VERSION 5.8 ;
BUSBITCHARS "[]" ;
DIVIDERCHAR "/" ;
UNITS
    DATABASE MICRONS 1000 ;
END UNITS

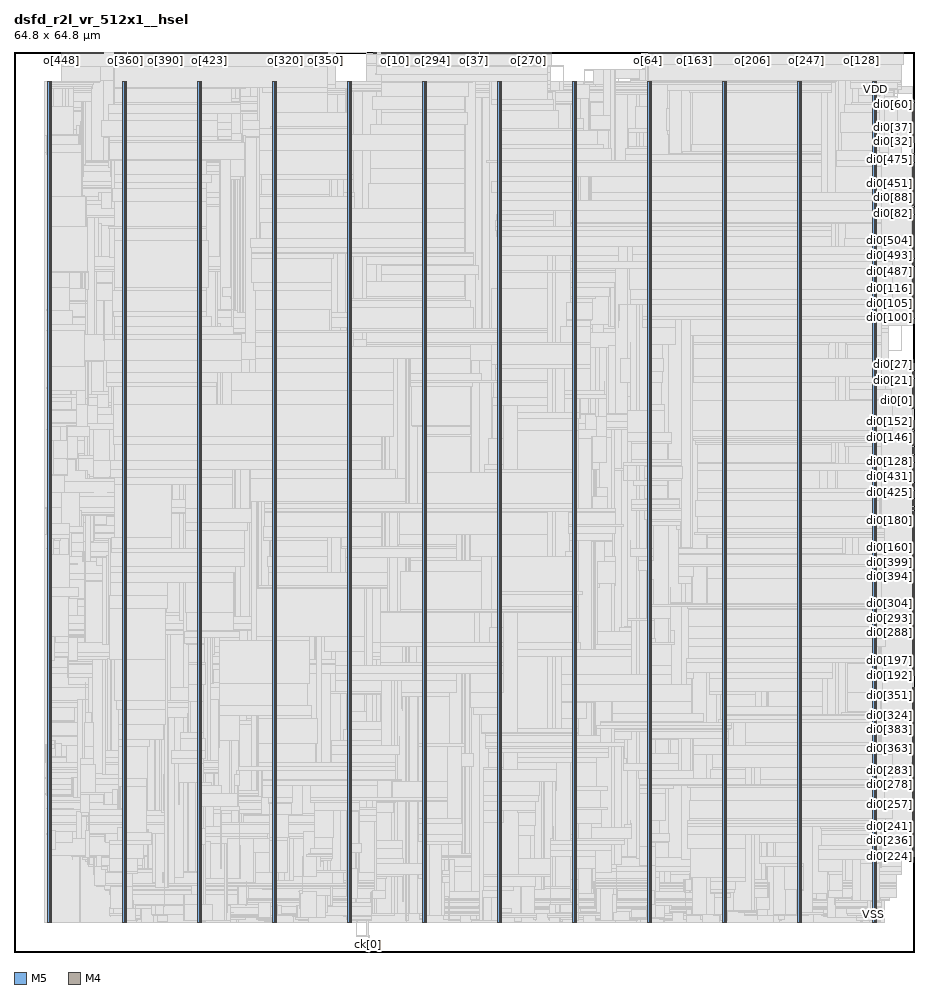
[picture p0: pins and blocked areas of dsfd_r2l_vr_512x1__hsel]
MACRO dsfd_r2l_vr_512x1__hsel
  FOREIGN dsfd_r2l_vr_512x1__hsel 0 0 ;
  CLASS BLOCK ;
  SIZE 64.8 BY 64.8 ;
  PIN ck[0]
    DIRECTION INPUT ;
    USE SIGNAL ;
    PORT
      LAYER M5 ;
        RECT  25.488 0 25.512 0.084 ;
    END
  END ck[0]
  PIN di0[0]
    DIRECTION INPUT ;
    USE SIGNAL ;
    PORT
      LAYER M4 ;
        RECT  64.716 39.12 64.8 39.144 ;
    END
  END di0[0]
  PIN di0[100]
    DIRECTION INPUT ;
    USE SIGNAL ;
    PORT
      LAYER M4 ;
        RECT  64.716 45.648 64.8 45.672 ;
    END
  END di0[100]
  PIN di0[101]
    DIRECTION INPUT ;
    USE SIGNAL ;
    PORT
      LAYER M4 ;
        RECT  64.716 45.744 64.8 45.768 ;
    END
  END di0[101]
  PIN di0[102]
    DIRECTION INPUT ;
    USE SIGNAL ;
    PORT
      LAYER M4 ;
        RECT  64.716 45.84 64.8 45.864 ;
    END
  END di0[102]
  PIN di0[103]
    DIRECTION INPUT ;
    USE SIGNAL ;
    PORT
      LAYER M4 ;
        RECT  64.716 45.936 64.8 45.96 ;
    END
  END di0[103]
  PIN di0[104]
    DIRECTION INPUT ;
    USE SIGNAL ;
    PORT
      LAYER M4 ;
        RECT  64.716 46.032 64.8 46.056 ;
    END
  END di0[104]
  PIN di0[105]
    DIRECTION INPUT ;
    USE SIGNAL ;
    PORT
      LAYER M4 ;
        RECT  64.716 46.128 64.8 46.152 ;
    END
  END di0[105]
  PIN di0[106]
    DIRECTION INPUT ;
    USE SIGNAL ;
    PORT
      LAYER M4 ;
        RECT  64.716 46.224 64.8 46.248 ;
    END
  END di0[106]
  PIN di0[107]
    DIRECTION INPUT ;
    USE SIGNAL ;
    PORT
      LAYER M4 ;
        RECT  64.716 46.32 64.8 46.344 ;
    END
  END di0[107]
  PIN di0[108]
    DIRECTION INPUT ;
    USE SIGNAL ;
    PORT
      LAYER M4 ;
        RECT  64.716 46.416 64.8 46.44 ;
    END
  END di0[108]
  PIN di0[109]
    DIRECTION INPUT ;
    USE SIGNAL ;
    PORT
      LAYER M4 ;
        RECT  64.716 46.512 64.8 46.536 ;
    END
  END di0[109]
  PIN di0[10]
    DIRECTION INPUT ;
    USE SIGNAL ;
    PORT
      LAYER M4 ;
        RECT  64.716 40.08 64.8 40.104 ;
    END
  END di0[10]
  PIN di0[110]
    DIRECTION INPUT ;
    USE SIGNAL ;
    PORT
      LAYER M4 ;
        RECT  64.716 46.608 64.8 46.632 ;
    END
  END di0[110]
  PIN di0[111]
    DIRECTION INPUT ;
    USE SIGNAL ;
    PORT
      LAYER M4 ;
        RECT  64.716 46.704 64.8 46.728 ;
    END
  END di0[111]
  PIN di0[112]
    DIRECTION INPUT ;
    USE SIGNAL ;
    PORT
      LAYER M4 ;
        RECT  64.716 46.8 64.8 46.824 ;
    END
  END di0[112]
  PIN di0[113]
    DIRECTION INPUT ;
    USE SIGNAL ;
    PORT
      LAYER M4 ;
        RECT  64.716 46.896 64.8 46.92 ;
    END
  END di0[113]
  PIN di0[114]
    DIRECTION INPUT ;
    USE SIGNAL ;
    PORT
      LAYER M4 ;
        RECT  64.716 46.992 64.8 47.016 ;
    END
  END di0[114]
  PIN di0[115]
    DIRECTION INPUT ;
    USE SIGNAL ;
    PORT
      LAYER M4 ;
        RECT  64.716 47.088 64.8 47.112 ;
    END
  END di0[115]
  PIN di0[116]
    DIRECTION INPUT ;
    USE SIGNAL ;
    PORT
      LAYER M4 ;
        RECT  64.716 47.184 64.8 47.208 ;
    END
  END di0[116]
  PIN di0[117]
    DIRECTION INPUT ;
    USE SIGNAL ;
    PORT
      LAYER M4 ;
        RECT  64.716 47.28 64.8 47.304 ;
    END
  END di0[117]
  PIN di0[118]
    DIRECTION INPUT ;
    USE SIGNAL ;
    PORT
      LAYER M4 ;
        RECT  64.716 47.376 64.8 47.4 ;
    END
  END di0[118]
  PIN di0[119]
    DIRECTION INPUT ;
    USE SIGNAL ;
    PORT
      LAYER M4 ;
        RECT  64.716 47.472 64.8 47.496 ;
    END
  END di0[119]
  PIN di0[11]
    DIRECTION INPUT ;
    USE SIGNAL ;
    PORT
      LAYER M4 ;
        RECT  64.716 40.176 64.8 40.2 ;
    END
  END di0[11]
  PIN di0[120]
    DIRECTION INPUT ;
    USE SIGNAL ;
    PORT
      LAYER M4 ;
        RECT  64.716 47.568 64.8 47.592 ;
    END
  END di0[120]
  PIN di0[121]
    DIRECTION INPUT ;
    USE SIGNAL ;
    PORT
      LAYER M4 ;
        RECT  64.716 47.664 64.8 47.688 ;
    END
  END di0[121]
  PIN di0[122]
    DIRECTION INPUT ;
    USE SIGNAL ;
    PORT
      LAYER M4 ;
        RECT  64.716 47.76 64.8 47.784 ;
    END
  END di0[122]
  PIN di0[123]
    DIRECTION INPUT ;
    USE SIGNAL ;
    PORT
      LAYER M4 ;
        RECT  64.716 47.856 64.8 47.88 ;
    END
  END di0[123]
  PIN di0[124]
    DIRECTION INPUT ;
    USE SIGNAL ;
    PORT
      LAYER M4 ;
        RECT  64.716 47.952 64.8 47.976 ;
    END
  END di0[124]
  PIN di0[125]
    DIRECTION INPUT ;
    USE SIGNAL ;
    PORT
      LAYER M4 ;
        RECT  64.716 48.048 64.8 48.072 ;
    END
  END di0[125]
  PIN di0[126]
    DIRECTION INPUT ;
    USE SIGNAL ;
    PORT
      LAYER M4 ;
        RECT  64.716 48.144 64.8 48.168 ;
    END
  END di0[126]
  PIN di0[127]
    DIRECTION INPUT ;
    USE SIGNAL ;
    PORT
      LAYER M4 ;
        RECT  64.716 48.24 64.8 48.264 ;
    END
  END di0[127]
  PIN di0[128]
    DIRECTION INPUT ;
    USE SIGNAL ;
    PORT
      LAYER M4 ;
        RECT  64.716 35.28 64.8 35.304 ;
    END
  END di0[128]
  PIN di0[129]
    DIRECTION INPUT ;
    USE SIGNAL ;
    PORT
      LAYER M4 ;
        RECT  64.716 35.376 64.8 35.4 ;
    END
  END di0[129]
  PIN di0[12]
    DIRECTION INPUT ;
    USE SIGNAL ;
    PORT
      LAYER M4 ;
        RECT  64.716 40.272 64.8 40.296 ;
    END
  END di0[12]
  PIN di0[130]
    DIRECTION INPUT ;
    USE SIGNAL ;
    PORT
      LAYER M4 ;
        RECT  64.716 35.472 64.8 35.496 ;
    END
  END di0[130]
  PIN di0[131]
    DIRECTION INPUT ;
    USE SIGNAL ;
    PORT
      LAYER M4 ;
        RECT  64.716 35.568 64.8 35.592 ;
    END
  END di0[131]
  PIN di0[132]
    DIRECTION INPUT ;
    USE SIGNAL ;
    PORT
      LAYER M4 ;
        RECT  64.716 35.664 64.8 35.688 ;
    END
  END di0[132]
  PIN di0[133]
    DIRECTION INPUT ;
    USE SIGNAL ;
    PORT
      LAYER M4 ;
        RECT  64.716 35.76 64.8 35.784 ;
    END
  END di0[133]
  PIN di0[134]
    DIRECTION INPUT ;
    USE SIGNAL ;
    PORT
      LAYER M4 ;
        RECT  64.716 35.856 64.8 35.88 ;
    END
  END di0[134]
  PIN di0[135]
    DIRECTION INPUT ;
    USE SIGNAL ;
    PORT
      LAYER M4 ;
        RECT  64.716 35.952 64.8 35.976 ;
    END
  END di0[135]
  PIN di0[136]
    DIRECTION INPUT ;
    USE SIGNAL ;
    PORT
      LAYER M4 ;
        RECT  64.716 36.048 64.8 36.072 ;
    END
  END di0[136]
  PIN di0[137]
    DIRECTION INPUT ;
    USE SIGNAL ;
    PORT
      LAYER M4 ;
        RECT  64.716 36.144 64.8 36.168 ;
    END
  END di0[137]
  PIN di0[138]
    DIRECTION INPUT ;
    USE SIGNAL ;
    PORT
      LAYER M4 ;
        RECT  64.716 36.24 64.8 36.264 ;
    END
  END di0[138]
  PIN di0[139]
    DIRECTION INPUT ;
    USE SIGNAL ;
    PORT
      LAYER M4 ;
        RECT  64.716 36.336 64.8 36.36 ;
    END
  END di0[139]
  PIN di0[13]
    DIRECTION INPUT ;
    USE SIGNAL ;
    PORT
      LAYER M4 ;
        RECT  64.716 40.368 64.8 40.392 ;
    END
  END di0[13]
  PIN di0[140]
    DIRECTION INPUT ;
    USE SIGNAL ;
    PORT
      LAYER M4 ;
        RECT  64.716 36.432 64.8 36.456 ;
    END
  END di0[140]
  PIN di0[141]
    DIRECTION INPUT ;
    USE SIGNAL ;
    PORT
      LAYER M4 ;
        RECT  64.716 36.528 64.8 36.552 ;
    END
  END di0[141]
  PIN di0[142]
    DIRECTION INPUT ;
    USE SIGNAL ;
    PORT
      LAYER M4 ;
        RECT  64.716 36.624 64.8 36.648 ;
    END
  END di0[142]
  PIN di0[143]
    DIRECTION INPUT ;
    USE SIGNAL ;
    PORT
      LAYER M4 ;
        RECT  64.716 36.72 64.8 36.744 ;
    END
  END di0[143]
  PIN di0[144]
    DIRECTION INPUT ;
    USE SIGNAL ;
    PORT
      LAYER M4 ;
        RECT  64.716 36.816 64.8 36.84 ;
    END
  END di0[144]
  PIN di0[145]
    DIRECTION INPUT ;
    USE SIGNAL ;
    PORT
      LAYER M4 ;
        RECT  64.716 36.912 64.8 36.936 ;
    END
  END di0[145]
  PIN di0[146]
    DIRECTION INPUT ;
    USE SIGNAL ;
    PORT
      LAYER M4 ;
        RECT  64.716 37.008 64.8 37.032 ;
    END
  END di0[146]
  PIN di0[147]
    DIRECTION INPUT ;
    USE SIGNAL ;
    PORT
      LAYER M4 ;
        RECT  64.716 37.104 64.8 37.128 ;
    END
  END di0[147]
  PIN di0[148]
    DIRECTION INPUT ;
    USE SIGNAL ;
    PORT
      LAYER M4 ;
        RECT  64.716 37.2 64.8 37.224 ;
    END
  END di0[148]
  PIN di0[149]
    DIRECTION INPUT ;
    USE SIGNAL ;
    PORT
      LAYER M4 ;
        RECT  64.716 37.296 64.8 37.32 ;
    END
  END di0[149]
  PIN di0[14]
    DIRECTION INPUT ;
    USE SIGNAL ;
    PORT
      LAYER M4 ;
        RECT  64.716 40.464 64.8 40.488 ;
    END
  END di0[14]
  PIN di0[150]
    DIRECTION INPUT ;
    USE SIGNAL ;
    PORT
      LAYER M4 ;
        RECT  64.716 37.392 64.8 37.416 ;
    END
  END di0[150]
  PIN di0[151]
    DIRECTION INPUT ;
    USE SIGNAL ;
    PORT
      LAYER M4 ;
        RECT  64.716 37.488 64.8 37.512 ;
    END
  END di0[151]
  PIN di0[152]
    DIRECTION INPUT ;
    USE SIGNAL ;
    PORT
      LAYER M4 ;
        RECT  64.716 37.584 64.8 37.608 ;
    END
  END di0[152]
  PIN di0[153]
    DIRECTION INPUT ;
    USE SIGNAL ;
    PORT
      LAYER M4 ;
        RECT  64.716 37.68 64.8 37.704 ;
    END
  END di0[153]
  PIN di0[154]
    DIRECTION INPUT ;
    USE SIGNAL ;
    PORT
      LAYER M4 ;
        RECT  64.716 37.776 64.8 37.8 ;
    END
  END di0[154]
  PIN di0[155]
    DIRECTION INPUT ;
    USE SIGNAL ;
    PORT
      LAYER M4 ;
        RECT  64.716 37.872 64.8 37.896 ;
    END
  END di0[155]
  PIN di0[156]
    DIRECTION INPUT ;
    USE SIGNAL ;
    PORT
      LAYER M4 ;
        RECT  64.716 37.968 64.8 37.992 ;
    END
  END di0[156]
  PIN di0[157]
    DIRECTION INPUT ;
    USE SIGNAL ;
    PORT
      LAYER M4 ;
        RECT  64.716 38.064 64.8 38.088 ;
    END
  END di0[157]
  PIN di0[158]
    DIRECTION INPUT ;
    USE SIGNAL ;
    PORT
      LAYER M4 ;
        RECT  64.716 38.16 64.8 38.184 ;
    END
  END di0[158]
  PIN di0[159]
    DIRECTION INPUT ;
    USE SIGNAL ;
    PORT
      LAYER M4 ;
        RECT  64.716 38.256 64.8 38.28 ;
    END
  END di0[159]
  PIN di0[15]
    DIRECTION INPUT ;
    USE SIGNAL ;
    PORT
      LAYER M4 ;
        RECT  64.716 40.56 64.8 40.584 ;
    END
  END di0[15]
  PIN di0[160]
    DIRECTION INPUT ;
    USE SIGNAL ;
    PORT
      LAYER M4 ;
        RECT  64.716 29.136 64.8 29.16 ;
    END
  END di0[160]
  PIN di0[161]
    DIRECTION INPUT ;
    USE SIGNAL ;
    PORT
      LAYER M4 ;
        RECT  64.716 29.232 64.8 29.256 ;
    END
  END di0[161]
  PIN di0[162]
    DIRECTION INPUT ;
    USE SIGNAL ;
    PORT
      LAYER M4 ;
        RECT  64.716 29.328 64.8 29.352 ;
    END
  END di0[162]
  PIN di0[163]
    DIRECTION INPUT ;
    USE SIGNAL ;
    PORT
      LAYER M4 ;
        RECT  64.716 29.424 64.8 29.448 ;
    END
  END di0[163]
  PIN di0[164]
    DIRECTION INPUT ;
    USE SIGNAL ;
    PORT
      LAYER M4 ;
        RECT  64.716 29.52 64.8 29.544 ;
    END
  END di0[164]
  PIN di0[165]
    DIRECTION INPUT ;
    USE SIGNAL ;
    PORT
      LAYER M4 ;
        RECT  64.716 29.616 64.8 29.64 ;
    END
  END di0[165]
  PIN di0[166]
    DIRECTION INPUT ;
    USE SIGNAL ;
    PORT
      LAYER M4 ;
        RECT  64.716 29.712 64.8 29.736 ;
    END
  END di0[166]
  PIN di0[167]
    DIRECTION INPUT ;
    USE SIGNAL ;
    PORT
      LAYER M4 ;
        RECT  64.716 29.808 64.8 29.832 ;
    END
  END di0[167]
  PIN di0[168]
    DIRECTION INPUT ;
    USE SIGNAL ;
    PORT
      LAYER M4 ;
        RECT  64.716 29.904 64.8 29.928 ;
    END
  END di0[168]
  PIN di0[169]
    DIRECTION INPUT ;
    USE SIGNAL ;
    PORT
      LAYER M4 ;
        RECT  64.716 30 64.8 30.024 ;
    END
  END di0[169]
  PIN di0[16]
    DIRECTION INPUT ;
    USE SIGNAL ;
    PORT
      LAYER M4 ;
        RECT  64.716 40.656 64.8 40.68 ;
    END
  END di0[16]
  PIN di0[170]
    DIRECTION INPUT ;
    USE SIGNAL ;
    PORT
      LAYER M4 ;
        RECT  64.716 30.096 64.8 30.12 ;
    END
  END di0[170]
  PIN di0[171]
    DIRECTION INPUT ;
    USE SIGNAL ;
    PORT
      LAYER M4 ;
        RECT  64.716 30.192 64.8 30.216 ;
    END
  END di0[171]
  PIN di0[172]
    DIRECTION INPUT ;
    USE SIGNAL ;
    PORT
      LAYER M4 ;
        RECT  64.716 30.288 64.8 30.312 ;
    END
  END di0[172]
  PIN di0[173]
    DIRECTION INPUT ;
    USE SIGNAL ;
    PORT
      LAYER M4 ;
        RECT  64.716 30.384 64.8 30.408 ;
    END
  END di0[173]
  PIN di0[174]
    DIRECTION INPUT ;
    USE SIGNAL ;
    PORT
      LAYER M4 ;
        RECT  64.716 30.48 64.8 30.504 ;
    END
  END di0[174]
  PIN di0[175]
    DIRECTION INPUT ;
    USE SIGNAL ;
    PORT
      LAYER M4 ;
        RECT  64.716 30.576 64.8 30.6 ;
    END
  END di0[175]
  PIN di0[176]
    DIRECTION INPUT ;
    USE SIGNAL ;
    PORT
      LAYER M4 ;
        RECT  64.716 30.672 64.8 30.696 ;
    END
  END di0[176]
  PIN di0[177]
    DIRECTION INPUT ;
    USE SIGNAL ;
    PORT
      LAYER M4 ;
        RECT  64.716 30.768 64.8 30.792 ;
    END
  END di0[177]
  PIN di0[178]
    DIRECTION INPUT ;
    USE SIGNAL ;
    PORT
      LAYER M4 ;
        RECT  64.716 30.864 64.8 30.888 ;
    END
  END di0[178]
  PIN di0[179]
    DIRECTION INPUT ;
    USE SIGNAL ;
    PORT
      LAYER M4 ;
        RECT  64.716 30.96 64.8 30.984 ;
    END
  END di0[179]
  PIN di0[17]
    DIRECTION INPUT ;
    USE SIGNAL ;
    PORT
      LAYER M4 ;
        RECT  64.716 40.752 64.8 40.776 ;
    END
  END di0[17]
  PIN di0[180]
    DIRECTION INPUT ;
    USE SIGNAL ;
    PORT
      LAYER M4 ;
        RECT  64.716 31.056 64.8 31.08 ;
    END
  END di0[180]
  PIN di0[181]
    DIRECTION INPUT ;
    USE SIGNAL ;
    PORT
      LAYER M4 ;
        RECT  64.716 31.152 64.8 31.176 ;
    END
  END di0[181]
  PIN di0[182]
    DIRECTION INPUT ;
    USE SIGNAL ;
    PORT
      LAYER M4 ;
        RECT  64.716 31.248 64.8 31.272 ;
    END
  END di0[182]
  PIN di0[183]
    DIRECTION INPUT ;
    USE SIGNAL ;
    PORT
      LAYER M4 ;
        RECT  64.716 31.344 64.8 31.368 ;
    END
  END di0[183]
  PIN di0[184]
    DIRECTION INPUT ;
    USE SIGNAL ;
    PORT
      LAYER M4 ;
        RECT  64.716 31.44 64.8 31.464 ;
    END
  END di0[184]
  PIN di0[185]
    DIRECTION INPUT ;
    USE SIGNAL ;
    PORT
      LAYER M4 ;
        RECT  64.716 31.536 64.8 31.56 ;
    END
  END di0[185]
  PIN di0[186]
    DIRECTION INPUT ;
    USE SIGNAL ;
    PORT
      LAYER M4 ;
        RECT  64.716 31.632 64.8 31.656 ;
    END
  END di0[186]
  PIN di0[187]
    DIRECTION INPUT ;
    USE SIGNAL ;
    PORT
      LAYER M4 ;
        RECT  64.716 31.728 64.8 31.752 ;
    END
  END di0[187]
  PIN di0[188]
    DIRECTION INPUT ;
    USE SIGNAL ;
    PORT
      LAYER M4 ;
        RECT  64.716 31.824 64.8 31.848 ;
    END
  END di0[188]
  PIN di0[189]
    DIRECTION INPUT ;
    USE SIGNAL ;
    PORT
      LAYER M4 ;
        RECT  64.716 31.92 64.8 31.944 ;
    END
  END di0[189]
  PIN di0[18]
    DIRECTION INPUT ;
    USE SIGNAL ;
    PORT
      LAYER M4 ;
        RECT  64.716 40.848 64.8 40.872 ;
    END
  END di0[18]
  PIN di0[190]
    DIRECTION INPUT ;
    USE SIGNAL ;
    PORT
      LAYER M4 ;
        RECT  64.716 32.016 64.8 32.04 ;
    END
  END di0[190]
  PIN di0[191]
    DIRECTION INPUT ;
    USE SIGNAL ;
    PORT
      LAYER M4 ;
        RECT  64.716 32.112 64.8 32.136 ;
    END
  END di0[191]
  PIN di0[192]
    DIRECTION INPUT ;
    USE SIGNAL ;
    PORT
      LAYER M4 ;
        RECT  64.716 19.92 64.8 19.944 ;
    END
  END di0[192]
  PIN di0[193]
    DIRECTION INPUT ;
    USE SIGNAL ;
    PORT
      LAYER M4 ;
        RECT  64.716 20.016 64.8 20.04 ;
    END
  END di0[193]
  PIN di0[194]
    DIRECTION INPUT ;
    USE SIGNAL ;
    PORT
      LAYER M4 ;
        RECT  64.716 20.112 64.8 20.136 ;
    END
  END di0[194]
  PIN di0[195]
    DIRECTION INPUT ;
    USE SIGNAL ;
    PORT
      LAYER M4 ;
        RECT  64.716 20.208 64.8 20.232 ;
    END
  END di0[195]
  PIN di0[196]
    DIRECTION INPUT ;
    USE SIGNAL ;
    PORT
      LAYER M4 ;
        RECT  64.716 20.304 64.8 20.328 ;
    END
  END di0[196]
  PIN di0[197]
    DIRECTION INPUT ;
    USE SIGNAL ;
    PORT
      LAYER M4 ;
        RECT  64.716 20.4 64.8 20.424 ;
    END
  END di0[197]
  PIN di0[198]
    DIRECTION INPUT ;
    USE SIGNAL ;
    PORT
      LAYER M4 ;
        RECT  64.716 20.496 64.8 20.52 ;
    END
  END di0[198]
  PIN di0[199]
    DIRECTION INPUT ;
    USE SIGNAL ;
    PORT
      LAYER M4 ;
        RECT  64.716 20.592 64.8 20.616 ;
    END
  END di0[199]
  PIN di0[19]
    DIRECTION INPUT ;
    USE SIGNAL ;
    PORT
      LAYER M4 ;
        RECT  64.716 40.944 64.8 40.968 ;
    END
  END di0[19]
  PIN di0[1]
    DIRECTION INPUT ;
    USE SIGNAL ;
    PORT
      LAYER M4 ;
        RECT  64.716 39.216 64.8 39.24 ;
    END
  END di0[1]
  PIN di0[200]
    DIRECTION INPUT ;
    USE SIGNAL ;
    PORT
      LAYER M4 ;
        RECT  64.716 20.688 64.8 20.712 ;
    END
  END di0[200]
  PIN di0[201]
    DIRECTION INPUT ;
    USE SIGNAL ;
    PORT
      LAYER M4 ;
        RECT  64.716 20.784 64.8 20.808 ;
    END
  END di0[201]
  PIN di0[202]
    DIRECTION INPUT ;
    USE SIGNAL ;
    PORT
      LAYER M4 ;
        RECT  64.716 20.88 64.8 20.904 ;
    END
  END di0[202]
  PIN di0[203]
    DIRECTION INPUT ;
    USE SIGNAL ;
    PORT
      LAYER M4 ;
        RECT  64.716 20.976 64.8 21 ;
    END
  END di0[203]
  PIN di0[204]
    DIRECTION INPUT ;
    USE SIGNAL ;
    PORT
      LAYER M4 ;
        RECT  64.716 21.072 64.8 21.096 ;
    END
  END di0[204]
  PIN di0[205]
    DIRECTION INPUT ;
    USE SIGNAL ;
    PORT
      LAYER M4 ;
        RECT  64.716 21.168 64.8 21.192 ;
    END
  END di0[205]
  PIN di0[206]
    DIRECTION INPUT ;
    USE SIGNAL ;
    PORT
      LAYER M4 ;
        RECT  64.716 21.264 64.8 21.288 ;
    END
  END di0[206]
  PIN di0[207]
    DIRECTION INPUT ;
    USE SIGNAL ;
    PORT
      LAYER M4 ;
        RECT  64.716 21.36 64.8 21.384 ;
    END
  END di0[207]
  PIN di0[208]
    DIRECTION INPUT ;
    USE SIGNAL ;
    PORT
      LAYER M4 ;
        RECT  64.716 21.456 64.8 21.48 ;
    END
  END di0[208]
  PIN di0[209]
    DIRECTION INPUT ;
    USE SIGNAL ;
    PORT
      LAYER M4 ;
        RECT  64.716 21.552 64.8 21.576 ;
    END
  END di0[209]
  PIN di0[20]
    DIRECTION INPUT ;
    USE SIGNAL ;
    PORT
      LAYER M4 ;
        RECT  64.716 41.04 64.8 41.064 ;
    END
  END di0[20]
  PIN di0[210]
    DIRECTION INPUT ;
    USE SIGNAL ;
    PORT
      LAYER M4 ;
        RECT  64.716 21.648 64.8 21.672 ;
    END
  END di0[210]
  PIN di0[211]
    DIRECTION INPUT ;
    USE SIGNAL ;
    PORT
      LAYER M4 ;
        RECT  64.716 21.744 64.8 21.768 ;
    END
  END di0[211]
  PIN di0[212]
    DIRECTION INPUT ;
    USE SIGNAL ;
    PORT
      LAYER M4 ;
        RECT  64.716 21.84 64.8 21.864 ;
    END
  END di0[212]
  PIN di0[213]
    DIRECTION INPUT ;
    USE SIGNAL ;
    PORT
      LAYER M4 ;
        RECT  64.716 21.936 64.8 21.96 ;
    END
  END di0[213]
  PIN di0[214]
    DIRECTION INPUT ;
    USE SIGNAL ;
    PORT
      LAYER M4 ;
        RECT  64.716 22.032 64.8 22.056 ;
    END
  END di0[214]
  PIN di0[215]
    DIRECTION INPUT ;
    USE SIGNAL ;
    PORT
      LAYER M4 ;
        RECT  64.716 22.128 64.8 22.152 ;
    END
  END di0[215]
  PIN di0[216]
    DIRECTION INPUT ;
    USE SIGNAL ;
    PORT
      LAYER M4 ;
        RECT  64.716 22.224 64.8 22.248 ;
    END
  END di0[216]
  PIN di0[217]
    DIRECTION INPUT ;
    USE SIGNAL ;
    PORT
      LAYER M4 ;
        RECT  64.716 22.32 64.8 22.344 ;
    END
  END di0[217]
  PIN di0[218]
    DIRECTION INPUT ;
    USE SIGNAL ;
    PORT
      LAYER M4 ;
        RECT  64.716 22.416 64.8 22.44 ;
    END
  END di0[218]
  PIN di0[219]
    DIRECTION INPUT ;
    USE SIGNAL ;
    PORT
      LAYER M4 ;
        RECT  64.716 22.512 64.8 22.536 ;
    END
  END di0[219]
  PIN di0[21]
    DIRECTION INPUT ;
    USE SIGNAL ;
    PORT
      LAYER M4 ;
        RECT  64.716 41.136 64.8 41.16 ;
    END
  END di0[21]
  PIN di0[220]
    DIRECTION INPUT ;
    USE SIGNAL ;
    PORT
      LAYER M4 ;
        RECT  64.716 22.608 64.8 22.632 ;
    END
  END di0[220]
  PIN di0[221]
    DIRECTION INPUT ;
    USE SIGNAL ;
    PORT
      LAYER M4 ;
        RECT  64.716 22.704 64.8 22.728 ;
    END
  END di0[221]
  PIN di0[222]
    DIRECTION INPUT ;
    USE SIGNAL ;
    PORT
      LAYER M4 ;
        RECT  64.716 22.8 64.8 22.824 ;
    END
  END di0[222]
  PIN di0[223]
    DIRECTION INPUT ;
    USE SIGNAL ;
    PORT
      LAYER M4 ;
        RECT  64.716 22.896 64.8 22.92 ;
    END
  END di0[223]
  PIN di0[224]
    DIRECTION INPUT ;
    USE SIGNAL ;
    PORT
      LAYER M4 ;
        RECT  64.716 6.864 64.8 6.888 ;
    END
  END di0[224]
  PIN di0[225]
    DIRECTION INPUT ;
    USE SIGNAL ;
    PORT
      LAYER M4 ;
        RECT  64.716 6.96 64.8 6.984 ;
    END
  END di0[225]
  PIN di0[226]
    DIRECTION INPUT ;
    USE SIGNAL ;
    PORT
      LAYER M4 ;
        RECT  64.716 7.056 64.8 7.08 ;
    END
  END di0[226]
  PIN di0[227]
    DIRECTION INPUT ;
    USE SIGNAL ;
    PORT
      LAYER M4 ;
        RECT  64.716 7.152 64.8 7.176 ;
    END
  END di0[227]
  PIN di0[228]
    DIRECTION INPUT ;
    USE SIGNAL ;
    PORT
      LAYER M4 ;
        RECT  64.716 7.248 64.8 7.272 ;
    END
  END di0[228]
  PIN di0[229]
    DIRECTION INPUT ;
    USE SIGNAL ;
    PORT
      LAYER M4 ;
        RECT  64.716 7.344 64.8 7.368 ;
    END
  END di0[229]
  PIN di0[22]
    DIRECTION INPUT ;
    USE SIGNAL ;
    PORT
      LAYER M4 ;
        RECT  64.716 41.232 64.8 41.256 ;
    END
  END di0[22]
  PIN di0[230]
    DIRECTION INPUT ;
    USE SIGNAL ;
    PORT
      LAYER M4 ;
        RECT  64.716 7.44 64.8 7.464 ;
    END
  END di0[230]
  PIN di0[231]
    DIRECTION INPUT ;
    USE SIGNAL ;
    PORT
      LAYER M4 ;
        RECT  64.716 7.536 64.8 7.56 ;
    END
  END di0[231]
  PIN di0[232]
    DIRECTION INPUT ;
    USE SIGNAL ;
    PORT
      LAYER M4 ;
        RECT  64.716 7.632 64.8 7.656 ;
    END
  END di0[232]
  PIN di0[233]
    DIRECTION INPUT ;
    USE SIGNAL ;
    PORT
      LAYER M4 ;
        RECT  64.716 7.728 64.8 7.752 ;
    END
  END di0[233]
  PIN di0[234]
    DIRECTION INPUT ;
    USE SIGNAL ;
    PORT
      LAYER M4 ;
        RECT  64.716 7.824 64.8 7.848 ;
    END
  END di0[234]
  PIN di0[235]
    DIRECTION INPUT ;
    USE SIGNAL ;
    PORT
      LAYER M4 ;
        RECT  64.716 7.92 64.8 7.944 ;
    END
  END di0[235]
  PIN di0[236]
    DIRECTION INPUT ;
    USE SIGNAL ;
    PORT
      LAYER M4 ;
        RECT  64.716 8.016 64.8 8.04 ;
    END
  END di0[236]
  PIN di0[237]
    DIRECTION INPUT ;
    USE SIGNAL ;
    PORT
      LAYER M4 ;
        RECT  64.716 8.112 64.8 8.136 ;
    END
  END di0[237]
  PIN di0[238]
    DIRECTION INPUT ;
    USE SIGNAL ;
    PORT
      LAYER M4 ;
        RECT  64.716 8.208 64.8 8.232 ;
    END
  END di0[238]
  PIN di0[239]
    DIRECTION INPUT ;
    USE SIGNAL ;
    PORT
      LAYER M4 ;
        RECT  64.716 8.304 64.8 8.328 ;
    END
  END di0[239]
  PIN di0[23]
    DIRECTION INPUT ;
    USE SIGNAL ;
    PORT
      LAYER M4 ;
        RECT  64.716 41.328 64.8 41.352 ;
    END
  END di0[23]
  PIN di0[240]
    DIRECTION INPUT ;
    USE SIGNAL ;
    PORT
      LAYER M4 ;
        RECT  64.716 8.4 64.8 8.424 ;
    END
  END di0[240]
  PIN di0[241]
    DIRECTION INPUT ;
    USE SIGNAL ;
    PORT
      LAYER M4 ;
        RECT  64.716 8.496 64.8 8.52 ;
    END
  END di0[241]
  PIN di0[242]
    DIRECTION INPUT ;
    USE SIGNAL ;
    PORT
      LAYER M4 ;
        RECT  64.716 8.592 64.8 8.616 ;
    END
  END di0[242]
  PIN di0[243]
    DIRECTION INPUT ;
    USE SIGNAL ;
    PORT
      LAYER M4 ;
        RECT  64.716 8.688 64.8 8.712 ;
    END
  END di0[243]
  PIN di0[244]
    DIRECTION INPUT ;
    USE SIGNAL ;
    PORT
      LAYER M4 ;
        RECT  64.716 8.784 64.8 8.808 ;
    END
  END di0[244]
  PIN di0[245]
    DIRECTION INPUT ;
    USE SIGNAL ;
    PORT
      LAYER M4 ;
        RECT  64.716 8.88 64.8 8.904 ;
    END
  END di0[245]
  PIN di0[246]
    DIRECTION INPUT ;
    USE SIGNAL ;
    PORT
      LAYER M4 ;
        RECT  64.716 8.976 64.8 9 ;
    END
  END di0[246]
  PIN di0[247]
    DIRECTION INPUT ;
    USE SIGNAL ;
    PORT
      LAYER M4 ;
        RECT  64.716 9.072 64.8 9.096 ;
    END
  END di0[247]
  PIN di0[248]
    DIRECTION INPUT ;
    USE SIGNAL ;
    PORT
      LAYER M4 ;
        RECT  64.716 9.168 64.8 9.192 ;
    END
  END di0[248]
  PIN di0[249]
    DIRECTION INPUT ;
    USE SIGNAL ;
    PORT
      LAYER M4 ;
        RECT  64.716 9.264 64.8 9.288 ;
    END
  END di0[249]
  PIN di0[24]
    DIRECTION INPUT ;
    USE SIGNAL ;
    PORT
      LAYER M4 ;
        RECT  64.716 41.424 64.8 41.448 ;
    END
  END di0[24]
  PIN di0[250]
    DIRECTION INPUT ;
    USE SIGNAL ;
    PORT
      LAYER M4 ;
        RECT  64.716 9.36 64.8 9.384 ;
    END
  END di0[250]
  PIN di0[251]
    DIRECTION INPUT ;
    USE SIGNAL ;
    PORT
      LAYER M4 ;
        RECT  64.716 9.456 64.8 9.48 ;
    END
  END di0[251]
  PIN di0[252]
    DIRECTION INPUT ;
    USE SIGNAL ;
    PORT
      LAYER M4 ;
        RECT  64.716 9.552 64.8 9.576 ;
    END
  END di0[252]
  PIN di0[253]
    DIRECTION INPUT ;
    USE SIGNAL ;
    PORT
      LAYER M4 ;
        RECT  64.716 9.648 64.8 9.672 ;
    END
  END di0[253]
  PIN di0[254]
    DIRECTION INPUT ;
    USE SIGNAL ;
    PORT
      LAYER M4 ;
        RECT  64.716 9.744 64.8 9.768 ;
    END
  END di0[254]
  PIN di0[255]
    DIRECTION INPUT ;
    USE SIGNAL ;
    PORT
      LAYER M4 ;
        RECT  64.716 9.84 64.8 9.864 ;
    END
  END di0[255]
  PIN di0[256]
    DIRECTION INPUT ;
    USE SIGNAL ;
    PORT
      LAYER M4 ;
        RECT  64.716 9.936 64.8 9.96 ;
    END
  END di0[256]
  PIN di0[257]
    DIRECTION INPUT ;
    USE SIGNAL ;
    PORT
      LAYER M4 ;
        RECT  64.716 10.032 64.8 10.056 ;
    END
  END di0[257]
  PIN di0[258]
    DIRECTION INPUT ;
    USE SIGNAL ;
    PORT
      LAYER M4 ;
        RECT  64.716 10.128 64.8 10.152 ;
    END
  END di0[258]
  PIN di0[259]
    DIRECTION INPUT ;
    USE SIGNAL ;
    PORT
      LAYER M4 ;
        RECT  64.716 10.224 64.8 10.248 ;
    END
  END di0[259]
  PIN di0[25]
    DIRECTION INPUT ;
    USE SIGNAL ;
    PORT
      LAYER M4 ;
        RECT  64.716 41.52 64.8 41.544 ;
    END
  END di0[25]
  PIN di0[260]
    DIRECTION INPUT ;
    USE SIGNAL ;
    PORT
      LAYER M4 ;
        RECT  64.716 10.32 64.8 10.344 ;
    END
  END di0[260]
  PIN di0[261]
    DIRECTION INPUT ;
    USE SIGNAL ;
    PORT
      LAYER M4 ;
        RECT  64.716 10.416 64.8 10.44 ;
    END
  END di0[261]
  PIN di0[262]
    DIRECTION INPUT ;
    USE SIGNAL ;
    PORT
      LAYER M4 ;
        RECT  64.716 10.512 64.8 10.536 ;
    END
  END di0[262]
  PIN di0[263]
    DIRECTION INPUT ;
    USE SIGNAL ;
    PORT
      LAYER M4 ;
        RECT  64.716 10.608 64.8 10.632 ;
    END
  END di0[263]
  PIN di0[264]
    DIRECTION INPUT ;
    USE SIGNAL ;
    PORT
      LAYER M4 ;
        RECT  64.716 10.704 64.8 10.728 ;
    END
  END di0[264]
  PIN di0[265]
    DIRECTION INPUT ;
    USE SIGNAL ;
    PORT
      LAYER M4 ;
        RECT  64.716 10.8 64.8 10.824 ;
    END
  END di0[265]
  PIN di0[266]
    DIRECTION INPUT ;
    USE SIGNAL ;
    PORT
      LAYER M4 ;
        RECT  64.716 10.896 64.8 10.92 ;
    END
  END di0[266]
  PIN di0[267]
    DIRECTION INPUT ;
    USE SIGNAL ;
    PORT
      LAYER M4 ;
        RECT  64.716 10.992 64.8 11.016 ;
    END
  END di0[267]
  PIN di0[268]
    DIRECTION INPUT ;
    USE SIGNAL ;
    PORT
      LAYER M4 ;
        RECT  64.716 11.088 64.8 11.112 ;
    END
  END di0[268]
  PIN di0[269]
    DIRECTION INPUT ;
    USE SIGNAL ;
    PORT
      LAYER M4 ;
        RECT  64.716 11.184 64.8 11.208 ;
    END
  END di0[269]
  PIN di0[26]
    DIRECTION INPUT ;
    USE SIGNAL ;
    PORT
      LAYER M4 ;
        RECT  64.716 41.616 64.8 41.64 ;
    END
  END di0[26]
  PIN di0[270]
    DIRECTION INPUT ;
    USE SIGNAL ;
    PORT
      LAYER M4 ;
        RECT  64.716 11.28 64.8 11.304 ;
    END
  END di0[270]
  PIN di0[271]
    DIRECTION INPUT ;
    USE SIGNAL ;
    PORT
      LAYER M4 ;
        RECT  64.716 11.376 64.8 11.4 ;
    END
  END di0[271]
  PIN di0[272]
    DIRECTION INPUT ;
    USE SIGNAL ;
    PORT
      LAYER M4 ;
        RECT  64.716 11.472 64.8 11.496 ;
    END
  END di0[272]
  PIN di0[273]
    DIRECTION INPUT ;
    USE SIGNAL ;
    PORT
      LAYER M4 ;
        RECT  64.716 11.568 64.8 11.592 ;
    END
  END di0[273]
  PIN di0[274]
    DIRECTION INPUT ;
    USE SIGNAL ;
    PORT
      LAYER M4 ;
        RECT  64.716 11.664 64.8 11.688 ;
    END
  END di0[274]
  PIN di0[275]
    DIRECTION INPUT ;
    USE SIGNAL ;
    PORT
      LAYER M4 ;
        RECT  64.716 11.76 64.8 11.784 ;
    END
  END di0[275]
  PIN di0[276]
    DIRECTION INPUT ;
    USE SIGNAL ;
    PORT
      LAYER M4 ;
        RECT  64.716 11.856 64.8 11.88 ;
    END
  END di0[276]
  PIN di0[277]
    DIRECTION INPUT ;
    USE SIGNAL ;
    PORT
      LAYER M4 ;
        RECT  64.716 11.952 64.8 11.976 ;
    END
  END di0[277]
  PIN di0[278]
    DIRECTION INPUT ;
    USE SIGNAL ;
    PORT
      LAYER M4 ;
        RECT  64.716 12.048 64.8 12.072 ;
    END
  END di0[278]
  PIN di0[279]
    DIRECTION INPUT ;
    USE SIGNAL ;
    PORT
      LAYER M4 ;
        RECT  64.716 12.144 64.8 12.168 ;
    END
  END di0[279]
  PIN di0[27]
    DIRECTION INPUT ;
    USE SIGNAL ;
    PORT
      LAYER M4 ;
        RECT  64.716 41.712 64.8 41.736 ;
    END
  END di0[27]
  PIN di0[280]
    DIRECTION INPUT ;
    USE SIGNAL ;
    PORT
      LAYER M4 ;
        RECT  64.716 12.24 64.8 12.264 ;
    END
  END di0[280]
  PIN di0[281]
    DIRECTION INPUT ;
    USE SIGNAL ;
    PORT
      LAYER M4 ;
        RECT  64.716 12.336 64.8 12.36 ;
    END
  END di0[281]
  PIN di0[282]
    DIRECTION INPUT ;
    USE SIGNAL ;
    PORT
      LAYER M4 ;
        RECT  64.716 12.432 64.8 12.456 ;
    END
  END di0[282]
  PIN di0[283]
    DIRECTION INPUT ;
    USE SIGNAL ;
    PORT
      LAYER M4 ;
        RECT  64.716 12.528 64.8 12.552 ;
    END
  END di0[283]
  PIN di0[284]
    DIRECTION INPUT ;
    USE SIGNAL ;
    PORT
      LAYER M4 ;
        RECT  64.716 12.624 64.8 12.648 ;
    END
  END di0[284]
  PIN di0[285]
    DIRECTION INPUT ;
    USE SIGNAL ;
    PORT
      LAYER M4 ;
        RECT  64.716 12.72 64.8 12.744 ;
    END
  END di0[285]
  PIN di0[286]
    DIRECTION INPUT ;
    USE SIGNAL ;
    PORT
      LAYER M4 ;
        RECT  64.716 12.816 64.8 12.84 ;
    END
  END di0[286]
  PIN di0[287]
    DIRECTION INPUT ;
    USE SIGNAL ;
    PORT
      LAYER M4 ;
        RECT  64.716 12.912 64.8 12.936 ;
    END
  END di0[287]
  PIN di0[288]
    DIRECTION INPUT ;
    USE SIGNAL ;
    PORT
      LAYER M4 ;
        RECT  64.716 22.992 64.8 23.016 ;
    END
  END di0[288]
  PIN di0[289]
    DIRECTION INPUT ;
    USE SIGNAL ;
    PORT
      LAYER M4 ;
        RECT  64.716 23.088 64.8 23.112 ;
    END
  END di0[289]
  PIN di0[28]
    DIRECTION INPUT ;
    USE SIGNAL ;
    PORT
      LAYER M4 ;
        RECT  64.716 41.808 64.8 41.832 ;
    END
  END di0[28]
  PIN di0[290]
    DIRECTION INPUT ;
    USE SIGNAL ;
    PORT
      LAYER M4 ;
        RECT  64.716 23.184 64.8 23.208 ;
    END
  END di0[290]
  PIN di0[291]
    DIRECTION INPUT ;
    USE SIGNAL ;
    PORT
      LAYER M4 ;
        RECT  64.716 23.28 64.8 23.304 ;
    END
  END di0[291]
  PIN di0[292]
    DIRECTION INPUT ;
    USE SIGNAL ;
    PORT
      LAYER M4 ;
        RECT  64.716 23.376 64.8 23.4 ;
    END
  END di0[292]
  PIN di0[293]
    DIRECTION INPUT ;
    USE SIGNAL ;
    PORT
      LAYER M4 ;
        RECT  64.716 23.472 64.8 23.496 ;
    END
  END di0[293]
  PIN di0[294]
    DIRECTION INPUT ;
    USE SIGNAL ;
    PORT
      LAYER M4 ;
        RECT  64.716 23.568 64.8 23.592 ;
    END
  END di0[294]
  PIN di0[295]
    DIRECTION INPUT ;
    USE SIGNAL ;
    PORT
      LAYER M4 ;
        RECT  64.716 23.664 64.8 23.688 ;
    END
  END di0[295]
  PIN di0[296]
    DIRECTION INPUT ;
    USE SIGNAL ;
    PORT
      LAYER M4 ;
        RECT  64.716 23.76 64.8 23.784 ;
    END
  END di0[296]
  PIN di0[297]
    DIRECTION INPUT ;
    USE SIGNAL ;
    PORT
      LAYER M4 ;
        RECT  64.716 23.856 64.8 23.88 ;
    END
  END di0[297]
  PIN di0[298]
    DIRECTION INPUT ;
    USE SIGNAL ;
    PORT
      LAYER M4 ;
        RECT  64.716 23.952 64.8 23.976 ;
    END
  END di0[298]
  PIN di0[299]
    DIRECTION INPUT ;
    USE SIGNAL ;
    PORT
      LAYER M4 ;
        RECT  64.716 24.048 64.8 24.072 ;
    END
  END di0[299]
  PIN di0[29]
    DIRECTION INPUT ;
    USE SIGNAL ;
    PORT
      LAYER M4 ;
        RECT  64.716 41.904 64.8 41.928 ;
    END
  END di0[29]
  PIN di0[2]
    DIRECTION INPUT ;
    USE SIGNAL ;
    PORT
      LAYER M4 ;
        RECT  64.716 39.312 64.8 39.336 ;
    END
  END di0[2]
  PIN di0[300]
    DIRECTION INPUT ;
    USE SIGNAL ;
    PORT
      LAYER M4 ;
        RECT  64.716 24.144 64.8 24.168 ;
    END
  END di0[300]
  PIN di0[301]
    DIRECTION INPUT ;
    USE SIGNAL ;
    PORT
      LAYER M4 ;
        RECT  64.716 24.24 64.8 24.264 ;
    END
  END di0[301]
  PIN di0[302]
    DIRECTION INPUT ;
    USE SIGNAL ;
    PORT
      LAYER M4 ;
        RECT  64.716 24.336 64.8 24.36 ;
    END
  END di0[302]
  PIN di0[303]
    DIRECTION INPUT ;
    USE SIGNAL ;
    PORT
      LAYER M4 ;
        RECT  64.716 24.432 64.8 24.456 ;
    END
  END di0[303]
  PIN di0[304]
    DIRECTION INPUT ;
    USE SIGNAL ;
    PORT
      LAYER M4 ;
        RECT  64.716 24.528 64.8 24.552 ;
    END
  END di0[304]
  PIN di0[305]
    DIRECTION INPUT ;
    USE SIGNAL ;
    PORT
      LAYER M4 ;
        RECT  64.716 24.624 64.8 24.648 ;
    END
  END di0[305]
  PIN di0[306]
    DIRECTION INPUT ;
    USE SIGNAL ;
    PORT
      LAYER M4 ;
        RECT  64.716 24.72 64.8 24.744 ;
    END
  END di0[306]
  PIN di0[307]
    DIRECTION INPUT ;
    USE SIGNAL ;
    PORT
      LAYER M4 ;
        RECT  64.716 24.816 64.8 24.84 ;
    END
  END di0[307]
  PIN di0[308]
    DIRECTION INPUT ;
    USE SIGNAL ;
    PORT
      LAYER M4 ;
        RECT  64.716 24.912 64.8 24.936 ;
    END
  END di0[308]
  PIN di0[309]
    DIRECTION INPUT ;
    USE SIGNAL ;
    PORT
      LAYER M4 ;
        RECT  64.716 25.008 64.8 25.032 ;
    END
  END di0[309]
  PIN di0[30]
    DIRECTION INPUT ;
    USE SIGNAL ;
    PORT
      LAYER M4 ;
        RECT  64.716 42 64.8 42.024 ;
    END
  END di0[30]
  PIN di0[310]
    DIRECTION INPUT ;
    USE SIGNAL ;
    PORT
      LAYER M4 ;
        RECT  64.716 25.104 64.8 25.128 ;
    END
  END di0[310]
  PIN di0[311]
    DIRECTION INPUT ;
    USE SIGNAL ;
    PORT
      LAYER M4 ;
        RECT  64.716 25.2 64.8 25.224 ;
    END
  END di0[311]
  PIN di0[312]
    DIRECTION INPUT ;
    USE SIGNAL ;
    PORT
      LAYER M4 ;
        RECT  64.716 25.296 64.8 25.32 ;
    END
  END di0[312]
  PIN di0[313]
    DIRECTION INPUT ;
    USE SIGNAL ;
    PORT
      LAYER M4 ;
        RECT  64.716 25.392 64.8 25.416 ;
    END
  END di0[313]
  PIN di0[314]
    DIRECTION INPUT ;
    USE SIGNAL ;
    PORT
      LAYER M4 ;
        RECT  64.716 25.488 64.8 25.512 ;
    END
  END di0[314]
  PIN di0[315]
    DIRECTION INPUT ;
    USE SIGNAL ;
    PORT
      LAYER M4 ;
        RECT  64.716 25.584 64.8 25.608 ;
    END
  END di0[315]
  PIN di0[316]
    DIRECTION INPUT ;
    USE SIGNAL ;
    PORT
      LAYER M4 ;
        RECT  64.716 25.68 64.8 25.704 ;
    END
  END di0[316]
  PIN di0[317]
    DIRECTION INPUT ;
    USE SIGNAL ;
    PORT
      LAYER M4 ;
        RECT  64.716 25.776 64.8 25.8 ;
    END
  END di0[317]
  PIN di0[318]
    DIRECTION INPUT ;
    USE SIGNAL ;
    PORT
      LAYER M4 ;
        RECT  64.716 25.872 64.8 25.896 ;
    END
  END di0[318]
  PIN di0[319]
    DIRECTION INPUT ;
    USE SIGNAL ;
    PORT
      LAYER M4 ;
        RECT  64.716 25.968 64.8 25.992 ;
    END
  END di0[319]
  PIN di0[31]
    DIRECTION INPUT ;
    USE SIGNAL ;
    PORT
      LAYER M4 ;
        RECT  64.716 42.096 64.8 42.12 ;
    END
  END di0[31]
  PIN di0[320]
    DIRECTION INPUT ;
    USE SIGNAL ;
    PORT
      LAYER M4 ;
        RECT  64.716 16.08 64.8 16.104 ;
    END
  END di0[320]
  PIN di0[321]
    DIRECTION INPUT ;
    USE SIGNAL ;
    PORT
      LAYER M4 ;
        RECT  64.716 16.176 64.8 16.2 ;
    END
  END di0[321]
  PIN di0[322]
    DIRECTION INPUT ;
    USE SIGNAL ;
    PORT
      LAYER M4 ;
        RECT  64.716 16.272 64.8 16.296 ;
    END
  END di0[322]
  PIN di0[323]
    DIRECTION INPUT ;
    USE SIGNAL ;
    PORT
      LAYER M4 ;
        RECT  64.716 16.368 64.8 16.392 ;
    END
  END di0[323]
  PIN di0[324]
    DIRECTION INPUT ;
    USE SIGNAL ;
    PORT
      LAYER M4 ;
        RECT  64.716 16.464 64.8 16.488 ;
    END
  END di0[324]
  PIN di0[325]
    DIRECTION INPUT ;
    USE SIGNAL ;
    PORT
      LAYER M4 ;
        RECT  64.716 16.56 64.8 16.584 ;
    END
  END di0[325]
  PIN di0[326]
    DIRECTION INPUT ;
    USE SIGNAL ;
    PORT
      LAYER M4 ;
        RECT  64.716 16.656 64.8 16.68 ;
    END
  END di0[326]
  PIN di0[327]
    DIRECTION INPUT ;
    USE SIGNAL ;
    PORT
      LAYER M4 ;
        RECT  64.716 16.752 64.8 16.776 ;
    END
  END di0[327]
  PIN di0[328]
    DIRECTION INPUT ;
    USE SIGNAL ;
    PORT
      LAYER M4 ;
        RECT  64.716 16.848 64.8 16.872 ;
    END
  END di0[328]
  PIN di0[329]
    DIRECTION INPUT ;
    USE SIGNAL ;
    PORT
      LAYER M4 ;
        RECT  64.716 16.944 64.8 16.968 ;
    END
  END di0[329]
  PIN di0[32]
    DIRECTION INPUT ;
    USE SIGNAL ;
    PORT
      LAYER M4 ;
        RECT  64.716 58.32 64.8 58.344 ;
    END
  END di0[32]
  PIN di0[330]
    DIRECTION INPUT ;
    USE SIGNAL ;
    PORT
      LAYER M4 ;
        RECT  64.716 17.04 64.8 17.064 ;
    END
  END di0[330]
  PIN di0[331]
    DIRECTION INPUT ;
    USE SIGNAL ;
    PORT
      LAYER M4 ;
        RECT  64.716 17.136 64.8 17.16 ;
    END
  END di0[331]
  PIN di0[332]
    DIRECTION INPUT ;
    USE SIGNAL ;
    PORT
      LAYER M4 ;
        RECT  64.716 17.232 64.8 17.256 ;
    END
  END di0[332]
  PIN di0[333]
    DIRECTION INPUT ;
    USE SIGNAL ;
    PORT
      LAYER M4 ;
        RECT  64.716 17.328 64.8 17.352 ;
    END
  END di0[333]
  PIN di0[334]
    DIRECTION INPUT ;
    USE SIGNAL ;
    PORT
      LAYER M4 ;
        RECT  64.716 17.424 64.8 17.448 ;
    END
  END di0[334]
  PIN di0[335]
    DIRECTION INPUT ;
    USE SIGNAL ;
    PORT
      LAYER M4 ;
        RECT  64.716 17.52 64.8 17.544 ;
    END
  END di0[335]
  PIN di0[336]
    DIRECTION INPUT ;
    USE SIGNAL ;
    PORT
      LAYER M4 ;
        RECT  64.716 17.616 64.8 17.64 ;
    END
  END di0[336]
  PIN di0[337]
    DIRECTION INPUT ;
    USE SIGNAL ;
    PORT
      LAYER M4 ;
        RECT  64.716 17.712 64.8 17.736 ;
    END
  END di0[337]
  PIN di0[338]
    DIRECTION INPUT ;
    USE SIGNAL ;
    PORT
      LAYER M4 ;
        RECT  64.716 17.808 64.8 17.832 ;
    END
  END di0[338]
  PIN di0[339]
    DIRECTION INPUT ;
    USE SIGNAL ;
    PORT
      LAYER M4 ;
        RECT  64.716 17.904 64.8 17.928 ;
    END
  END di0[339]
  PIN di0[33]
    DIRECTION INPUT ;
    USE SIGNAL ;
    PORT
      LAYER M4 ;
        RECT  64.716 58.416 64.8 58.44 ;
    END
  END di0[33]
  PIN di0[340]
    DIRECTION INPUT ;
    USE SIGNAL ;
    PORT
      LAYER M4 ;
        RECT  64.716 18 64.8 18.024 ;
    END
  END di0[340]
  PIN di0[341]
    DIRECTION INPUT ;
    USE SIGNAL ;
    PORT
      LAYER M4 ;
        RECT  64.716 18.096 64.8 18.12 ;
    END
  END di0[341]
  PIN di0[342]
    DIRECTION INPUT ;
    USE SIGNAL ;
    PORT
      LAYER M4 ;
        RECT  64.716 18.192 64.8 18.216 ;
    END
  END di0[342]
  PIN di0[343]
    DIRECTION INPUT ;
    USE SIGNAL ;
    PORT
      LAYER M4 ;
        RECT  64.716 18.288 64.8 18.312 ;
    END
  END di0[343]
  PIN di0[344]
    DIRECTION INPUT ;
    USE SIGNAL ;
    PORT
      LAYER M4 ;
        RECT  64.716 18.384 64.8 18.408 ;
    END
  END di0[344]
  PIN di0[345]
    DIRECTION INPUT ;
    USE SIGNAL ;
    PORT
      LAYER M4 ;
        RECT  64.716 18.48 64.8 18.504 ;
    END
  END di0[345]
  PIN di0[346]
    DIRECTION INPUT ;
    USE SIGNAL ;
    PORT
      LAYER M4 ;
        RECT  64.716 18.576 64.8 18.6 ;
    END
  END di0[346]
  PIN di0[347]
    DIRECTION INPUT ;
    USE SIGNAL ;
    PORT
      LAYER M4 ;
        RECT  64.716 18.672 64.8 18.696 ;
    END
  END di0[347]
  PIN di0[348]
    DIRECTION INPUT ;
    USE SIGNAL ;
    PORT
      LAYER M4 ;
        RECT  64.716 18.768 64.8 18.792 ;
    END
  END di0[348]
  PIN di0[349]
    DIRECTION INPUT ;
    USE SIGNAL ;
    PORT
      LAYER M4 ;
        RECT  64.716 18.864 64.8 18.888 ;
    END
  END di0[349]
  PIN di0[34]
    DIRECTION INPUT ;
    USE SIGNAL ;
    PORT
      LAYER M4 ;
        RECT  64.716 58.512 64.8 58.536 ;
    END
  END di0[34]
  PIN di0[350]
    DIRECTION INPUT ;
    USE SIGNAL ;
    PORT
      LAYER M4 ;
        RECT  64.716 18.96 64.8 18.984 ;
    END
  END di0[350]
  PIN di0[351]
    DIRECTION INPUT ;
    USE SIGNAL ;
    PORT
      LAYER M4 ;
        RECT  64.716 19.056 64.8 19.08 ;
    END
  END di0[351]
  PIN di0[352]
    DIRECTION INPUT ;
    USE SIGNAL ;
    PORT
      LAYER M4 ;
        RECT  64.716 13.008 64.8 13.032 ;
    END
  END di0[352]
  PIN di0[353]
    DIRECTION INPUT ;
    USE SIGNAL ;
    PORT
      LAYER M4 ;
        RECT  64.716 13.104 64.8 13.128 ;
    END
  END di0[353]
  PIN di0[354]
    DIRECTION INPUT ;
    USE SIGNAL ;
    PORT
      LAYER M4 ;
        RECT  64.716 13.2 64.8 13.224 ;
    END
  END di0[354]
  PIN di0[355]
    DIRECTION INPUT ;
    USE SIGNAL ;
    PORT
      LAYER M4 ;
        RECT  64.716 13.296 64.8 13.32 ;
    END
  END di0[355]
  PIN di0[356]
    DIRECTION INPUT ;
    USE SIGNAL ;
    PORT
      LAYER M4 ;
        RECT  64.716 13.392 64.8 13.416 ;
    END
  END di0[356]
  PIN di0[357]
    DIRECTION INPUT ;
    USE SIGNAL ;
    PORT
      LAYER M4 ;
        RECT  64.716 13.488 64.8 13.512 ;
    END
  END di0[357]
  PIN di0[358]
    DIRECTION INPUT ;
    USE SIGNAL ;
    PORT
      LAYER M4 ;
        RECT  64.716 13.584 64.8 13.608 ;
    END
  END di0[358]
  PIN di0[359]
    DIRECTION INPUT ;
    USE SIGNAL ;
    PORT
      LAYER M4 ;
        RECT  64.716 13.68 64.8 13.704 ;
    END
  END di0[359]
  PIN di0[35]
    DIRECTION INPUT ;
    USE SIGNAL ;
    PORT
      LAYER M4 ;
        RECT  64.716 58.608 64.8 58.632 ;
    END
  END di0[35]
  PIN di0[360]
    DIRECTION INPUT ;
    USE SIGNAL ;
    PORT
      LAYER M4 ;
        RECT  64.716 13.776 64.8 13.8 ;
    END
  END di0[360]
  PIN di0[361]
    DIRECTION INPUT ;
    USE SIGNAL ;
    PORT
      LAYER M4 ;
        RECT  64.716 13.872 64.8 13.896 ;
    END
  END di0[361]
  PIN di0[362]
    DIRECTION INPUT ;
    USE SIGNAL ;
    PORT
      LAYER M4 ;
        RECT  64.716 13.968 64.8 13.992 ;
    END
  END di0[362]
  PIN di0[363]
    DIRECTION INPUT ;
    USE SIGNAL ;
    PORT
      LAYER M4 ;
        RECT  64.716 14.064 64.8 14.088 ;
    END
  END di0[363]
  PIN di0[364]
    DIRECTION INPUT ;
    USE SIGNAL ;
    PORT
      LAYER M4 ;
        RECT  64.716 14.16 64.8 14.184 ;
    END
  END di0[364]
  PIN di0[365]
    DIRECTION INPUT ;
    USE SIGNAL ;
    PORT
      LAYER M4 ;
        RECT  64.716 14.256 64.8 14.28 ;
    END
  END di0[365]
  PIN di0[366]
    DIRECTION INPUT ;
    USE SIGNAL ;
    PORT
      LAYER M4 ;
        RECT  64.716 14.352 64.8 14.376 ;
    END
  END di0[366]
  PIN di0[367]
    DIRECTION INPUT ;
    USE SIGNAL ;
    PORT
      LAYER M4 ;
        RECT  64.716 14.448 64.8 14.472 ;
    END
  END di0[367]
  PIN di0[368]
    DIRECTION INPUT ;
    USE SIGNAL ;
    PORT
      LAYER M4 ;
        RECT  64.716 14.544 64.8 14.568 ;
    END
  END di0[368]
  PIN di0[369]
    DIRECTION INPUT ;
    USE SIGNAL ;
    PORT
      LAYER M4 ;
        RECT  64.716 14.64 64.8 14.664 ;
    END
  END di0[369]
  PIN di0[36]
    DIRECTION INPUT ;
    USE SIGNAL ;
    PORT
      LAYER M4 ;
        RECT  64.716 58.704 64.8 58.728 ;
    END
  END di0[36]
  PIN di0[370]
    DIRECTION INPUT ;
    USE SIGNAL ;
    PORT
      LAYER M4 ;
        RECT  64.716 14.736 64.8 14.76 ;
    END
  END di0[370]
  PIN di0[371]
    DIRECTION INPUT ;
    USE SIGNAL ;
    PORT
      LAYER M4 ;
        RECT  64.716 14.832 64.8 14.856 ;
    END
  END di0[371]
  PIN di0[372]
    DIRECTION INPUT ;
    USE SIGNAL ;
    PORT
      LAYER M4 ;
        RECT  64.716 14.928 64.8 14.952 ;
    END
  END di0[372]
  PIN di0[373]
    DIRECTION INPUT ;
    USE SIGNAL ;
    PORT
      LAYER M4 ;
        RECT  64.716 15.024 64.8 15.048 ;
    END
  END di0[373]
  PIN di0[374]
    DIRECTION INPUT ;
    USE SIGNAL ;
    PORT
      LAYER M4 ;
        RECT  64.716 15.12 64.8 15.144 ;
    END
  END di0[374]
  PIN di0[375]
    DIRECTION INPUT ;
    USE SIGNAL ;
    PORT
      LAYER M4 ;
        RECT  64.716 15.216 64.8 15.24 ;
    END
  END di0[375]
  PIN di0[376]
    DIRECTION INPUT ;
    USE SIGNAL ;
    PORT
      LAYER M4 ;
        RECT  64.716 15.312 64.8 15.336 ;
    END
  END di0[376]
  PIN di0[377]
    DIRECTION INPUT ;
    USE SIGNAL ;
    PORT
      LAYER M4 ;
        RECT  64.716 15.408 64.8 15.432 ;
    END
  END di0[377]
  PIN di0[378]
    DIRECTION INPUT ;
    USE SIGNAL ;
    PORT
      LAYER M4 ;
        RECT  64.716 15.504 64.8 15.528 ;
    END
  END di0[378]
  PIN di0[379]
    DIRECTION INPUT ;
    USE SIGNAL ;
    PORT
      LAYER M4 ;
        RECT  64.716 15.6 64.8 15.624 ;
    END
  END di0[379]
  PIN di0[37]
    DIRECTION INPUT ;
    USE SIGNAL ;
    PORT
      LAYER M4 ;
        RECT  64.716 58.8 64.8 58.824 ;
    END
  END di0[37]
  PIN di0[380]
    DIRECTION INPUT ;
    USE SIGNAL ;
    PORT
      LAYER M4 ;
        RECT  64.716 15.696 64.8 15.72 ;
    END
  END di0[380]
  PIN di0[381]
    DIRECTION INPUT ;
    USE SIGNAL ;
    PORT
      LAYER M4 ;
        RECT  64.716 15.792 64.8 15.816 ;
    END
  END di0[381]
  PIN di0[382]
    DIRECTION INPUT ;
    USE SIGNAL ;
    PORT
      LAYER M4 ;
        RECT  64.716 15.888 64.8 15.912 ;
    END
  END di0[382]
  PIN di0[383]
    DIRECTION INPUT ;
    USE SIGNAL ;
    PORT
      LAYER M4 ;
        RECT  64.716 15.984 64.8 16.008 ;
    END
  END di0[383]
  PIN di0[384]
    DIRECTION INPUT ;
    USE SIGNAL ;
    PORT
      LAYER M4 ;
        RECT  64.716 26.064 64.8 26.088 ;
    END
  END di0[384]
  PIN di0[385]
    DIRECTION INPUT ;
    USE SIGNAL ;
    PORT
      LAYER M4 ;
        RECT  64.716 26.16 64.8 26.184 ;
    END
  END di0[385]
  PIN di0[386]
    DIRECTION INPUT ;
    USE SIGNAL ;
    PORT
      LAYER M4 ;
        RECT  64.716 26.256 64.8 26.28 ;
    END
  END di0[386]
  PIN di0[387]
    DIRECTION INPUT ;
    USE SIGNAL ;
    PORT
      LAYER M4 ;
        RECT  64.716 26.352 64.8 26.376 ;
    END
  END di0[387]
  PIN di0[388]
    DIRECTION INPUT ;
    USE SIGNAL ;
    PORT
      LAYER M4 ;
        RECT  64.716 26.448 64.8 26.472 ;
    END
  END di0[388]
  PIN di0[389]
    DIRECTION INPUT ;
    USE SIGNAL ;
    PORT
      LAYER M4 ;
        RECT  64.716 26.544 64.8 26.568 ;
    END
  END di0[389]
  PIN di0[38]
    DIRECTION INPUT ;
    USE SIGNAL ;
    PORT
      LAYER M4 ;
        RECT  64.716 58.896 64.8 58.92 ;
    END
  END di0[38]
  PIN di0[390]
    DIRECTION INPUT ;
    USE SIGNAL ;
    PORT
      LAYER M4 ;
        RECT  64.716 26.64 64.8 26.664 ;
    END
  END di0[390]
  PIN di0[391]
    DIRECTION INPUT ;
    USE SIGNAL ;
    PORT
      LAYER M4 ;
        RECT  64.716 26.736 64.8 26.76 ;
    END
  END di0[391]
  PIN di0[392]
    DIRECTION INPUT ;
    USE SIGNAL ;
    PORT
      LAYER M4 ;
        RECT  64.716 26.832 64.8 26.856 ;
    END
  END di0[392]
  PIN di0[393]
    DIRECTION INPUT ;
    USE SIGNAL ;
    PORT
      LAYER M4 ;
        RECT  64.716 26.928 64.8 26.952 ;
    END
  END di0[393]
  PIN di0[394]
    DIRECTION INPUT ;
    USE SIGNAL ;
    PORT
      LAYER M4 ;
        RECT  64.716 27.024 64.8 27.048 ;
    END
  END di0[394]
  PIN di0[395]
    DIRECTION INPUT ;
    USE SIGNAL ;
    PORT
      LAYER M4 ;
        RECT  64.716 27.12 64.8 27.144 ;
    END
  END di0[395]
  PIN di0[396]
    DIRECTION INPUT ;
    USE SIGNAL ;
    PORT
      LAYER M4 ;
        RECT  64.716 27.216 64.8 27.24 ;
    END
  END di0[396]
  PIN di0[397]
    DIRECTION INPUT ;
    USE SIGNAL ;
    PORT
      LAYER M4 ;
        RECT  64.716 27.312 64.8 27.336 ;
    END
  END di0[397]
  PIN di0[398]
    DIRECTION INPUT ;
    USE SIGNAL ;
    PORT
      LAYER M4 ;
        RECT  64.716 27.408 64.8 27.432 ;
    END
  END di0[398]
  PIN di0[399]
    DIRECTION INPUT ;
    USE SIGNAL ;
    PORT
      LAYER M4 ;
        RECT  64.716 27.504 64.8 27.528 ;
    END
  END di0[399]
  PIN di0[39]
    DIRECTION INPUT ;
    USE SIGNAL ;
    PORT
      LAYER M4 ;
        RECT  64.716 58.992 64.8 59.016 ;
    END
  END di0[39]
  PIN di0[3]
    DIRECTION INPUT ;
    USE SIGNAL ;
    PORT
      LAYER M4 ;
        RECT  64.716 39.408 64.8 39.432 ;
    END
  END di0[3]
  PIN di0[400]
    DIRECTION INPUT ;
    USE SIGNAL ;
    PORT
      LAYER M4 ;
        RECT  64.716 27.6 64.8 27.624 ;
    END
  END di0[400]
  PIN di0[401]
    DIRECTION INPUT ;
    USE SIGNAL ;
    PORT
      LAYER M4 ;
        RECT  64.716 27.696 64.8 27.72 ;
    END
  END di0[401]
  PIN di0[402]
    DIRECTION INPUT ;
    USE SIGNAL ;
    PORT
      LAYER M4 ;
        RECT  64.716 27.792 64.8 27.816 ;
    END
  END di0[402]
  PIN di0[403]
    DIRECTION INPUT ;
    USE SIGNAL ;
    PORT
      LAYER M4 ;
        RECT  64.716 27.888 64.8 27.912 ;
    END
  END di0[403]
  PIN di0[404]
    DIRECTION INPUT ;
    USE SIGNAL ;
    PORT
      LAYER M4 ;
        RECT  64.716 27.984 64.8 28.008 ;
    END
  END di0[404]
  PIN di0[405]
    DIRECTION INPUT ;
    USE SIGNAL ;
    PORT
      LAYER M4 ;
        RECT  64.716 28.08 64.8 28.104 ;
    END
  END di0[405]
  PIN di0[406]
    DIRECTION INPUT ;
    USE SIGNAL ;
    PORT
      LAYER M4 ;
        RECT  64.716 28.176 64.8 28.2 ;
    END
  END di0[406]
  PIN di0[407]
    DIRECTION INPUT ;
    USE SIGNAL ;
    PORT
      LAYER M4 ;
        RECT  64.716 28.272 64.8 28.296 ;
    END
  END di0[407]
  PIN di0[408]
    DIRECTION INPUT ;
    USE SIGNAL ;
    PORT
      LAYER M4 ;
        RECT  64.716 28.368 64.8 28.392 ;
    END
  END di0[408]
  PIN di0[409]
    DIRECTION INPUT ;
    USE SIGNAL ;
    PORT
      LAYER M4 ;
        RECT  64.716 28.464 64.8 28.488 ;
    END
  END di0[409]
  PIN di0[40]
    DIRECTION INPUT ;
    USE SIGNAL ;
    PORT
      LAYER M4 ;
        RECT  64.716 59.088 64.8 59.112 ;
    END
  END di0[40]
  PIN di0[410]
    DIRECTION INPUT ;
    USE SIGNAL ;
    PORT
      LAYER M4 ;
        RECT  64.716 28.56 64.8 28.584 ;
    END
  END di0[410]
  PIN di0[411]
    DIRECTION INPUT ;
    USE SIGNAL ;
    PORT
      LAYER M4 ;
        RECT  64.716 28.656 64.8 28.68 ;
    END
  END di0[411]
  PIN di0[412]
    DIRECTION INPUT ;
    USE SIGNAL ;
    PORT
      LAYER M4 ;
        RECT  64.716 28.752 64.8 28.776 ;
    END
  END di0[412]
  PIN di0[413]
    DIRECTION INPUT ;
    USE SIGNAL ;
    PORT
      LAYER M4 ;
        RECT  64.716 28.848 64.8 28.872 ;
    END
  END di0[413]
  PIN di0[414]
    DIRECTION INPUT ;
    USE SIGNAL ;
    PORT
      LAYER M4 ;
        RECT  64.716 28.944 64.8 28.968 ;
    END
  END di0[414]
  PIN di0[415]
    DIRECTION INPUT ;
    USE SIGNAL ;
    PORT
      LAYER M4 ;
        RECT  64.716 29.04 64.8 29.064 ;
    END
  END di0[415]
  PIN di0[416]
    DIRECTION INPUT ;
    USE SIGNAL ;
    PORT
      LAYER M4 ;
        RECT  64.716 32.208 64.8 32.232 ;
    END
  END di0[416]
  PIN di0[417]
    DIRECTION INPUT ;
    USE SIGNAL ;
    PORT
      LAYER M4 ;
        RECT  64.716 32.304 64.8 32.328 ;
    END
  END di0[417]
  PIN di0[418]
    DIRECTION INPUT ;
    USE SIGNAL ;
    PORT
      LAYER M4 ;
        RECT  64.716 32.4 64.8 32.424 ;
    END
  END di0[418]
  PIN di0[419]
    DIRECTION INPUT ;
    USE SIGNAL ;
    PORT
      LAYER M4 ;
        RECT  64.716 32.496 64.8 32.52 ;
    END
  END di0[419]
  PIN di0[41]
    DIRECTION INPUT ;
    USE SIGNAL ;
    PORT
      LAYER M4 ;
        RECT  64.716 59.184 64.8 59.208 ;
    END
  END di0[41]
  PIN di0[420]
    DIRECTION INPUT ;
    USE SIGNAL ;
    PORT
      LAYER M4 ;
        RECT  64.716 32.592 64.8 32.616 ;
    END
  END di0[420]
  PIN di0[421]
    DIRECTION INPUT ;
    USE SIGNAL ;
    PORT
      LAYER M4 ;
        RECT  64.716 32.688 64.8 32.712 ;
    END
  END di0[421]
  PIN di0[422]
    DIRECTION INPUT ;
    USE SIGNAL ;
    PORT
      LAYER M4 ;
        RECT  64.716 32.784 64.8 32.808 ;
    END
  END di0[422]
  PIN di0[423]
    DIRECTION INPUT ;
    USE SIGNAL ;
    PORT
      LAYER M4 ;
        RECT  64.716 32.88 64.8 32.904 ;
    END
  END di0[423]
  PIN di0[424]
    DIRECTION INPUT ;
    USE SIGNAL ;
    PORT
      LAYER M4 ;
        RECT  64.716 32.976 64.8 33 ;
    END
  END di0[424]
  PIN di0[425]
    DIRECTION INPUT ;
    USE SIGNAL ;
    PORT
      LAYER M4 ;
        RECT  64.716 33.072 64.8 33.096 ;
    END
  END di0[425]
  PIN di0[426]
    DIRECTION INPUT ;
    USE SIGNAL ;
    PORT
      LAYER M4 ;
        RECT  64.716 33.168 64.8 33.192 ;
    END
  END di0[426]
  PIN di0[427]
    DIRECTION INPUT ;
    USE SIGNAL ;
    PORT
      LAYER M4 ;
        RECT  64.716 33.264 64.8 33.288 ;
    END
  END di0[427]
  PIN di0[428]
    DIRECTION INPUT ;
    USE SIGNAL ;
    PORT
      LAYER M4 ;
        RECT  64.716 33.36 64.8 33.384 ;
    END
  END di0[428]
  PIN di0[429]
    DIRECTION INPUT ;
    USE SIGNAL ;
    PORT
      LAYER M4 ;
        RECT  64.716 33.456 64.8 33.48 ;
    END
  END di0[429]
  PIN di0[42]
    DIRECTION INPUT ;
    USE SIGNAL ;
    PORT
      LAYER M4 ;
        RECT  64.716 59.28 64.8 59.304 ;
    END
  END di0[42]
  PIN di0[430]
    DIRECTION INPUT ;
    USE SIGNAL ;
    PORT
      LAYER M4 ;
        RECT  64.716 33.552 64.8 33.576 ;
    END
  END di0[430]
  PIN di0[431]
    DIRECTION INPUT ;
    USE SIGNAL ;
    PORT
      LAYER M4 ;
        RECT  64.716 33.648 64.8 33.672 ;
    END
  END di0[431]
  PIN di0[432]
    DIRECTION INPUT ;
    USE SIGNAL ;
    PORT
      LAYER M4 ;
        RECT  64.716 33.744 64.8 33.768 ;
    END
  END di0[432]
  PIN di0[433]
    DIRECTION INPUT ;
    USE SIGNAL ;
    PORT
      LAYER M4 ;
        RECT  64.716 33.84 64.8 33.864 ;
    END
  END di0[433]
  PIN di0[434]
    DIRECTION INPUT ;
    USE SIGNAL ;
    PORT
      LAYER M4 ;
        RECT  64.716 33.936 64.8 33.96 ;
    END
  END di0[434]
  PIN di0[435]
    DIRECTION INPUT ;
    USE SIGNAL ;
    PORT
      LAYER M4 ;
        RECT  64.716 34.032 64.8 34.056 ;
    END
  END di0[435]
  PIN di0[436]
    DIRECTION INPUT ;
    USE SIGNAL ;
    PORT
      LAYER M4 ;
        RECT  64.716 34.128 64.8 34.152 ;
    END
  END di0[436]
  PIN di0[437]
    DIRECTION INPUT ;
    USE SIGNAL ;
    PORT
      LAYER M4 ;
        RECT  64.716 34.224 64.8 34.248 ;
    END
  END di0[437]
  PIN di0[438]
    DIRECTION INPUT ;
    USE SIGNAL ;
    PORT
      LAYER M4 ;
        RECT  64.716 34.32 64.8 34.344 ;
    END
  END di0[438]
  PIN di0[439]
    DIRECTION INPUT ;
    USE SIGNAL ;
    PORT
      LAYER M4 ;
        RECT  64.716 34.416 64.8 34.44 ;
    END
  END di0[439]
  PIN di0[43]
    DIRECTION INPUT ;
    USE SIGNAL ;
    PORT
      LAYER M4 ;
        RECT  64.716 59.376 64.8 59.4 ;
    END
  END di0[43]
  PIN di0[440]
    DIRECTION INPUT ;
    USE SIGNAL ;
    PORT
      LAYER M4 ;
        RECT  64.716 34.512 64.8 34.536 ;
    END
  END di0[440]
  PIN di0[441]
    DIRECTION INPUT ;
    USE SIGNAL ;
    PORT
      LAYER M4 ;
        RECT  64.716 34.608 64.8 34.632 ;
    END
  END di0[441]
  PIN di0[442]
    DIRECTION INPUT ;
    USE SIGNAL ;
    PORT
      LAYER M4 ;
        RECT  64.716 34.704 64.8 34.728 ;
    END
  END di0[442]
  PIN di0[443]
    DIRECTION INPUT ;
    USE SIGNAL ;
    PORT
      LAYER M4 ;
        RECT  64.716 34.8 64.8 34.824 ;
    END
  END di0[443]
  PIN di0[444]
    DIRECTION INPUT ;
    USE SIGNAL ;
    PORT
      LAYER M4 ;
        RECT  64.716 34.896 64.8 34.92 ;
    END
  END di0[444]
  PIN di0[445]
    DIRECTION INPUT ;
    USE SIGNAL ;
    PORT
      LAYER M4 ;
        RECT  64.716 34.992 64.8 35.016 ;
    END
  END di0[445]
  PIN di0[446]
    DIRECTION INPUT ;
    USE SIGNAL ;
    PORT
      LAYER M4 ;
        RECT  64.716 35.088 64.8 35.112 ;
    END
  END di0[446]
  PIN di0[447]
    DIRECTION INPUT ;
    USE SIGNAL ;
    PORT
      LAYER M4 ;
        RECT  64.716 35.184 64.8 35.208 ;
    END
  END di0[447]
  PIN di0[448]
    DIRECTION INPUT ;
    USE SIGNAL ;
    PORT
      LAYER M4 ;
        RECT  64.716 54.48 64.8 54.504 ;
    END
  END di0[448]
  PIN di0[449]
    DIRECTION INPUT ;
    USE SIGNAL ;
    PORT
      LAYER M4 ;
        RECT  64.716 54.576 64.8 54.6 ;
    END
  END di0[449]
  PIN di0[44]
    DIRECTION INPUT ;
    USE SIGNAL ;
    PORT
      LAYER M4 ;
        RECT  64.716 59.472 64.8 59.496 ;
    END
  END di0[44]
  PIN di0[450]
    DIRECTION INPUT ;
    USE SIGNAL ;
    PORT
      LAYER M4 ;
        RECT  64.716 54.672 64.8 54.696 ;
    END
  END di0[450]
  PIN di0[451]
    DIRECTION INPUT ;
    USE SIGNAL ;
    PORT
      LAYER M4 ;
        RECT  64.716 54.768 64.8 54.792 ;
    END
  END di0[451]
  PIN di0[452]
    DIRECTION INPUT ;
    USE SIGNAL ;
    PORT
      LAYER M4 ;
        RECT  64.716 54.864 64.8 54.888 ;
    END
  END di0[452]
  PIN di0[453]
    DIRECTION INPUT ;
    USE SIGNAL ;
    PORT
      LAYER M4 ;
        RECT  64.716 54.96 64.8 54.984 ;
    END
  END di0[453]
  PIN di0[454]
    DIRECTION INPUT ;
    USE SIGNAL ;
    PORT
      LAYER M4 ;
        RECT  64.716 55.056 64.8 55.08 ;
    END
  END di0[454]
  PIN di0[455]
    DIRECTION INPUT ;
    USE SIGNAL ;
    PORT
      LAYER M4 ;
        RECT  64.716 55.152 64.8 55.176 ;
    END
  END di0[455]
  PIN di0[456]
    DIRECTION INPUT ;
    USE SIGNAL ;
    PORT
      LAYER M4 ;
        RECT  64.716 55.248 64.8 55.272 ;
    END
  END di0[456]
  PIN di0[457]
    DIRECTION INPUT ;
    USE SIGNAL ;
    PORT
      LAYER M4 ;
        RECT  64.716 55.344 64.8 55.368 ;
    END
  END di0[457]
  PIN di0[458]
    DIRECTION INPUT ;
    USE SIGNAL ;
    PORT
      LAYER M4 ;
        RECT  64.716 55.44 64.8 55.464 ;
    END
  END di0[458]
  PIN di0[459]
    DIRECTION INPUT ;
    USE SIGNAL ;
    PORT
      LAYER M4 ;
        RECT  64.716 55.536 64.8 55.56 ;
    END
  END di0[459]
  PIN di0[45]
    DIRECTION INPUT ;
    USE SIGNAL ;
    PORT
      LAYER M4 ;
        RECT  64.716 59.568 64.8 59.592 ;
    END
  END di0[45]
  PIN di0[460]
    DIRECTION INPUT ;
    USE SIGNAL ;
    PORT
      LAYER M4 ;
        RECT  64.716 55.632 64.8 55.656 ;
    END
  END di0[460]
  PIN di0[461]
    DIRECTION INPUT ;
    USE SIGNAL ;
    PORT
      LAYER M4 ;
        RECT  64.716 55.728 64.8 55.752 ;
    END
  END di0[461]
  PIN di0[462]
    DIRECTION INPUT ;
    USE SIGNAL ;
    PORT
      LAYER M4 ;
        RECT  64.716 55.824 64.8 55.848 ;
    END
  END di0[462]
  PIN di0[463]
    DIRECTION INPUT ;
    USE SIGNAL ;
    PORT
      LAYER M4 ;
        RECT  64.716 55.92 64.8 55.944 ;
    END
  END di0[463]
  PIN di0[464]
    DIRECTION INPUT ;
    USE SIGNAL ;
    PORT
      LAYER M4 ;
        RECT  64.716 56.016 64.8 56.04 ;
    END
  END di0[464]
  PIN di0[465]
    DIRECTION INPUT ;
    USE SIGNAL ;
    PORT
      LAYER M4 ;
        RECT  64.716 56.112 64.8 56.136 ;
    END
  END di0[465]
  PIN di0[466]
    DIRECTION INPUT ;
    USE SIGNAL ;
    PORT
      LAYER M4 ;
        RECT  64.716 56.208 64.8 56.232 ;
    END
  END di0[466]
  PIN di0[467]
    DIRECTION INPUT ;
    USE SIGNAL ;
    PORT
      LAYER M4 ;
        RECT  64.716 56.304 64.8 56.328 ;
    END
  END di0[467]
  PIN di0[468]
    DIRECTION INPUT ;
    USE SIGNAL ;
    PORT
      LAYER M4 ;
        RECT  64.716 56.4 64.8 56.424 ;
    END
  END di0[468]
  PIN di0[469]
    DIRECTION INPUT ;
    USE SIGNAL ;
    PORT
      LAYER M4 ;
        RECT  64.716 56.496 64.8 56.52 ;
    END
  END di0[469]
  PIN di0[46]
    DIRECTION INPUT ;
    USE SIGNAL ;
    PORT
      LAYER M4 ;
        RECT  64.716 59.664 64.8 59.688 ;
    END
  END di0[46]
  PIN di0[470]
    DIRECTION INPUT ;
    USE SIGNAL ;
    PORT
      LAYER M4 ;
        RECT  64.716 56.592 64.8 56.616 ;
    END
  END di0[470]
  PIN di0[471]
    DIRECTION INPUT ;
    USE SIGNAL ;
    PORT
      LAYER M4 ;
        RECT  64.716 56.688 64.8 56.712 ;
    END
  END di0[471]
  PIN di0[472]
    DIRECTION INPUT ;
    USE SIGNAL ;
    PORT
      LAYER M4 ;
        RECT  64.716 56.784 64.8 56.808 ;
    END
  END di0[472]
  PIN di0[473]
    DIRECTION INPUT ;
    USE SIGNAL ;
    PORT
      LAYER M4 ;
        RECT  64.716 56.88 64.8 56.904 ;
    END
  END di0[473]
  PIN di0[474]
    DIRECTION INPUT ;
    USE SIGNAL ;
    PORT
      LAYER M4 ;
        RECT  64.716 56.976 64.8 57 ;
    END
  END di0[474]
  PIN di0[475]
    DIRECTION INPUT ;
    USE SIGNAL ;
    PORT
      LAYER M4 ;
        RECT  64.716 57.072 64.8 57.096 ;
    END
  END di0[475]
  PIN di0[476]
    DIRECTION INPUT ;
    USE SIGNAL ;
    PORT
      LAYER M4 ;
        RECT  64.716 57.168 64.8 57.192 ;
    END
  END di0[476]
  PIN di0[477]
    DIRECTION INPUT ;
    USE SIGNAL ;
    PORT
      LAYER M4 ;
        RECT  64.716 57.264 64.8 57.288 ;
    END
  END di0[477]
  PIN di0[478]
    DIRECTION INPUT ;
    USE SIGNAL ;
    PORT
      LAYER M4 ;
        RECT  64.716 57.36 64.8 57.384 ;
    END
  END di0[478]
  PIN di0[479]
    DIRECTION INPUT ;
    USE SIGNAL ;
    PORT
      LAYER M4 ;
        RECT  64.716 57.456 64.8 57.48 ;
    END
  END di0[479]
  PIN di0[47]
    DIRECTION INPUT ;
    USE SIGNAL ;
    PORT
      LAYER M4 ;
        RECT  64.716 59.76 64.8 59.784 ;
    END
  END di0[47]
  PIN di0[480]
    DIRECTION INPUT ;
    USE SIGNAL ;
    PORT
      LAYER M4 ;
        RECT  64.716 48.336 64.8 48.36 ;
    END
  END di0[480]
  PIN di0[481]
    DIRECTION INPUT ;
    USE SIGNAL ;
    PORT
      LAYER M4 ;
        RECT  64.716 48.432 64.8 48.456 ;
    END
  END di0[481]
  PIN di0[482]
    DIRECTION INPUT ;
    USE SIGNAL ;
    PORT
      LAYER M4 ;
        RECT  64.716 48.528 64.8 48.552 ;
    END
  END di0[482]
  PIN di0[483]
    DIRECTION INPUT ;
    USE SIGNAL ;
    PORT
      LAYER M4 ;
        RECT  64.716 48.624 64.8 48.648 ;
    END
  END di0[483]
  PIN di0[484]
    DIRECTION INPUT ;
    USE SIGNAL ;
    PORT
      LAYER M4 ;
        RECT  64.716 48.72 64.8 48.744 ;
    END
  END di0[484]
  PIN di0[485]
    DIRECTION INPUT ;
    USE SIGNAL ;
    PORT
      LAYER M4 ;
        RECT  64.716 48.816 64.8 48.84 ;
    END
  END di0[485]
  PIN di0[486]
    DIRECTION INPUT ;
    USE SIGNAL ;
    PORT
      LAYER M4 ;
        RECT  64.716 48.912 64.8 48.936 ;
    END
  END di0[486]
  PIN di0[487]
    DIRECTION INPUT ;
    USE SIGNAL ;
    PORT
      LAYER M4 ;
        RECT  64.716 49.008 64.8 49.032 ;
    END
  END di0[487]
  PIN di0[488]
    DIRECTION INPUT ;
    USE SIGNAL ;
    PORT
      LAYER M4 ;
        RECT  64.716 49.104 64.8 49.128 ;
    END
  END di0[488]
  PIN di0[489]
    DIRECTION INPUT ;
    USE SIGNAL ;
    PORT
      LAYER M4 ;
        RECT  64.716 49.2 64.8 49.224 ;
    END
  END di0[489]
  PIN di0[48]
    DIRECTION INPUT ;
    USE SIGNAL ;
    PORT
      LAYER M4 ;
        RECT  64.716 59.856 64.8 59.88 ;
    END
  END di0[48]
  PIN di0[490]
    DIRECTION INPUT ;
    USE SIGNAL ;
    PORT
      LAYER M4 ;
        RECT  64.716 49.296 64.8 49.32 ;
    END
  END di0[490]
  PIN di0[491]
    DIRECTION INPUT ;
    USE SIGNAL ;
    PORT
      LAYER M4 ;
        RECT  64.716 49.392 64.8 49.416 ;
    END
  END di0[491]
  PIN di0[492]
    DIRECTION INPUT ;
    USE SIGNAL ;
    PORT
      LAYER M4 ;
        RECT  64.716 49.488 64.8 49.512 ;
    END
  END di0[492]
  PIN di0[493]
    DIRECTION INPUT ;
    USE SIGNAL ;
    PORT
      LAYER M4 ;
        RECT  64.716 49.584 64.8 49.608 ;
    END
  END di0[493]
  PIN di0[494]
    DIRECTION INPUT ;
    USE SIGNAL ;
    PORT
      LAYER M4 ;
        RECT  64.716 49.68 64.8 49.704 ;
    END
  END di0[494]
  PIN di0[495]
    DIRECTION INPUT ;
    USE SIGNAL ;
    PORT
      LAYER M4 ;
        RECT  64.716 49.776 64.8 49.8 ;
    END
  END di0[495]
  PIN di0[496]
    DIRECTION INPUT ;
    USE SIGNAL ;
    PORT
      LAYER M4 ;
        RECT  64.716 49.872 64.8 49.896 ;
    END
  END di0[496]
  PIN di0[497]
    DIRECTION INPUT ;
    USE SIGNAL ;
    PORT
      LAYER M4 ;
        RECT  64.716 49.968 64.8 49.992 ;
    END
  END di0[497]
  PIN di0[498]
    DIRECTION INPUT ;
    USE SIGNAL ;
    PORT
      LAYER M4 ;
        RECT  64.716 50.064 64.8 50.088 ;
    END
  END di0[498]
  PIN di0[499]
    DIRECTION INPUT ;
    USE SIGNAL ;
    PORT
      LAYER M4 ;
        RECT  64.716 50.16 64.8 50.184 ;
    END
  END di0[499]
  PIN di0[49]
    DIRECTION INPUT ;
    USE SIGNAL ;
    PORT
      LAYER M4 ;
        RECT  64.716 59.952 64.8 59.976 ;
    END
  END di0[49]
  PIN di0[4]
    DIRECTION INPUT ;
    USE SIGNAL ;
    PORT
      LAYER M4 ;
        RECT  64.716 39.504 64.8 39.528 ;
    END
  END di0[4]
  PIN di0[500]
    DIRECTION INPUT ;
    USE SIGNAL ;
    PORT
      LAYER M4 ;
        RECT  64.716 50.256 64.8 50.28 ;
    END
  END di0[500]
  PIN di0[501]
    DIRECTION INPUT ;
    USE SIGNAL ;
    PORT
      LAYER M4 ;
        RECT  64.716 50.352 64.8 50.376 ;
    END
  END di0[501]
  PIN di0[502]
    DIRECTION INPUT ;
    USE SIGNAL ;
    PORT
      LAYER M4 ;
        RECT  64.716 50.448 64.8 50.472 ;
    END
  END di0[502]
  PIN di0[503]
    DIRECTION INPUT ;
    USE SIGNAL ;
    PORT
      LAYER M4 ;
        RECT  64.716 50.544 64.8 50.568 ;
    END
  END di0[503]
  PIN di0[504]
    DIRECTION INPUT ;
    USE SIGNAL ;
    PORT
      LAYER M4 ;
        RECT  64.716 50.64 64.8 50.664 ;
    END
  END di0[504]
  PIN di0[505]
    DIRECTION INPUT ;
    USE SIGNAL ;
    PORT
      LAYER M4 ;
        RECT  64.716 50.736 64.8 50.76 ;
    END
  END di0[505]
  PIN di0[506]
    DIRECTION INPUT ;
    USE SIGNAL ;
    PORT
      LAYER M4 ;
        RECT  64.716 50.832 64.8 50.856 ;
    END
  END di0[506]
  PIN di0[507]
    DIRECTION INPUT ;
    USE SIGNAL ;
    PORT
      LAYER M4 ;
        RECT  64.716 50.928 64.8 50.952 ;
    END
  END di0[507]
  PIN di0[508]
    DIRECTION INPUT ;
    USE SIGNAL ;
    PORT
      LAYER M4 ;
        RECT  64.716 51.024 64.8 51.048 ;
    END
  END di0[508]
  PIN di0[509]
    DIRECTION INPUT ;
    USE SIGNAL ;
    PORT
      LAYER M4 ;
        RECT  64.716 51.12 64.8 51.144 ;
    END
  END di0[509]
  PIN di0[50]
    DIRECTION INPUT ;
    USE SIGNAL ;
    PORT
      LAYER M4 ;
        RECT  64.716 60.048 64.8 60.072 ;
    END
  END di0[50]
  PIN di0[510]
    DIRECTION INPUT ;
    USE SIGNAL ;
    PORT
      LAYER M4 ;
        RECT  64.716 51.216 64.8 51.24 ;
    END
  END di0[510]
  PIN di0[511]
    DIRECTION INPUT ;
    USE SIGNAL ;
    PORT
      LAYER M4 ;
        RECT  64.716 51.312 64.8 51.336 ;
    END
  END di0[511]
  PIN di0[512]
    DIRECTION INPUT ;
    USE SIGNAL ;
    PORT
      LAYER M4 ;
        RECT  64.716 42.192 64.8 42.216 ;
    END
  END di0[512]
  PIN di0[513]
    DIRECTION INPUT ;
    USE SIGNAL ;
    PORT
      LAYER M4 ;
        RECT  64.716 42.288 64.8 42.312 ;
    END
  END di0[513]
  PIN di0[51]
    DIRECTION INPUT ;
    USE SIGNAL ;
    PORT
      LAYER M4 ;
        RECT  64.716 60.144 64.8 60.168 ;
    END
  END di0[51]
  PIN di0[52]
    DIRECTION INPUT ;
    USE SIGNAL ;
    PORT
      LAYER M4 ;
        RECT  64.716 60.24 64.8 60.264 ;
    END
  END di0[52]
  PIN di0[53]
    DIRECTION INPUT ;
    USE SIGNAL ;
    PORT
      LAYER M4 ;
        RECT  64.716 60.336 64.8 60.36 ;
    END
  END di0[53]
  PIN di0[54]
    DIRECTION INPUT ;
    USE SIGNAL ;
    PORT
      LAYER M4 ;
        RECT  64.716 60.432 64.8 60.456 ;
    END
  END di0[54]
  PIN di0[55]
    DIRECTION INPUT ;
    USE SIGNAL ;
    PORT
      LAYER M4 ;
        RECT  64.716 60.528 64.8 60.552 ;
    END
  END di0[55]
  PIN di0[56]
    DIRECTION INPUT ;
    USE SIGNAL ;
    PORT
      LAYER M4 ;
        RECT  64.716 60.624 64.8 60.648 ;
    END
  END di0[56]
  PIN di0[57]
    DIRECTION INPUT ;
    USE SIGNAL ;
    PORT
      LAYER M4 ;
        RECT  64.716 60.72 64.8 60.744 ;
    END
  END di0[57]
  PIN di0[58]
    DIRECTION INPUT ;
    USE SIGNAL ;
    PORT
      LAYER M4 ;
        RECT  64.716 60.816 64.8 60.84 ;
    END
  END di0[58]
  PIN di0[59]
    DIRECTION INPUT ;
    USE SIGNAL ;
    PORT
      LAYER M4 ;
        RECT  64.716 60.912 64.8 60.936 ;
    END
  END di0[59]
  PIN di0[5]
    DIRECTION INPUT ;
    USE SIGNAL ;
    PORT
      LAYER M4 ;
        RECT  64.716 39.6 64.8 39.624 ;
    END
  END di0[5]
  PIN di0[60]
    DIRECTION INPUT ;
    USE SIGNAL ;
    PORT
      LAYER M4 ;
        RECT  64.716 61.008 64.8 61.032 ;
    END
  END di0[60]
  PIN di0[61]
    DIRECTION INPUT ;
    USE SIGNAL ;
    PORT
      LAYER M4 ;
        RECT  64.716 61.104 64.8 61.128 ;
    END
  END di0[61]
  PIN di0[62]
    DIRECTION INPUT ;
    USE SIGNAL ;
    PORT
      LAYER M4 ;
        RECT  64.716 61.2 64.8 61.224 ;
    END
  END di0[62]
  PIN di0[63]
    DIRECTION INPUT ;
    USE SIGNAL ;
    PORT
      LAYER M4 ;
        RECT  64.716 61.296 64.8 61.32 ;
    END
  END di0[63]
  PIN di0[64]
    DIRECTION INPUT ;
    USE SIGNAL ;
    PORT
      LAYER M4 ;
        RECT  64.716 51.408 64.8 51.432 ;
    END
  END di0[64]
  PIN di0[65]
    DIRECTION INPUT ;
    USE SIGNAL ;
    PORT
      LAYER M4 ;
        RECT  64.716 51.504 64.8 51.528 ;
    END
  END di0[65]
  PIN di0[66]
    DIRECTION INPUT ;
    USE SIGNAL ;
    PORT
      LAYER M4 ;
        RECT  64.716 51.6 64.8 51.624 ;
    END
  END di0[66]
  PIN di0[67]
    DIRECTION INPUT ;
    USE SIGNAL ;
    PORT
      LAYER M4 ;
        RECT  64.716 51.696 64.8 51.72 ;
    END
  END di0[67]
  PIN di0[68]
    DIRECTION INPUT ;
    USE SIGNAL ;
    PORT
      LAYER M4 ;
        RECT  64.716 51.792 64.8 51.816 ;
    END
  END di0[68]
  PIN di0[69]
    DIRECTION INPUT ;
    USE SIGNAL ;
    PORT
      LAYER M4 ;
        RECT  64.716 51.888 64.8 51.912 ;
    END
  END di0[69]
  PIN di0[6]
    DIRECTION INPUT ;
    USE SIGNAL ;
    PORT
      LAYER M4 ;
        RECT  64.716 39.696 64.8 39.72 ;
    END
  END di0[6]
  PIN di0[70]
    DIRECTION INPUT ;
    USE SIGNAL ;
    PORT
      LAYER M4 ;
        RECT  64.716 51.984 64.8 52.008 ;
    END
  END di0[70]
  PIN di0[71]
    DIRECTION INPUT ;
    USE SIGNAL ;
    PORT
      LAYER M4 ;
        RECT  64.716 52.08 64.8 52.104 ;
    END
  END di0[71]
  PIN di0[72]
    DIRECTION INPUT ;
    USE SIGNAL ;
    PORT
      LAYER M4 ;
        RECT  64.716 52.176 64.8 52.2 ;
    END
  END di0[72]
  PIN di0[73]
    DIRECTION INPUT ;
    USE SIGNAL ;
    PORT
      LAYER M4 ;
        RECT  64.716 52.272 64.8 52.296 ;
    END
  END di0[73]
  PIN di0[74]
    DIRECTION INPUT ;
    USE SIGNAL ;
    PORT
      LAYER M4 ;
        RECT  64.716 52.368 64.8 52.392 ;
    END
  END di0[74]
  PIN di0[75]
    DIRECTION INPUT ;
    USE SIGNAL ;
    PORT
      LAYER M4 ;
        RECT  64.716 52.464 64.8 52.488 ;
    END
  END di0[75]
  PIN di0[76]
    DIRECTION INPUT ;
    USE SIGNAL ;
    PORT
      LAYER M4 ;
        RECT  64.716 52.56 64.8 52.584 ;
    END
  END di0[76]
  PIN di0[77]
    DIRECTION INPUT ;
    USE SIGNAL ;
    PORT
      LAYER M4 ;
        RECT  64.716 52.656 64.8 52.68 ;
    END
  END di0[77]
  PIN di0[78]
    DIRECTION INPUT ;
    USE SIGNAL ;
    PORT
      LAYER M4 ;
        RECT  64.716 52.752 64.8 52.776 ;
    END
  END di0[78]
  PIN di0[79]
    DIRECTION INPUT ;
    USE SIGNAL ;
    PORT
      LAYER M4 ;
        RECT  64.716 52.848 64.8 52.872 ;
    END
  END di0[79]
  PIN di0[7]
    DIRECTION INPUT ;
    USE SIGNAL ;
    PORT
      LAYER M4 ;
        RECT  64.716 39.792 64.8 39.816 ;
    END
  END di0[7]
  PIN di0[80]
    DIRECTION INPUT ;
    USE SIGNAL ;
    PORT
      LAYER M4 ;
        RECT  64.716 52.944 64.8 52.968 ;
    END
  END di0[80]
  PIN di0[81]
    DIRECTION INPUT ;
    USE SIGNAL ;
    PORT
      LAYER M4 ;
        RECT  64.716 53.04 64.8 53.064 ;
    END
  END di0[81]
  PIN di0[82]
    DIRECTION INPUT ;
    USE SIGNAL ;
    PORT
      LAYER M4 ;
        RECT  64.716 53.136 64.8 53.16 ;
    END
  END di0[82]
  PIN di0[83]
    DIRECTION INPUT ;
    USE SIGNAL ;
    PORT
      LAYER M4 ;
        RECT  64.716 53.232 64.8 53.256 ;
    END
  END di0[83]
  PIN di0[84]
    DIRECTION INPUT ;
    USE SIGNAL ;
    PORT
      LAYER M4 ;
        RECT  64.716 53.328 64.8 53.352 ;
    END
  END di0[84]
  PIN di0[85]
    DIRECTION INPUT ;
    USE SIGNAL ;
    PORT
      LAYER M4 ;
        RECT  64.716 53.424 64.8 53.448 ;
    END
  END di0[85]
  PIN di0[86]
    DIRECTION INPUT ;
    USE SIGNAL ;
    PORT
      LAYER M4 ;
        RECT  64.716 53.52 64.8 53.544 ;
    END
  END di0[86]
  PIN di0[87]
    DIRECTION INPUT ;
    USE SIGNAL ;
    PORT
      LAYER M4 ;
        RECT  64.716 53.616 64.8 53.64 ;
    END
  END di0[87]
  PIN di0[88]
    DIRECTION INPUT ;
    USE SIGNAL ;
    PORT
      LAYER M4 ;
        RECT  64.716 53.712 64.8 53.736 ;
    END
  END di0[88]
  PIN di0[89]
    DIRECTION INPUT ;
    USE SIGNAL ;
    PORT
      LAYER M4 ;
        RECT  64.716 53.808 64.8 53.832 ;
    END
  END di0[89]
  PIN di0[8]
    DIRECTION INPUT ;
    USE SIGNAL ;
    PORT
      LAYER M4 ;
        RECT  64.716 39.888 64.8 39.912 ;
    END
  END di0[8]
  PIN di0[90]
    DIRECTION INPUT ;
    USE SIGNAL ;
    PORT
      LAYER M4 ;
        RECT  64.716 53.904 64.8 53.928 ;
    END
  END di0[90]
  PIN di0[91]
    DIRECTION INPUT ;
    USE SIGNAL ;
    PORT
      LAYER M4 ;
        RECT  64.716 54 64.8 54.024 ;
    END
  END di0[91]
  PIN di0[92]
    DIRECTION INPUT ;
    USE SIGNAL ;
    PORT
      LAYER M4 ;
        RECT  64.716 54.096 64.8 54.12 ;
    END
  END di0[92]
  PIN di0[93]
    DIRECTION INPUT ;
    USE SIGNAL ;
    PORT
      LAYER M4 ;
        RECT  64.716 54.192 64.8 54.216 ;
    END
  END di0[93]
  PIN di0[94]
    DIRECTION INPUT ;
    USE SIGNAL ;
    PORT
      LAYER M4 ;
        RECT  64.716 54.288 64.8 54.312 ;
    END
  END di0[94]
  PIN di0[95]
    DIRECTION INPUT ;
    USE SIGNAL ;
    PORT
      LAYER M4 ;
        RECT  64.716 54.384 64.8 54.408 ;
    END
  END di0[95]
  PIN di0[96]
    DIRECTION INPUT ;
    USE SIGNAL ;
    PORT
      LAYER M4 ;
        RECT  64.716 45.264 64.8 45.288 ;
    END
  END di0[96]
  PIN di0[97]
    DIRECTION INPUT ;
    USE SIGNAL ;
    PORT
      LAYER M4 ;
        RECT  64.716 45.36 64.8 45.384 ;
    END
  END di0[97]
  PIN di0[98]
    DIRECTION INPUT ;
    USE SIGNAL ;
    PORT
      LAYER M4 ;
        RECT  64.716 45.456 64.8 45.48 ;
    END
  END di0[98]
  PIN di0[99]
    DIRECTION INPUT ;
    USE SIGNAL ;
    PORT
      LAYER M4 ;
        RECT  64.716 45.552 64.8 45.576 ;
    END
  END di0[99]
  PIN di0[9]
    DIRECTION INPUT ;
    USE SIGNAL ;
    PORT
      LAYER M4 ;
        RECT  64.716 39.984 64.8 40.008 ;
    END
  END di0[9]
  PIN fi0[0]
    DIRECTION INPUT ;
    USE SIGNAL ;
    PORT
      LAYER M4 ;
        RECT  64.716 42.384 64.8 42.408 ;
    END
  END fi0[0]
  PIN o[0]
    DIRECTION OUTPUT ;
    USE SIGNAL ;
    PORT
      LAYER M5 ;
        RECT  26.448 64.716 26.472 64.8 ;
    END
  END o[0]
  PIN o[100]
    DIRECTION OUTPUT ;
    USE SIGNAL ;
    PORT
      LAYER M5 ;
        RECT  58.32 64.716 58.344 64.8 ;
    END
  END o[100]
  PIN o[101]
    DIRECTION OUTPUT ;
    USE SIGNAL ;
    PORT
      LAYER M5 ;
        RECT  58.416 64.716 58.44 64.8 ;
    END
  END o[101]
  PIN o[102]
    DIRECTION OUTPUT ;
    USE SIGNAL ;
    PORT
      LAYER M5 ;
        RECT  58.512 64.716 58.536 64.8 ;
    END
  END o[102]
  PIN o[103]
    DIRECTION OUTPUT ;
    USE SIGNAL ;
    PORT
      LAYER M5 ;
        RECT  58.608 64.716 58.632 64.8 ;
    END
  END o[103]
  PIN o[104]
    DIRECTION OUTPUT ;
    USE SIGNAL ;
    PORT
      LAYER M5 ;
        RECT  58.704 64.716 58.728 64.8 ;
    END
  END o[104]
  PIN o[105]
    DIRECTION OUTPUT ;
    USE SIGNAL ;
    PORT
      LAYER M5 ;
        RECT  58.8 64.716 58.824 64.8 ;
    END
  END o[105]
  PIN o[106]
    DIRECTION OUTPUT ;
    USE SIGNAL ;
    PORT
      LAYER M5 ;
        RECT  58.896 64.716 58.92 64.8 ;
    END
  END o[106]
  PIN o[107]
    DIRECTION OUTPUT ;
    USE SIGNAL ;
    PORT
      LAYER M5 ;
        RECT  58.992 64.716 59.016 64.8 ;
    END
  END o[107]
  PIN o[108]
    DIRECTION OUTPUT ;
    USE SIGNAL ;
    PORT
      LAYER M5 ;
        RECT  59.088 64.716 59.112 64.8 ;
    END
  END o[108]
  PIN o[109]
    DIRECTION OUTPUT ;
    USE SIGNAL ;
    PORT
      LAYER M5 ;
        RECT  59.184 64.716 59.208 64.8 ;
    END
  END o[109]
  PIN o[10]
    DIRECTION OUTPUT ;
    USE SIGNAL ;
    PORT
      LAYER M5 ;
        RECT  27.408 64.716 27.432 64.8 ;
    END
  END o[10]
  PIN o[110]
    DIRECTION OUTPUT ;
    USE SIGNAL ;
    PORT
      LAYER M5 ;
        RECT  59.28 64.716 59.304 64.8 ;
    END
  END o[110]
  PIN o[111]
    DIRECTION OUTPUT ;
    USE SIGNAL ;
    PORT
      LAYER M5 ;
        RECT  59.376 64.716 59.4 64.8 ;
    END
  END o[111]
  PIN o[112]
    DIRECTION OUTPUT ;
    USE SIGNAL ;
    PORT
      LAYER M5 ;
        RECT  59.472 64.716 59.496 64.8 ;
    END
  END o[112]
  PIN o[113]
    DIRECTION OUTPUT ;
    USE SIGNAL ;
    PORT
      LAYER M5 ;
        RECT  59.568 64.716 59.592 64.8 ;
    END
  END o[113]
  PIN o[114]
    DIRECTION OUTPUT ;
    USE SIGNAL ;
    PORT
      LAYER M5 ;
        RECT  59.664 64.716 59.688 64.8 ;
    END
  END o[114]
  PIN o[115]
    DIRECTION OUTPUT ;
    USE SIGNAL ;
    PORT
      LAYER M5 ;
        RECT  59.76 64.716 59.784 64.8 ;
    END
  END o[115]
  PIN o[116]
    DIRECTION OUTPUT ;
    USE SIGNAL ;
    PORT
      LAYER M5 ;
        RECT  59.856 64.716 59.88 64.8 ;
    END
  END o[116]
  PIN o[117]
    DIRECTION OUTPUT ;
    USE SIGNAL ;
    PORT
      LAYER M5 ;
        RECT  59.952 64.716 59.976 64.8 ;
    END
  END o[117]
  PIN o[118]
    DIRECTION OUTPUT ;
    USE SIGNAL ;
    PORT
      LAYER M5 ;
        RECT  60.048 64.716 60.072 64.8 ;
    END
  END o[118]
  PIN o[119]
    DIRECTION OUTPUT ;
    USE SIGNAL ;
    PORT
      LAYER M5 ;
        RECT  60.144 64.716 60.168 64.8 ;
    END
  END o[119]
  PIN o[11]
    DIRECTION OUTPUT ;
    USE SIGNAL ;
    PORT
      LAYER M5 ;
        RECT  27.504 64.716 27.528 64.8 ;
    END
  END o[11]
  PIN o[120]
    DIRECTION OUTPUT ;
    USE SIGNAL ;
    PORT
      LAYER M5 ;
        RECT  60.24 64.716 60.264 64.8 ;
    END
  END o[120]
  PIN o[121]
    DIRECTION OUTPUT ;
    USE SIGNAL ;
    PORT
      LAYER M5 ;
        RECT  60.336 64.716 60.36 64.8 ;
    END
  END o[121]
  PIN o[122]
    DIRECTION OUTPUT ;
    USE SIGNAL ;
    PORT
      LAYER M5 ;
        RECT  60.432 64.716 60.456 64.8 ;
    END
  END o[122]
  PIN o[123]
    DIRECTION OUTPUT ;
    USE SIGNAL ;
    PORT
      LAYER M5 ;
        RECT  60.528 64.716 60.552 64.8 ;
    END
  END o[123]
  PIN o[124]
    DIRECTION OUTPUT ;
    USE SIGNAL ;
    PORT
      LAYER M5 ;
        RECT  60.624 64.716 60.648 64.8 ;
    END
  END o[124]
  PIN o[125]
    DIRECTION OUTPUT ;
    USE SIGNAL ;
    PORT
      LAYER M5 ;
        RECT  60.72 64.716 60.744 64.8 ;
    END
  END o[125]
  PIN o[126]
    DIRECTION OUTPUT ;
    USE SIGNAL ;
    PORT
      LAYER M5 ;
        RECT  60.816 64.716 60.84 64.8 ;
    END
  END o[126]
  PIN o[127]
    DIRECTION OUTPUT ;
    USE SIGNAL ;
    PORT
      LAYER M5 ;
        RECT  60.912 64.716 60.936 64.8 ;
    END
  END o[127]
  PIN o[128]
    DIRECTION OUTPUT ;
    USE SIGNAL ;
    PORT
      LAYER M5 ;
        RECT  61.008 64.716 61.032 64.8 ;
    END
  END o[128]
  PIN o[129]
    DIRECTION OUTPUT ;
    USE SIGNAL ;
    PORT
      LAYER M5 ;
        RECT  61.104 64.716 61.128 64.8 ;
    END
  END o[129]
  PIN o[12]
    DIRECTION OUTPUT ;
    USE SIGNAL ;
    PORT
      LAYER M5 ;
        RECT  27.6 64.716 27.624 64.8 ;
    END
  END o[12]
  PIN o[130]
    DIRECTION OUTPUT ;
    USE SIGNAL ;
    PORT
      LAYER M5 ;
        RECT  61.2 64.716 61.224 64.8 ;
    END
  END o[130]
  PIN o[131]
    DIRECTION OUTPUT ;
    USE SIGNAL ;
    PORT
      LAYER M5 ;
        RECT  61.296 64.716 61.32 64.8 ;
    END
  END o[131]
  PIN o[132]
    DIRECTION OUTPUT ;
    USE SIGNAL ;
    PORT
      LAYER M5 ;
        RECT  61.392 64.716 61.416 64.8 ;
    END
  END o[132]
  PIN o[133]
    DIRECTION OUTPUT ;
    USE SIGNAL ;
    PORT
      LAYER M5 ;
        RECT  61.488 64.716 61.512 64.8 ;
    END
  END o[133]
  PIN o[134]
    DIRECTION OUTPUT ;
    USE SIGNAL ;
    PORT
      LAYER M5 ;
        RECT  61.584 64.716 61.608 64.8 ;
    END
  END o[134]
  PIN o[135]
    DIRECTION OUTPUT ;
    USE SIGNAL ;
    PORT
      LAYER M5 ;
        RECT  61.68 64.716 61.704 64.8 ;
    END
  END o[135]
  PIN o[136]
    DIRECTION OUTPUT ;
    USE SIGNAL ;
    PORT
      LAYER M5 ;
        RECT  61.776 64.716 61.8 64.8 ;
    END
  END o[136]
  PIN o[137]
    DIRECTION OUTPUT ;
    USE SIGNAL ;
    PORT
      LAYER M5 ;
        RECT  61.872 64.716 61.896 64.8 ;
    END
  END o[137]
  PIN o[138]
    DIRECTION OUTPUT ;
    USE SIGNAL ;
    PORT
      LAYER M5 ;
        RECT  61.968 64.716 61.992 64.8 ;
    END
  END o[138]
  PIN o[139]
    DIRECTION OUTPUT ;
    USE SIGNAL ;
    PORT
      LAYER M5 ;
        RECT  62.064 64.716 62.088 64.8 ;
    END
  END o[139]
  PIN o[13]
    DIRECTION OUTPUT ;
    USE SIGNAL ;
    PORT
      LAYER M5 ;
        RECT  27.696 64.716 27.72 64.8 ;
    END
  END o[13]
  PIN o[140]
    DIRECTION OUTPUT ;
    USE SIGNAL ;
    PORT
      LAYER M5 ;
        RECT  62.16 64.716 62.184 64.8 ;
    END
  END o[140]
  PIN o[141]
    DIRECTION OUTPUT ;
    USE SIGNAL ;
    PORT
      LAYER M5 ;
        RECT  62.256 64.716 62.28 64.8 ;
    END
  END o[141]
  PIN o[142]
    DIRECTION OUTPUT ;
    USE SIGNAL ;
    PORT
      LAYER M5 ;
        RECT  62.352 64.716 62.376 64.8 ;
    END
  END o[142]
  PIN o[143]
    DIRECTION OUTPUT ;
    USE SIGNAL ;
    PORT
      LAYER M5 ;
        RECT  62.448 64.716 62.472 64.8 ;
    END
  END o[143]
  PIN o[144]
    DIRECTION OUTPUT ;
    USE SIGNAL ;
    PORT
      LAYER M5 ;
        RECT  62.544 64.716 62.568 64.8 ;
    END
  END o[144]
  PIN o[145]
    DIRECTION OUTPUT ;
    USE SIGNAL ;
    PORT
      LAYER M5 ;
        RECT  62.64 64.716 62.664 64.8 ;
    END
  END o[145]
  PIN o[146]
    DIRECTION OUTPUT ;
    USE SIGNAL ;
    PORT
      LAYER M5 ;
        RECT  62.736 64.716 62.76 64.8 ;
    END
  END o[146]
  PIN o[147]
    DIRECTION OUTPUT ;
    USE SIGNAL ;
    PORT
      LAYER M5 ;
        RECT  62.832 64.716 62.856 64.8 ;
    END
  END o[147]
  PIN o[148]
    DIRECTION OUTPUT ;
    USE SIGNAL ;
    PORT
      LAYER M5 ;
        RECT  62.928 64.716 62.952 64.8 ;
    END
  END o[148]
  PIN o[149]
    DIRECTION OUTPUT ;
    USE SIGNAL ;
    PORT
      LAYER M5 ;
        RECT  63.024 64.716 63.048 64.8 ;
    END
  END o[149]
  PIN o[14]
    DIRECTION OUTPUT ;
    USE SIGNAL ;
    PORT
      LAYER M5 ;
        RECT  27.792 64.716 27.816 64.8 ;
    END
  END o[14]
  PIN o[150]
    DIRECTION OUTPUT ;
    USE SIGNAL ;
    PORT
      LAYER M5 ;
        RECT  63.12 64.716 63.144 64.8 ;
    END
  END o[150]
  PIN o[151]
    DIRECTION OUTPUT ;
    USE SIGNAL ;
    PORT
      LAYER M5 ;
        RECT  63.216 64.716 63.24 64.8 ;
    END
  END o[151]
  PIN o[152]
    DIRECTION OUTPUT ;
    USE SIGNAL ;
    PORT
      LAYER M5 ;
        RECT  63.312 64.716 63.336 64.8 ;
    END
  END o[152]
  PIN o[153]
    DIRECTION OUTPUT ;
    USE SIGNAL ;
    PORT
      LAYER M5 ;
        RECT  63.408 64.716 63.432 64.8 ;
    END
  END o[153]
  PIN o[154]
    DIRECTION OUTPUT ;
    USE SIGNAL ;
    PORT
      LAYER M5 ;
        RECT  63.504 64.716 63.528 64.8 ;
    END
  END o[154]
  PIN o[155]
    DIRECTION OUTPUT ;
    USE SIGNAL ;
    PORT
      LAYER M5 ;
        RECT  63.6 64.716 63.624 64.8 ;
    END
  END o[155]
  PIN o[156]
    DIRECTION OUTPUT ;
    USE SIGNAL ;
    PORT
      LAYER M5 ;
        RECT  63.696 64.716 63.72 64.8 ;
    END
  END o[156]
  PIN o[157]
    DIRECTION OUTPUT ;
    USE SIGNAL ;
    PORT
      LAYER M5 ;
        RECT  63.792 64.716 63.816 64.8 ;
    END
  END o[157]
  PIN o[158]
    DIRECTION OUTPUT ;
    USE SIGNAL ;
    PORT
      LAYER M5 ;
        RECT  63.888 64.716 63.912 64.8 ;
    END
  END o[158]
  PIN o[159]
    DIRECTION OUTPUT ;
    USE SIGNAL ;
    PORT
      LAYER M5 ;
        RECT  63.984 64.716 64.008 64.8 ;
    END
  END o[159]
  PIN o[15]
    DIRECTION OUTPUT ;
    USE SIGNAL ;
    PORT
      LAYER M5 ;
        RECT  27.888 64.716 27.912 64.8 ;
    END
  END o[15]
  PIN o[160]
    DIRECTION OUTPUT ;
    USE SIGNAL ;
    PORT
      LAYER M5 ;
        RECT  48.72 64.716 48.744 64.8 ;
    END
  END o[160]
  PIN o[161]
    DIRECTION OUTPUT ;
    USE SIGNAL ;
    PORT
      LAYER M5 ;
        RECT  48.816 64.716 48.84 64.8 ;
    END
  END o[161]
  PIN o[162]
    DIRECTION OUTPUT ;
    USE SIGNAL ;
    PORT
      LAYER M5 ;
        RECT  48.912 64.716 48.936 64.8 ;
    END
  END o[162]
  PIN o[163]
    DIRECTION OUTPUT ;
    USE SIGNAL ;
    PORT
      LAYER M5 ;
        RECT  49.008 64.716 49.032 64.8 ;
    END
  END o[163]
  PIN o[164]
    DIRECTION OUTPUT ;
    USE SIGNAL ;
    PORT
      LAYER M5 ;
        RECT  49.104 64.716 49.128 64.8 ;
    END
  END o[164]
  PIN o[165]
    DIRECTION OUTPUT ;
    USE SIGNAL ;
    PORT
      LAYER M5 ;
        RECT  49.2 64.716 49.224 64.8 ;
    END
  END o[165]
  PIN o[166]
    DIRECTION OUTPUT ;
    USE SIGNAL ;
    PORT
      LAYER M5 ;
        RECT  49.296 64.716 49.32 64.8 ;
    END
  END o[166]
  PIN o[167]
    DIRECTION OUTPUT ;
    USE SIGNAL ;
    PORT
      LAYER M5 ;
        RECT  49.392 64.716 49.416 64.8 ;
    END
  END o[167]
  PIN o[168]
    DIRECTION OUTPUT ;
    USE SIGNAL ;
    PORT
      LAYER M5 ;
        RECT  49.488 64.716 49.512 64.8 ;
    END
  END o[168]
  PIN o[169]
    DIRECTION OUTPUT ;
    USE SIGNAL ;
    PORT
      LAYER M5 ;
        RECT  49.584 64.716 49.608 64.8 ;
    END
  END o[169]
  PIN o[16]
    DIRECTION OUTPUT ;
    USE SIGNAL ;
    PORT
      LAYER M5 ;
        RECT  27.984 64.716 28.008 64.8 ;
    END
  END o[16]
  PIN o[170]
    DIRECTION OUTPUT ;
    USE SIGNAL ;
    PORT
      LAYER M5 ;
        RECT  49.68 64.716 49.704 64.8 ;
    END
  END o[170]
  PIN o[171]
    DIRECTION OUTPUT ;
    USE SIGNAL ;
    PORT
      LAYER M5 ;
        RECT  49.776 64.716 49.8 64.8 ;
    END
  END o[171]
  PIN o[172]
    DIRECTION OUTPUT ;
    USE SIGNAL ;
    PORT
      LAYER M5 ;
        RECT  49.872 64.716 49.896 64.8 ;
    END
  END o[172]
  PIN o[173]
    DIRECTION OUTPUT ;
    USE SIGNAL ;
    PORT
      LAYER M5 ;
        RECT  49.968 64.716 49.992 64.8 ;
    END
  END o[173]
  PIN o[174]
    DIRECTION OUTPUT ;
    USE SIGNAL ;
    PORT
      LAYER M5 ;
        RECT  50.064 64.716 50.088 64.8 ;
    END
  END o[174]
  PIN o[175]
    DIRECTION OUTPUT ;
    USE SIGNAL ;
    PORT
      LAYER M5 ;
        RECT  50.16 64.716 50.184 64.8 ;
    END
  END o[175]
  PIN o[176]
    DIRECTION OUTPUT ;
    USE SIGNAL ;
    PORT
      LAYER M5 ;
        RECT  50.256 64.716 50.28 64.8 ;
    END
  END o[176]
  PIN o[177]
    DIRECTION OUTPUT ;
    USE SIGNAL ;
    PORT
      LAYER M5 ;
        RECT  50.352 64.716 50.376 64.8 ;
    END
  END o[177]
  PIN o[178]
    DIRECTION OUTPUT ;
    USE SIGNAL ;
    PORT
      LAYER M5 ;
        RECT  50.448 64.716 50.472 64.8 ;
    END
  END o[178]
  PIN o[179]
    DIRECTION OUTPUT ;
    USE SIGNAL ;
    PORT
      LAYER M5 ;
        RECT  50.544 64.716 50.568 64.8 ;
    END
  END o[179]
  PIN o[17]
    DIRECTION OUTPUT ;
    USE SIGNAL ;
    PORT
      LAYER M5 ;
        RECT  28.08 64.716 28.104 64.8 ;
    END
  END o[17]
  PIN o[180]
    DIRECTION OUTPUT ;
    USE SIGNAL ;
    PORT
      LAYER M5 ;
        RECT  50.64 64.716 50.664 64.8 ;
    END
  END o[180]
  PIN o[181]
    DIRECTION OUTPUT ;
    USE SIGNAL ;
    PORT
      LAYER M5 ;
        RECT  50.736 64.716 50.76 64.8 ;
    END
  END o[181]
  PIN o[182]
    DIRECTION OUTPUT ;
    USE SIGNAL ;
    PORT
      LAYER M5 ;
        RECT  50.832 64.716 50.856 64.8 ;
    END
  END o[182]
  PIN o[183]
    DIRECTION OUTPUT ;
    USE SIGNAL ;
    PORT
      LAYER M5 ;
        RECT  50.928 64.716 50.952 64.8 ;
    END
  END o[183]
  PIN o[184]
    DIRECTION OUTPUT ;
    USE SIGNAL ;
    PORT
      LAYER M5 ;
        RECT  51.024 64.716 51.048 64.8 ;
    END
  END o[184]
  PIN o[185]
    DIRECTION OUTPUT ;
    USE SIGNAL ;
    PORT
      LAYER M5 ;
        RECT  51.12 64.716 51.144 64.8 ;
    END
  END o[185]
  PIN o[186]
    DIRECTION OUTPUT ;
    USE SIGNAL ;
    PORT
      LAYER M5 ;
        RECT  51.216 64.716 51.24 64.8 ;
    END
  END o[186]
  PIN o[187]
    DIRECTION OUTPUT ;
    USE SIGNAL ;
    PORT
      LAYER M5 ;
        RECT  51.312 64.716 51.336 64.8 ;
    END
  END o[187]
  PIN o[188]
    DIRECTION OUTPUT ;
    USE SIGNAL ;
    PORT
      LAYER M5 ;
        RECT  51.408 64.716 51.432 64.8 ;
    END
  END o[188]
  PIN o[189]
    DIRECTION OUTPUT ;
    USE SIGNAL ;
    PORT
      LAYER M5 ;
        RECT  51.504 64.716 51.528 64.8 ;
    END
  END o[189]
  PIN o[18]
    DIRECTION OUTPUT ;
    USE SIGNAL ;
    PORT
      LAYER M5 ;
        RECT  28.176 64.716 28.2 64.8 ;
    END
  END o[18]
  PIN o[190]
    DIRECTION OUTPUT ;
    USE SIGNAL ;
    PORT
      LAYER M5 ;
        RECT  51.6 64.716 51.624 64.8 ;
    END
  END o[190]
  PIN o[191]
    DIRECTION OUTPUT ;
    USE SIGNAL ;
    PORT
      LAYER M5 ;
        RECT  51.696 64.716 51.72 64.8 ;
    END
  END o[191]
  PIN o[192]
    DIRECTION OUTPUT ;
    USE SIGNAL ;
    PORT
      LAYER M5 ;
        RECT  51.792 64.716 51.816 64.8 ;
    END
  END o[192]
  PIN o[193]
    DIRECTION OUTPUT ;
    USE SIGNAL ;
    PORT
      LAYER M5 ;
        RECT  51.888 64.716 51.912 64.8 ;
    END
  END o[193]
  PIN o[194]
    DIRECTION OUTPUT ;
    USE SIGNAL ;
    PORT
      LAYER M5 ;
        RECT  51.984 64.716 52.008 64.8 ;
    END
  END o[194]
  PIN o[195]
    DIRECTION OUTPUT ;
    USE SIGNAL ;
    PORT
      LAYER M5 ;
        RECT  52.08 64.716 52.104 64.8 ;
    END
  END o[195]
  PIN o[196]
    DIRECTION OUTPUT ;
    USE SIGNAL ;
    PORT
      LAYER M5 ;
        RECT  52.176 64.716 52.2 64.8 ;
    END
  END o[196]
  PIN o[197]
    DIRECTION OUTPUT ;
    USE SIGNAL ;
    PORT
      LAYER M5 ;
        RECT  52.272 64.716 52.296 64.8 ;
    END
  END o[197]
  PIN o[198]
    DIRECTION OUTPUT ;
    USE SIGNAL ;
    PORT
      LAYER M5 ;
        RECT  52.368 64.716 52.392 64.8 ;
    END
  END o[198]
  PIN o[199]
    DIRECTION OUTPUT ;
    USE SIGNAL ;
    PORT
      LAYER M5 ;
        RECT  52.464 64.716 52.488 64.8 ;
    END
  END o[199]
  PIN o[19]
    DIRECTION OUTPUT ;
    USE SIGNAL ;
    PORT
      LAYER M5 ;
        RECT  28.272 64.716 28.296 64.8 ;
    END
  END o[19]
  PIN o[1]
    DIRECTION OUTPUT ;
    USE SIGNAL ;
    PORT
      LAYER M5 ;
        RECT  26.544 64.716 26.568 64.8 ;
    END
  END o[1]
  PIN o[200]
    DIRECTION OUTPUT ;
    USE SIGNAL ;
    PORT
      LAYER M5 ;
        RECT  52.56 64.716 52.584 64.8 ;
    END
  END o[200]
  PIN o[201]
    DIRECTION OUTPUT ;
    USE SIGNAL ;
    PORT
      LAYER M5 ;
        RECT  52.656 64.716 52.68 64.8 ;
    END
  END o[201]
  PIN o[202]
    DIRECTION OUTPUT ;
    USE SIGNAL ;
    PORT
      LAYER M5 ;
        RECT  52.752 64.716 52.776 64.8 ;
    END
  END o[202]
  PIN o[203]
    DIRECTION OUTPUT ;
    USE SIGNAL ;
    PORT
      LAYER M5 ;
        RECT  52.848 64.716 52.872 64.8 ;
    END
  END o[203]
  PIN o[204]
    DIRECTION OUTPUT ;
    USE SIGNAL ;
    PORT
      LAYER M5 ;
        RECT  52.944 64.716 52.968 64.8 ;
    END
  END o[204]
  PIN o[205]
    DIRECTION OUTPUT ;
    USE SIGNAL ;
    PORT
      LAYER M5 ;
        RECT  53.04 64.716 53.064 64.8 ;
    END
  END o[205]
  PIN o[206]
    DIRECTION OUTPUT ;
    USE SIGNAL ;
    PORT
      LAYER M5 ;
        RECT  53.136 64.716 53.16 64.8 ;
    END
  END o[206]
  PIN o[207]
    DIRECTION OUTPUT ;
    USE SIGNAL ;
    PORT
      LAYER M5 ;
        RECT  53.232 64.716 53.256 64.8 ;
    END
  END o[207]
  PIN o[208]
    DIRECTION OUTPUT ;
    USE SIGNAL ;
    PORT
      LAYER M5 ;
        RECT  53.328 64.716 53.352 64.8 ;
    END
  END o[208]
  PIN o[209]
    DIRECTION OUTPUT ;
    USE SIGNAL ;
    PORT
      LAYER M5 ;
        RECT  53.424 64.716 53.448 64.8 ;
    END
  END o[209]
  PIN o[20]
    DIRECTION OUTPUT ;
    USE SIGNAL ;
    PORT
      LAYER M5 ;
        RECT  28.368 64.716 28.392 64.8 ;
    END
  END o[20]
  PIN o[210]
    DIRECTION OUTPUT ;
    USE SIGNAL ;
    PORT
      LAYER M5 ;
        RECT  53.52 64.716 53.544 64.8 ;
    END
  END o[210]
  PIN o[211]
    DIRECTION OUTPUT ;
    USE SIGNAL ;
    PORT
      LAYER M5 ;
        RECT  53.616 64.716 53.64 64.8 ;
    END
  END o[211]
  PIN o[212]
    DIRECTION OUTPUT ;
    USE SIGNAL ;
    PORT
      LAYER M5 ;
        RECT  53.712 64.716 53.736 64.8 ;
    END
  END o[212]
  PIN o[213]
    DIRECTION OUTPUT ;
    USE SIGNAL ;
    PORT
      LAYER M5 ;
        RECT  53.808 64.716 53.832 64.8 ;
    END
  END o[213]
  PIN o[214]
    DIRECTION OUTPUT ;
    USE SIGNAL ;
    PORT
      LAYER M5 ;
        RECT  53.904 64.716 53.928 64.8 ;
    END
  END o[214]
  PIN o[215]
    DIRECTION OUTPUT ;
    USE SIGNAL ;
    PORT
      LAYER M5 ;
        RECT  54 64.716 54.024 64.8 ;
    END
  END o[215]
  PIN o[216]
    DIRECTION OUTPUT ;
    USE SIGNAL ;
    PORT
      LAYER M5 ;
        RECT  54.096 64.716 54.12 64.8 ;
    END
  END o[216]
  PIN o[217]
    DIRECTION OUTPUT ;
    USE SIGNAL ;
    PORT
      LAYER M5 ;
        RECT  54.192 64.716 54.216 64.8 ;
    END
  END o[217]
  PIN o[218]
    DIRECTION OUTPUT ;
    USE SIGNAL ;
    PORT
      LAYER M5 ;
        RECT  54.288 64.716 54.312 64.8 ;
    END
  END o[218]
  PIN o[219]
    DIRECTION OUTPUT ;
    USE SIGNAL ;
    PORT
      LAYER M5 ;
        RECT  54.384 64.716 54.408 64.8 ;
    END
  END o[219]
  PIN o[21]
    DIRECTION OUTPUT ;
    USE SIGNAL ;
    PORT
      LAYER M5 ;
        RECT  28.464 64.716 28.488 64.8 ;
    END
  END o[21]
  PIN o[220]
    DIRECTION OUTPUT ;
    USE SIGNAL ;
    PORT
      LAYER M5 ;
        RECT  54.48 64.716 54.504 64.8 ;
    END
  END o[220]
  PIN o[221]
    DIRECTION OUTPUT ;
    USE SIGNAL ;
    PORT
      LAYER M5 ;
        RECT  54.576 64.716 54.6 64.8 ;
    END
  END o[221]
  PIN o[222]
    DIRECTION OUTPUT ;
    USE SIGNAL ;
    PORT
      LAYER M5 ;
        RECT  54.672 64.716 54.696 64.8 ;
    END
  END o[222]
  PIN o[223]
    DIRECTION OUTPUT ;
    USE SIGNAL ;
    PORT
      LAYER M5 ;
        RECT  54.768 64.716 54.792 64.8 ;
    END
  END o[223]
  PIN o[224]
    DIRECTION OUTPUT ;
    USE SIGNAL ;
    PORT
      LAYER M5 ;
        RECT  54.864 64.716 54.888 64.8 ;
    END
  END o[224]
  PIN o[225]
    DIRECTION OUTPUT ;
    USE SIGNAL ;
    PORT
      LAYER M5 ;
        RECT  54.96 64.716 54.984 64.8 ;
    END
  END o[225]
  PIN o[226]
    DIRECTION OUTPUT ;
    USE SIGNAL ;
    PORT
      LAYER M5 ;
        RECT  55.056 64.716 55.08 64.8 ;
    END
  END o[226]
  PIN o[227]
    DIRECTION OUTPUT ;
    USE SIGNAL ;
    PORT
      LAYER M5 ;
        RECT  55.152 64.716 55.176 64.8 ;
    END
  END o[227]
  PIN o[228]
    DIRECTION OUTPUT ;
    USE SIGNAL ;
    PORT
      LAYER M5 ;
        RECT  55.248 64.716 55.272 64.8 ;
    END
  END o[228]
  PIN o[229]
    DIRECTION OUTPUT ;
    USE SIGNAL ;
    PORT
      LAYER M5 ;
        RECT  55.344 64.716 55.368 64.8 ;
    END
  END o[229]
  PIN o[22]
    DIRECTION OUTPUT ;
    USE SIGNAL ;
    PORT
      LAYER M5 ;
        RECT  28.56 64.716 28.584 64.8 ;
    END
  END o[22]
  PIN o[230]
    DIRECTION OUTPUT ;
    USE SIGNAL ;
    PORT
      LAYER M5 ;
        RECT  55.44 64.716 55.464 64.8 ;
    END
  END o[230]
  PIN o[231]
    DIRECTION OUTPUT ;
    USE SIGNAL ;
    PORT
      LAYER M5 ;
        RECT  55.536 64.716 55.56 64.8 ;
    END
  END o[231]
  PIN o[232]
    DIRECTION OUTPUT ;
    USE SIGNAL ;
    PORT
      LAYER M5 ;
        RECT  55.632 64.716 55.656 64.8 ;
    END
  END o[232]
  PIN o[233]
    DIRECTION OUTPUT ;
    USE SIGNAL ;
    PORT
      LAYER M5 ;
        RECT  55.728 64.716 55.752 64.8 ;
    END
  END o[233]
  PIN o[234]
    DIRECTION OUTPUT ;
    USE SIGNAL ;
    PORT
      LAYER M5 ;
        RECT  55.824 64.716 55.848 64.8 ;
    END
  END o[234]
  PIN o[235]
    DIRECTION OUTPUT ;
    USE SIGNAL ;
    PORT
      LAYER M5 ;
        RECT  55.92 64.716 55.944 64.8 ;
    END
  END o[235]
  PIN o[236]
    DIRECTION OUTPUT ;
    USE SIGNAL ;
    PORT
      LAYER M5 ;
        RECT  56.016 64.716 56.04 64.8 ;
    END
  END o[236]
  PIN o[237]
    DIRECTION OUTPUT ;
    USE SIGNAL ;
    PORT
      LAYER M5 ;
        RECT  56.112 64.716 56.136 64.8 ;
    END
  END o[237]
  PIN o[238]
    DIRECTION OUTPUT ;
    USE SIGNAL ;
    PORT
      LAYER M5 ;
        RECT  56.208 64.716 56.232 64.8 ;
    END
  END o[238]
  PIN o[239]
    DIRECTION OUTPUT ;
    USE SIGNAL ;
    PORT
      LAYER M5 ;
        RECT  56.304 64.716 56.328 64.8 ;
    END
  END o[239]
  PIN o[23]
    DIRECTION OUTPUT ;
    USE SIGNAL ;
    PORT
      LAYER M5 ;
        RECT  28.656 64.716 28.68 64.8 ;
    END
  END o[23]
  PIN o[240]
    DIRECTION OUTPUT ;
    USE SIGNAL ;
    PORT
      LAYER M5 ;
        RECT  56.4 64.716 56.424 64.8 ;
    END
  END o[240]
  PIN o[241]
    DIRECTION OUTPUT ;
    USE SIGNAL ;
    PORT
      LAYER M5 ;
        RECT  56.496 64.716 56.52 64.8 ;
    END
  END o[241]
  PIN o[242]
    DIRECTION OUTPUT ;
    USE SIGNAL ;
    PORT
      LAYER M5 ;
        RECT  56.592 64.716 56.616 64.8 ;
    END
  END o[242]
  PIN o[243]
    DIRECTION OUTPUT ;
    USE SIGNAL ;
    PORT
      LAYER M5 ;
        RECT  56.688 64.716 56.712 64.8 ;
    END
  END o[243]
  PIN o[244]
    DIRECTION OUTPUT ;
    USE SIGNAL ;
    PORT
      LAYER M5 ;
        RECT  56.784 64.716 56.808 64.8 ;
    END
  END o[244]
  PIN o[245]
    DIRECTION OUTPUT ;
    USE SIGNAL ;
    PORT
      LAYER M5 ;
        RECT  56.88 64.716 56.904 64.8 ;
    END
  END o[245]
  PIN o[246]
    DIRECTION OUTPUT ;
    USE SIGNAL ;
    PORT
      LAYER M5 ;
        RECT  56.976 64.716 57 64.8 ;
    END
  END o[246]
  PIN o[247]
    DIRECTION OUTPUT ;
    USE SIGNAL ;
    PORT
      LAYER M5 ;
        RECT  57.072 64.716 57.096 64.8 ;
    END
  END o[247]
  PIN o[248]
    DIRECTION OUTPUT ;
    USE SIGNAL ;
    PORT
      LAYER M5 ;
        RECT  57.168 64.716 57.192 64.8 ;
    END
  END o[248]
  PIN o[249]
    DIRECTION OUTPUT ;
    USE SIGNAL ;
    PORT
      LAYER M5 ;
        RECT  57.264 64.716 57.288 64.8 ;
    END
  END o[249]
  PIN o[24]
    DIRECTION OUTPUT ;
    USE SIGNAL ;
    PORT
      LAYER M5 ;
        RECT  28.752 64.716 28.776 64.8 ;
    END
  END o[24]
  PIN o[250]
    DIRECTION OUTPUT ;
    USE SIGNAL ;
    PORT
      LAYER M5 ;
        RECT  57.36 64.716 57.384 64.8 ;
    END
  END o[250]
  PIN o[251]
    DIRECTION OUTPUT ;
    USE SIGNAL ;
    PORT
      LAYER M5 ;
        RECT  57.456 64.716 57.48 64.8 ;
    END
  END o[251]
  PIN o[252]
    DIRECTION OUTPUT ;
    USE SIGNAL ;
    PORT
      LAYER M5 ;
        RECT  57.552 64.716 57.576 64.8 ;
    END
  END o[252]
  PIN o[253]
    DIRECTION OUTPUT ;
    USE SIGNAL ;
    PORT
      LAYER M5 ;
        RECT  57.648 64.716 57.672 64.8 ;
    END
  END o[253]
  PIN o[254]
    DIRECTION OUTPUT ;
    USE SIGNAL ;
    PORT
      LAYER M5 ;
        RECT  57.744 64.716 57.768 64.8 ;
    END
  END o[254]
  PIN o[255]
    DIRECTION OUTPUT ;
    USE SIGNAL ;
    PORT
      LAYER M5 ;
        RECT  57.84 64.716 57.864 64.8 ;
    END
  END o[255]
  PIN o[256]
    DIRECTION OUTPUT ;
    USE SIGNAL ;
    PORT
      LAYER M5 ;
        RECT  35.664 64.716 35.688 64.8 ;
    END
  END o[256]
  PIN o[257]
    DIRECTION OUTPUT ;
    USE SIGNAL ;
    PORT
      LAYER M5 ;
        RECT  35.76 64.716 35.784 64.8 ;
    END
  END o[257]
  PIN o[258]
    DIRECTION OUTPUT ;
    USE SIGNAL ;
    PORT
      LAYER M5 ;
        RECT  35.856 64.716 35.88 64.8 ;
    END
  END o[258]
  PIN o[259]
    DIRECTION OUTPUT ;
    USE SIGNAL ;
    PORT
      LAYER M5 ;
        RECT  35.952 64.716 35.976 64.8 ;
    END
  END o[259]
  PIN o[25]
    DIRECTION OUTPUT ;
    USE SIGNAL ;
    PORT
      LAYER M5 ;
        RECT  28.848 64.716 28.872 64.8 ;
    END
  END o[25]
  PIN o[260]
    DIRECTION OUTPUT ;
    USE SIGNAL ;
    PORT
      LAYER M5 ;
        RECT  36.048 64.716 36.072 64.8 ;
    END
  END o[260]
  PIN o[261]
    DIRECTION OUTPUT ;
    USE SIGNAL ;
    PORT
      LAYER M5 ;
        RECT  36.144 64.716 36.168 64.8 ;
    END
  END o[261]
  PIN o[262]
    DIRECTION OUTPUT ;
    USE SIGNAL ;
    PORT
      LAYER M5 ;
        RECT  36.24 64.716 36.264 64.8 ;
    END
  END o[262]
  PIN o[263]
    DIRECTION OUTPUT ;
    USE SIGNAL ;
    PORT
      LAYER M5 ;
        RECT  36.336 64.716 36.36 64.8 ;
    END
  END o[263]
  PIN o[264]
    DIRECTION OUTPUT ;
    USE SIGNAL ;
    PORT
      LAYER M5 ;
        RECT  36.432 64.716 36.456 64.8 ;
    END
  END o[264]
  PIN o[265]
    DIRECTION OUTPUT ;
    USE SIGNAL ;
    PORT
      LAYER M5 ;
        RECT  36.528 64.716 36.552 64.8 ;
    END
  END o[265]
  PIN o[266]
    DIRECTION OUTPUT ;
    USE SIGNAL ;
    PORT
      LAYER M5 ;
        RECT  36.624 64.716 36.648 64.8 ;
    END
  END o[266]
  PIN o[267]
    DIRECTION OUTPUT ;
    USE SIGNAL ;
    PORT
      LAYER M5 ;
        RECT  36.72 64.716 36.744 64.8 ;
    END
  END o[267]
  PIN o[268]
    DIRECTION OUTPUT ;
    USE SIGNAL ;
    PORT
      LAYER M5 ;
        RECT  36.816 64.716 36.84 64.8 ;
    END
  END o[268]
  PIN o[269]
    DIRECTION OUTPUT ;
    USE SIGNAL ;
    PORT
      LAYER M5 ;
        RECT  36.912 64.716 36.936 64.8 ;
    END
  END o[269]
  PIN o[26]
    DIRECTION OUTPUT ;
    USE SIGNAL ;
    PORT
      LAYER M5 ;
        RECT  28.944 64.716 28.968 64.8 ;
    END
  END o[26]
  PIN o[270]
    DIRECTION OUTPUT ;
    USE SIGNAL ;
    PORT
      LAYER M5 ;
        RECT  37.008 64.716 37.032 64.8 ;
    END
  END o[270]
  PIN o[271]
    DIRECTION OUTPUT ;
    USE SIGNAL ;
    PORT
      LAYER M5 ;
        RECT  37.104 64.716 37.128 64.8 ;
    END
  END o[271]
  PIN o[272]
    DIRECTION OUTPUT ;
    USE SIGNAL ;
    PORT
      LAYER M5 ;
        RECT  37.2 64.716 37.224 64.8 ;
    END
  END o[272]
  PIN o[273]
    DIRECTION OUTPUT ;
    USE SIGNAL ;
    PORT
      LAYER M5 ;
        RECT  37.296 64.716 37.32 64.8 ;
    END
  END o[273]
  PIN o[274]
    DIRECTION OUTPUT ;
    USE SIGNAL ;
    PORT
      LAYER M5 ;
        RECT  37.392 64.716 37.416 64.8 ;
    END
  END o[274]
  PIN o[275]
    DIRECTION OUTPUT ;
    USE SIGNAL ;
    PORT
      LAYER M5 ;
        RECT  37.488 64.716 37.512 64.8 ;
    END
  END o[275]
  PIN o[276]
    DIRECTION OUTPUT ;
    USE SIGNAL ;
    PORT
      LAYER M5 ;
        RECT  37.584 64.716 37.608 64.8 ;
    END
  END o[276]
  PIN o[277]
    DIRECTION OUTPUT ;
    USE SIGNAL ;
    PORT
      LAYER M5 ;
        RECT  37.68 64.716 37.704 64.8 ;
    END
  END o[277]
  PIN o[278]
    DIRECTION OUTPUT ;
    USE SIGNAL ;
    PORT
      LAYER M5 ;
        RECT  37.776 64.716 37.8 64.8 ;
    END
  END o[278]
  PIN o[279]
    DIRECTION OUTPUT ;
    USE SIGNAL ;
    PORT
      LAYER M5 ;
        RECT  37.872 64.716 37.896 64.8 ;
    END
  END o[279]
  PIN o[27]
    DIRECTION OUTPUT ;
    USE SIGNAL ;
    PORT
      LAYER M5 ;
        RECT  29.04 64.716 29.064 64.8 ;
    END
  END o[27]
  PIN o[280]
    DIRECTION OUTPUT ;
    USE SIGNAL ;
    PORT
      LAYER M5 ;
        RECT  37.968 64.716 37.992 64.8 ;
    END
  END o[280]
  PIN o[281]
    DIRECTION OUTPUT ;
    USE SIGNAL ;
    PORT
      LAYER M5 ;
        RECT  38.064 64.716 38.088 64.8 ;
    END
  END o[281]
  PIN o[282]
    DIRECTION OUTPUT ;
    USE SIGNAL ;
    PORT
      LAYER M5 ;
        RECT  38.16 64.716 38.184 64.8 ;
    END
  END o[282]
  PIN o[283]
    DIRECTION OUTPUT ;
    USE SIGNAL ;
    PORT
      LAYER M5 ;
        RECT  38.256 64.716 38.28 64.8 ;
    END
  END o[283]
  PIN o[284]
    DIRECTION OUTPUT ;
    USE SIGNAL ;
    PORT
      LAYER M5 ;
        RECT  38.352 64.716 38.376 64.8 ;
    END
  END o[284]
  PIN o[285]
    DIRECTION OUTPUT ;
    USE SIGNAL ;
    PORT
      LAYER M5 ;
        RECT  38.448 64.716 38.472 64.8 ;
    END
  END o[285]
  PIN o[286]
    DIRECTION OUTPUT ;
    USE SIGNAL ;
    PORT
      LAYER M5 ;
        RECT  38.544 64.716 38.568 64.8 ;
    END
  END o[286]
  PIN o[287]
    DIRECTION OUTPUT ;
    USE SIGNAL ;
    PORT
      LAYER M5 ;
        RECT  38.64 64.716 38.664 64.8 ;
    END
  END o[287]
  PIN o[288]
    DIRECTION OUTPUT ;
    USE SIGNAL ;
    PORT
      LAYER M5 ;
        RECT  29.52 64.716 29.544 64.8 ;
    END
  END o[288]
  PIN o[289]
    DIRECTION OUTPUT ;
    USE SIGNAL ;
    PORT
      LAYER M5 ;
        RECT  29.616 64.716 29.64 64.8 ;
    END
  END o[289]
  PIN o[28]
    DIRECTION OUTPUT ;
    USE SIGNAL ;
    PORT
      LAYER M5 ;
        RECT  29.136 64.716 29.16 64.8 ;
    END
  END o[28]
  PIN o[290]
    DIRECTION OUTPUT ;
    USE SIGNAL ;
    PORT
      LAYER M5 ;
        RECT  29.712 64.716 29.736 64.8 ;
    END
  END o[290]
  PIN o[291]
    DIRECTION OUTPUT ;
    USE SIGNAL ;
    PORT
      LAYER M5 ;
        RECT  29.808 64.716 29.832 64.8 ;
    END
  END o[291]
  PIN o[292]
    DIRECTION OUTPUT ;
    USE SIGNAL ;
    PORT
      LAYER M5 ;
        RECT  29.904 64.716 29.928 64.8 ;
    END
  END o[292]
  PIN o[293]
    DIRECTION OUTPUT ;
    USE SIGNAL ;
    PORT
      LAYER M5 ;
        RECT  30 64.716 30.024 64.8 ;
    END
  END o[293]
  PIN o[294]
    DIRECTION OUTPUT ;
    USE SIGNAL ;
    PORT
      LAYER M5 ;
        RECT  30.096 64.716 30.12 64.8 ;
    END
  END o[294]
  PIN o[295]
    DIRECTION OUTPUT ;
    USE SIGNAL ;
    PORT
      LAYER M5 ;
        RECT  30.192 64.716 30.216 64.8 ;
    END
  END o[295]
  PIN o[296]
    DIRECTION OUTPUT ;
    USE SIGNAL ;
    PORT
      LAYER M5 ;
        RECT  30.288 64.716 30.312 64.8 ;
    END
  END o[296]
  PIN o[297]
    DIRECTION OUTPUT ;
    USE SIGNAL ;
    PORT
      LAYER M5 ;
        RECT  30.384 64.716 30.408 64.8 ;
    END
  END o[297]
  PIN o[298]
    DIRECTION OUTPUT ;
    USE SIGNAL ;
    PORT
      LAYER M5 ;
        RECT  30.48 64.716 30.504 64.8 ;
    END
  END o[298]
  PIN o[299]
    DIRECTION OUTPUT ;
    USE SIGNAL ;
    PORT
      LAYER M5 ;
        RECT  30.576 64.716 30.6 64.8 ;
    END
  END o[299]
  PIN o[29]
    DIRECTION OUTPUT ;
    USE SIGNAL ;
    PORT
      LAYER M5 ;
        RECT  29.232 64.716 29.256 64.8 ;
    END
  END o[29]
  PIN o[2]
    DIRECTION OUTPUT ;
    USE SIGNAL ;
    PORT
      LAYER M5 ;
        RECT  26.64 64.716 26.664 64.8 ;
    END
  END o[2]
  PIN o[300]
    DIRECTION OUTPUT ;
    USE SIGNAL ;
    PORT
      LAYER M5 ;
        RECT  30.672 64.716 30.696 64.8 ;
    END
  END o[300]
  PIN o[301]
    DIRECTION OUTPUT ;
    USE SIGNAL ;
    PORT
      LAYER M5 ;
        RECT  30.768 64.716 30.792 64.8 ;
    END
  END o[301]
  PIN o[302]
    DIRECTION OUTPUT ;
    USE SIGNAL ;
    PORT
      LAYER M5 ;
        RECT  30.864 64.716 30.888 64.8 ;
    END
  END o[302]
  PIN o[303]
    DIRECTION OUTPUT ;
    USE SIGNAL ;
    PORT
      LAYER M5 ;
        RECT  30.96 64.716 30.984 64.8 ;
    END
  END o[303]
  PIN o[304]
    DIRECTION OUTPUT ;
    USE SIGNAL ;
    PORT
      LAYER M5 ;
        RECT  31.056 64.716 31.08 64.8 ;
    END
  END o[304]
  PIN o[305]
    DIRECTION OUTPUT ;
    USE SIGNAL ;
    PORT
      LAYER M5 ;
        RECT  31.152 64.716 31.176 64.8 ;
    END
  END o[305]
  PIN o[306]
    DIRECTION OUTPUT ;
    USE SIGNAL ;
    PORT
      LAYER M5 ;
        RECT  31.248 64.716 31.272 64.8 ;
    END
  END o[306]
  PIN o[307]
    DIRECTION OUTPUT ;
    USE SIGNAL ;
    PORT
      LAYER M5 ;
        RECT  31.344 64.716 31.368 64.8 ;
    END
  END o[307]
  PIN o[308]
    DIRECTION OUTPUT ;
    USE SIGNAL ;
    PORT
      LAYER M5 ;
        RECT  31.44 64.716 31.464 64.8 ;
    END
  END o[308]
  PIN o[309]
    DIRECTION OUTPUT ;
    USE SIGNAL ;
    PORT
      LAYER M5 ;
        RECT  31.536 64.716 31.56 64.8 ;
    END
  END o[309]
  PIN o[30]
    DIRECTION OUTPUT ;
    USE SIGNAL ;
    PORT
      LAYER M5 ;
        RECT  29.328 64.716 29.352 64.8 ;
    END
  END o[30]
  PIN o[310]
    DIRECTION OUTPUT ;
    USE SIGNAL ;
    PORT
      LAYER M5 ;
        RECT  31.632 64.716 31.656 64.8 ;
    END
  END o[310]
  PIN o[311]
    DIRECTION OUTPUT ;
    USE SIGNAL ;
    PORT
      LAYER M5 ;
        RECT  31.728 64.716 31.752 64.8 ;
    END
  END o[311]
  PIN o[312]
    DIRECTION OUTPUT ;
    USE SIGNAL ;
    PORT
      LAYER M5 ;
        RECT  31.824 64.716 31.848 64.8 ;
    END
  END o[312]
  PIN o[313]
    DIRECTION OUTPUT ;
    USE SIGNAL ;
    PORT
      LAYER M5 ;
        RECT  31.92 64.716 31.944 64.8 ;
    END
  END o[313]
  PIN o[314]
    DIRECTION OUTPUT ;
    USE SIGNAL ;
    PORT
      LAYER M5 ;
        RECT  32.016 64.716 32.04 64.8 ;
    END
  END o[314]
  PIN o[315]
    DIRECTION OUTPUT ;
    USE SIGNAL ;
    PORT
      LAYER M5 ;
        RECT  32.112 64.716 32.136 64.8 ;
    END
  END o[315]
  PIN o[316]
    DIRECTION OUTPUT ;
    USE SIGNAL ;
    PORT
      LAYER M5 ;
        RECT  32.208 64.716 32.232 64.8 ;
    END
  END o[316]
  PIN o[317]
    DIRECTION OUTPUT ;
    USE SIGNAL ;
    PORT
      LAYER M5 ;
        RECT  32.304 64.716 32.328 64.8 ;
    END
  END o[317]
  PIN o[318]
    DIRECTION OUTPUT ;
    USE SIGNAL ;
    PORT
      LAYER M5 ;
        RECT  32.4 64.716 32.424 64.8 ;
    END
  END o[318]
  PIN o[319]
    DIRECTION OUTPUT ;
    USE SIGNAL ;
    PORT
      LAYER M5 ;
        RECT  32.496 64.716 32.52 64.8 ;
    END
  END o[319]
  PIN o[31]
    DIRECTION OUTPUT ;
    USE SIGNAL ;
    PORT
      LAYER M5 ;
        RECT  29.424 64.716 29.448 64.8 ;
    END
  END o[31]
  PIN o[320]
    DIRECTION OUTPUT ;
    USE SIGNAL ;
    PORT
      LAYER M5 ;
        RECT  19.536 64.716 19.56 64.8 ;
    END
  END o[320]
  PIN o[321]
    DIRECTION OUTPUT ;
    USE SIGNAL ;
    PORT
      LAYER M5 ;
        RECT  19.632 64.716 19.656 64.8 ;
    END
  END o[321]
  PIN o[322]
    DIRECTION OUTPUT ;
    USE SIGNAL ;
    PORT
      LAYER M5 ;
        RECT  19.728 64.716 19.752 64.8 ;
    END
  END o[322]
  PIN o[323]
    DIRECTION OUTPUT ;
    USE SIGNAL ;
    PORT
      LAYER M5 ;
        RECT  19.824 64.716 19.848 64.8 ;
    END
  END o[323]
  PIN o[324]
    DIRECTION OUTPUT ;
    USE SIGNAL ;
    PORT
      LAYER M5 ;
        RECT  19.92 64.716 19.944 64.8 ;
    END
  END o[324]
  PIN o[325]
    DIRECTION OUTPUT ;
    USE SIGNAL ;
    PORT
      LAYER M5 ;
        RECT  20.016 64.716 20.04 64.8 ;
    END
  END o[325]
  PIN o[326]
    DIRECTION OUTPUT ;
    USE SIGNAL ;
    PORT
      LAYER M5 ;
        RECT  20.112 64.716 20.136 64.8 ;
    END
  END o[326]
  PIN o[327]
    DIRECTION OUTPUT ;
    USE SIGNAL ;
    PORT
      LAYER M5 ;
        RECT  20.208 64.716 20.232 64.8 ;
    END
  END o[327]
  PIN o[328]
    DIRECTION OUTPUT ;
    USE SIGNAL ;
    PORT
      LAYER M5 ;
        RECT  20.304 64.716 20.328 64.8 ;
    END
  END o[328]
  PIN o[329]
    DIRECTION OUTPUT ;
    USE SIGNAL ;
    PORT
      LAYER M5 ;
        RECT  20.4 64.716 20.424 64.8 ;
    END
  END o[329]
  PIN o[32]
    DIRECTION OUTPUT ;
    USE SIGNAL ;
    PORT
      LAYER M5 ;
        RECT  32.592 64.716 32.616 64.8 ;
    END
  END o[32]
  PIN o[330]
    DIRECTION OUTPUT ;
    USE SIGNAL ;
    PORT
      LAYER M5 ;
        RECT  20.496 64.716 20.52 64.8 ;
    END
  END o[330]
  PIN o[331]
    DIRECTION OUTPUT ;
    USE SIGNAL ;
    PORT
      LAYER M5 ;
        RECT  20.592 64.716 20.616 64.8 ;
    END
  END o[331]
  PIN o[332]
    DIRECTION OUTPUT ;
    USE SIGNAL ;
    PORT
      LAYER M5 ;
        RECT  20.688 64.716 20.712 64.8 ;
    END
  END o[332]
  PIN o[333]
    DIRECTION OUTPUT ;
    USE SIGNAL ;
    PORT
      LAYER M5 ;
        RECT  20.784 64.716 20.808 64.8 ;
    END
  END o[333]
  PIN o[334]
    DIRECTION OUTPUT ;
    USE SIGNAL ;
    PORT
      LAYER M5 ;
        RECT  20.88 64.716 20.904 64.8 ;
    END
  END o[334]
  PIN o[335]
    DIRECTION OUTPUT ;
    USE SIGNAL ;
    PORT
      LAYER M5 ;
        RECT  20.976 64.716 21 64.8 ;
    END
  END o[335]
  PIN o[336]
    DIRECTION OUTPUT ;
    USE SIGNAL ;
    PORT
      LAYER M5 ;
        RECT  21.072 64.716 21.096 64.8 ;
    END
  END o[336]
  PIN o[337]
    DIRECTION OUTPUT ;
    USE SIGNAL ;
    PORT
      LAYER M5 ;
        RECT  21.168 64.716 21.192 64.8 ;
    END
  END o[337]
  PIN o[338]
    DIRECTION OUTPUT ;
    USE SIGNAL ;
    PORT
      LAYER M5 ;
        RECT  21.264 64.716 21.288 64.8 ;
    END
  END o[338]
  PIN o[339]
    DIRECTION OUTPUT ;
    USE SIGNAL ;
    PORT
      LAYER M5 ;
        RECT  21.36 64.716 21.384 64.8 ;
    END
  END o[339]
  PIN o[33]
    DIRECTION OUTPUT ;
    USE SIGNAL ;
    PORT
      LAYER M5 ;
        RECT  32.688 64.716 32.712 64.8 ;
    END
  END o[33]
  PIN o[340]
    DIRECTION OUTPUT ;
    USE SIGNAL ;
    PORT
      LAYER M5 ;
        RECT  21.456 64.716 21.48 64.8 ;
    END
  END o[340]
  PIN o[341]
    DIRECTION OUTPUT ;
    USE SIGNAL ;
    PORT
      LAYER M5 ;
        RECT  21.552 64.716 21.576 64.8 ;
    END
  END o[341]
  PIN o[342]
    DIRECTION OUTPUT ;
    USE SIGNAL ;
    PORT
      LAYER M5 ;
        RECT  21.648 64.716 21.672 64.8 ;
    END
  END o[342]
  PIN o[343]
    DIRECTION OUTPUT ;
    USE SIGNAL ;
    PORT
      LAYER M5 ;
        RECT  21.744 64.716 21.768 64.8 ;
    END
  END o[343]
  PIN o[344]
    DIRECTION OUTPUT ;
    USE SIGNAL ;
    PORT
      LAYER M5 ;
        RECT  21.84 64.716 21.864 64.8 ;
    END
  END o[344]
  PIN o[345]
    DIRECTION OUTPUT ;
    USE SIGNAL ;
    PORT
      LAYER M5 ;
        RECT  21.936 64.716 21.96 64.8 ;
    END
  END o[345]
  PIN o[346]
    DIRECTION OUTPUT ;
    USE SIGNAL ;
    PORT
      LAYER M5 ;
        RECT  22.032 64.716 22.056 64.8 ;
    END
  END o[346]
  PIN o[347]
    DIRECTION OUTPUT ;
    USE SIGNAL ;
    PORT
      LAYER M5 ;
        RECT  22.128 64.716 22.152 64.8 ;
    END
  END o[347]
  PIN o[348]
    DIRECTION OUTPUT ;
    USE SIGNAL ;
    PORT
      LAYER M5 ;
        RECT  22.224 64.716 22.248 64.8 ;
    END
  END o[348]
  PIN o[349]
    DIRECTION OUTPUT ;
    USE SIGNAL ;
    PORT
      LAYER M5 ;
        RECT  22.32 64.716 22.344 64.8 ;
    END
  END o[349]
  PIN o[34]
    DIRECTION OUTPUT ;
    USE SIGNAL ;
    PORT
      LAYER M5 ;
        RECT  32.784 64.716 32.808 64.8 ;
    END
  END o[34]
  PIN o[350]
    DIRECTION OUTPUT ;
    USE SIGNAL ;
    PORT
      LAYER M5 ;
        RECT  22.416 64.716 22.44 64.8 ;
    END
  END o[350]
  PIN o[351]
    DIRECTION OUTPUT ;
    USE SIGNAL ;
    PORT
      LAYER M5 ;
        RECT  22.512 64.716 22.536 64.8 ;
    END
  END o[351]
  PIN o[352]
    DIRECTION OUTPUT ;
    USE SIGNAL ;
    PORT
      LAYER M5 ;
        RECT  7.248 64.716 7.272 64.8 ;
    END
  END o[352]
  PIN o[353]
    DIRECTION OUTPUT ;
    USE SIGNAL ;
    PORT
      LAYER M5 ;
        RECT  7.344 64.716 7.368 64.8 ;
    END
  END o[353]
  PIN o[354]
    DIRECTION OUTPUT ;
    USE SIGNAL ;
    PORT
      LAYER M5 ;
        RECT  7.44 64.716 7.464 64.8 ;
    END
  END o[354]
  PIN o[355]
    DIRECTION OUTPUT ;
    USE SIGNAL ;
    PORT
      LAYER M5 ;
        RECT  7.536 64.716 7.56 64.8 ;
    END
  END o[355]
  PIN o[356]
    DIRECTION OUTPUT ;
    USE SIGNAL ;
    PORT
      LAYER M5 ;
        RECT  7.632 64.716 7.656 64.8 ;
    END
  END o[356]
  PIN o[357]
    DIRECTION OUTPUT ;
    USE SIGNAL ;
    PORT
      LAYER M5 ;
        RECT  7.728 64.716 7.752 64.8 ;
    END
  END o[357]
  PIN o[358]
    DIRECTION OUTPUT ;
    USE SIGNAL ;
    PORT
      LAYER M5 ;
        RECT  7.824 64.716 7.848 64.8 ;
    END
  END o[358]
  PIN o[359]
    DIRECTION OUTPUT ;
    USE SIGNAL ;
    PORT
      LAYER M5 ;
        RECT  7.92 64.716 7.944 64.8 ;
    END
  END o[359]
  PIN o[35]
    DIRECTION OUTPUT ;
    USE SIGNAL ;
    PORT
      LAYER M5 ;
        RECT  32.88 64.716 32.904 64.8 ;
    END
  END o[35]
  PIN o[360]
    DIRECTION OUTPUT ;
    USE SIGNAL ;
    PORT
      LAYER M5 ;
        RECT  8.016 64.716 8.04 64.8 ;
    END
  END o[360]
  PIN o[361]
    DIRECTION OUTPUT ;
    USE SIGNAL ;
    PORT
      LAYER M5 ;
        RECT  8.112 64.716 8.136 64.8 ;
    END
  END o[361]
  PIN o[362]
    DIRECTION OUTPUT ;
    USE SIGNAL ;
    PORT
      LAYER M5 ;
        RECT  8.208 64.716 8.232 64.8 ;
    END
  END o[362]
  PIN o[363]
    DIRECTION OUTPUT ;
    USE SIGNAL ;
    PORT
      LAYER M5 ;
        RECT  8.304 64.716 8.328 64.8 ;
    END
  END o[363]
  PIN o[364]
    DIRECTION OUTPUT ;
    USE SIGNAL ;
    PORT
      LAYER M5 ;
        RECT  8.4 64.716 8.424 64.8 ;
    END
  END o[364]
  PIN o[365]
    DIRECTION OUTPUT ;
    USE SIGNAL ;
    PORT
      LAYER M5 ;
        RECT  8.496 64.716 8.52 64.8 ;
    END
  END o[365]
  PIN o[366]
    DIRECTION OUTPUT ;
    USE SIGNAL ;
    PORT
      LAYER M5 ;
        RECT  8.592 64.716 8.616 64.8 ;
    END
  END o[366]
  PIN o[367]
    DIRECTION OUTPUT ;
    USE SIGNAL ;
    PORT
      LAYER M5 ;
        RECT  8.688 64.716 8.712 64.8 ;
    END
  END o[367]
  PIN o[368]
    DIRECTION OUTPUT ;
    USE SIGNAL ;
    PORT
      LAYER M5 ;
        RECT  8.784 64.716 8.808 64.8 ;
    END
  END o[368]
  PIN o[369]
    DIRECTION OUTPUT ;
    USE SIGNAL ;
    PORT
      LAYER M5 ;
        RECT  8.88 64.716 8.904 64.8 ;
    END
  END o[369]
  PIN o[36]
    DIRECTION OUTPUT ;
    USE SIGNAL ;
    PORT
      LAYER M5 ;
        RECT  32.976 64.716 33 64.8 ;
    END
  END o[36]
  PIN o[370]
    DIRECTION OUTPUT ;
    USE SIGNAL ;
    PORT
      LAYER M5 ;
        RECT  8.976 64.716 9 64.8 ;
    END
  END o[370]
  PIN o[371]
    DIRECTION OUTPUT ;
    USE SIGNAL ;
    PORT
      LAYER M5 ;
        RECT  9.072 64.716 9.096 64.8 ;
    END
  END o[371]
  PIN o[372]
    DIRECTION OUTPUT ;
    USE SIGNAL ;
    PORT
      LAYER M5 ;
        RECT  9.168 64.716 9.192 64.8 ;
    END
  END o[372]
  PIN o[373]
    DIRECTION OUTPUT ;
    USE SIGNAL ;
    PORT
      LAYER M5 ;
        RECT  9.264 64.716 9.288 64.8 ;
    END
  END o[373]
  PIN o[374]
    DIRECTION OUTPUT ;
    USE SIGNAL ;
    PORT
      LAYER M5 ;
        RECT  9.36 64.716 9.384 64.8 ;
    END
  END o[374]
  PIN o[375]
    DIRECTION OUTPUT ;
    USE SIGNAL ;
    PORT
      LAYER M5 ;
        RECT  9.456 64.716 9.48 64.8 ;
    END
  END o[375]
  PIN o[376]
    DIRECTION OUTPUT ;
    USE SIGNAL ;
    PORT
      LAYER M5 ;
        RECT  9.552 64.716 9.576 64.8 ;
    END
  END o[376]
  PIN o[377]
    DIRECTION OUTPUT ;
    USE SIGNAL ;
    PORT
      LAYER M5 ;
        RECT  9.648 64.716 9.672 64.8 ;
    END
  END o[377]
  PIN o[378]
    DIRECTION OUTPUT ;
    USE SIGNAL ;
    PORT
      LAYER M5 ;
        RECT  9.744 64.716 9.768 64.8 ;
    END
  END o[378]
  PIN o[379]
    DIRECTION OUTPUT ;
    USE SIGNAL ;
    PORT
      LAYER M5 ;
        RECT  9.84 64.716 9.864 64.8 ;
    END
  END o[379]
  PIN o[37]
    DIRECTION OUTPUT ;
    USE SIGNAL ;
    PORT
      LAYER M5 ;
        RECT  33.072 64.716 33.096 64.8 ;
    END
  END o[37]
  PIN o[380]
    DIRECTION OUTPUT ;
    USE SIGNAL ;
    PORT
      LAYER M5 ;
        RECT  9.936 64.716 9.96 64.8 ;
    END
  END o[380]
  PIN o[381]
    DIRECTION OUTPUT ;
    USE SIGNAL ;
    PORT
      LAYER M5 ;
        RECT  10.032 64.716 10.056 64.8 ;
    END
  END o[381]
  PIN o[382]
    DIRECTION OUTPUT ;
    USE SIGNAL ;
    PORT
      LAYER M5 ;
        RECT  10.128 64.716 10.152 64.8 ;
    END
  END o[382]
  PIN o[383]
    DIRECTION OUTPUT ;
    USE SIGNAL ;
    PORT
      LAYER M5 ;
        RECT  10.224 64.716 10.248 64.8 ;
    END
  END o[383]
  PIN o[384]
    DIRECTION OUTPUT ;
    USE SIGNAL ;
    PORT
      LAYER M5 ;
        RECT  10.32 64.716 10.344 64.8 ;
    END
  END o[384]
  PIN o[385]
    DIRECTION OUTPUT ;
    USE SIGNAL ;
    PORT
      LAYER M5 ;
        RECT  10.416 64.716 10.44 64.8 ;
    END
  END o[385]
  PIN o[386]
    DIRECTION OUTPUT ;
    USE SIGNAL ;
    PORT
      LAYER M5 ;
        RECT  10.512 64.716 10.536 64.8 ;
    END
  END o[386]
  PIN o[387]
    DIRECTION OUTPUT ;
    USE SIGNAL ;
    PORT
      LAYER M5 ;
        RECT  10.608 64.716 10.632 64.8 ;
    END
  END o[387]
  PIN o[388]
    DIRECTION OUTPUT ;
    USE SIGNAL ;
    PORT
      LAYER M5 ;
        RECT  10.704 64.716 10.728 64.8 ;
    END
  END o[388]
  PIN o[389]
    DIRECTION OUTPUT ;
    USE SIGNAL ;
    PORT
      LAYER M5 ;
        RECT  10.8 64.716 10.824 64.8 ;
    END
  END o[389]
  PIN o[38]
    DIRECTION OUTPUT ;
    USE SIGNAL ;
    PORT
      LAYER M5 ;
        RECT  33.168 64.716 33.192 64.8 ;
    END
  END o[38]
  PIN o[390]
    DIRECTION OUTPUT ;
    USE SIGNAL ;
    PORT
      LAYER M5 ;
        RECT  10.896 64.716 10.92 64.8 ;
    END
  END o[390]
  PIN o[391]
    DIRECTION OUTPUT ;
    USE SIGNAL ;
    PORT
      LAYER M5 ;
        RECT  10.992 64.716 11.016 64.8 ;
    END
  END o[391]
  PIN o[392]
    DIRECTION OUTPUT ;
    USE SIGNAL ;
    PORT
      LAYER M5 ;
        RECT  11.088 64.716 11.112 64.8 ;
    END
  END o[392]
  PIN o[393]
    DIRECTION OUTPUT ;
    USE SIGNAL ;
    PORT
      LAYER M5 ;
        RECT  11.184 64.716 11.208 64.8 ;
    END
  END o[393]
  PIN o[394]
    DIRECTION OUTPUT ;
    USE SIGNAL ;
    PORT
      LAYER M5 ;
        RECT  11.28 64.716 11.304 64.8 ;
    END
  END o[394]
  PIN o[395]
    DIRECTION OUTPUT ;
    USE SIGNAL ;
    PORT
      LAYER M5 ;
        RECT  11.376 64.716 11.4 64.8 ;
    END
  END o[395]
  PIN o[396]
    DIRECTION OUTPUT ;
    USE SIGNAL ;
    PORT
      LAYER M5 ;
        RECT  11.472 64.716 11.496 64.8 ;
    END
  END o[396]
  PIN o[397]
    DIRECTION OUTPUT ;
    USE SIGNAL ;
    PORT
      LAYER M5 ;
        RECT  11.568 64.716 11.592 64.8 ;
    END
  END o[397]
  PIN o[398]
    DIRECTION OUTPUT ;
    USE SIGNAL ;
    PORT
      LAYER M5 ;
        RECT  11.664 64.716 11.688 64.8 ;
    END
  END o[398]
  PIN o[399]
    DIRECTION OUTPUT ;
    USE SIGNAL ;
    PORT
      LAYER M5 ;
        RECT  11.76 64.716 11.784 64.8 ;
    END
  END o[399]
  PIN o[39]
    DIRECTION OUTPUT ;
    USE SIGNAL ;
    PORT
      LAYER M5 ;
        RECT  33.264 64.716 33.288 64.8 ;
    END
  END o[39]
  PIN o[3]
    DIRECTION OUTPUT ;
    USE SIGNAL ;
    PORT
      LAYER M5 ;
        RECT  26.736 64.716 26.76 64.8 ;
    END
  END o[3]
  PIN o[400]
    DIRECTION OUTPUT ;
    USE SIGNAL ;
    PORT
      LAYER M5 ;
        RECT  11.856 64.716 11.88 64.8 ;
    END
  END o[400]
  PIN o[401]
    DIRECTION OUTPUT ;
    USE SIGNAL ;
    PORT
      LAYER M5 ;
        RECT  11.952 64.716 11.976 64.8 ;
    END
  END o[401]
  PIN o[402]
    DIRECTION OUTPUT ;
    USE SIGNAL ;
    PORT
      LAYER M5 ;
        RECT  12.048 64.716 12.072 64.8 ;
    END
  END o[402]
  PIN o[403]
    DIRECTION OUTPUT ;
    USE SIGNAL ;
    PORT
      LAYER M5 ;
        RECT  12.144 64.716 12.168 64.8 ;
    END
  END o[403]
  PIN o[404]
    DIRECTION OUTPUT ;
    USE SIGNAL ;
    PORT
      LAYER M5 ;
        RECT  12.24 64.716 12.264 64.8 ;
    END
  END o[404]
  PIN o[405]
    DIRECTION OUTPUT ;
    USE SIGNAL ;
    PORT
      LAYER M5 ;
        RECT  12.336 64.716 12.36 64.8 ;
    END
  END o[405]
  PIN o[406]
    DIRECTION OUTPUT ;
    USE SIGNAL ;
    PORT
      LAYER M5 ;
        RECT  12.432 64.716 12.456 64.8 ;
    END
  END o[406]
  PIN o[407]
    DIRECTION OUTPUT ;
    USE SIGNAL ;
    PORT
      LAYER M5 ;
        RECT  12.528 64.716 12.552 64.8 ;
    END
  END o[407]
  PIN o[408]
    DIRECTION OUTPUT ;
    USE SIGNAL ;
    PORT
      LAYER M5 ;
        RECT  12.624 64.716 12.648 64.8 ;
    END
  END o[408]
  PIN o[409]
    DIRECTION OUTPUT ;
    USE SIGNAL ;
    PORT
      LAYER M5 ;
        RECT  12.72 64.716 12.744 64.8 ;
    END
  END o[409]
  PIN o[40]
    DIRECTION OUTPUT ;
    USE SIGNAL ;
    PORT
      LAYER M5 ;
        RECT  33.36 64.716 33.384 64.8 ;
    END
  END o[40]
  PIN o[410]
    DIRECTION OUTPUT ;
    USE SIGNAL ;
    PORT
      LAYER M5 ;
        RECT  12.816 64.716 12.84 64.8 ;
    END
  END o[410]
  PIN o[411]
    DIRECTION OUTPUT ;
    USE SIGNAL ;
    PORT
      LAYER M5 ;
        RECT  12.912 64.716 12.936 64.8 ;
    END
  END o[411]
  PIN o[412]
    DIRECTION OUTPUT ;
    USE SIGNAL ;
    PORT
      LAYER M5 ;
        RECT  13.008 64.716 13.032 64.8 ;
    END
  END o[412]
  PIN o[413]
    DIRECTION OUTPUT ;
    USE SIGNAL ;
    PORT
      LAYER M5 ;
        RECT  13.104 64.716 13.128 64.8 ;
    END
  END o[413]
  PIN o[414]
    DIRECTION OUTPUT ;
    USE SIGNAL ;
    PORT
      LAYER M5 ;
        RECT  13.2 64.716 13.224 64.8 ;
    END
  END o[414]
  PIN o[415]
    DIRECTION OUTPUT ;
    USE SIGNAL ;
    PORT
      LAYER M5 ;
        RECT  13.296 64.716 13.32 64.8 ;
    END
  END o[415]
  PIN o[416]
    DIRECTION OUTPUT ;
    USE SIGNAL ;
    PORT
      LAYER M5 ;
        RECT  13.392 64.716 13.416 64.8 ;
    END
  END o[416]
  PIN o[417]
    DIRECTION OUTPUT ;
    USE SIGNAL ;
    PORT
      LAYER M5 ;
        RECT  13.488 64.716 13.512 64.8 ;
    END
  END o[417]
  PIN o[418]
    DIRECTION OUTPUT ;
    USE SIGNAL ;
    PORT
      LAYER M5 ;
        RECT  13.584 64.716 13.608 64.8 ;
    END
  END o[418]
  PIN o[419]
    DIRECTION OUTPUT ;
    USE SIGNAL ;
    PORT
      LAYER M5 ;
        RECT  13.68 64.716 13.704 64.8 ;
    END
  END o[419]
  PIN o[41]
    DIRECTION OUTPUT ;
    USE SIGNAL ;
    PORT
      LAYER M5 ;
        RECT  33.456 64.716 33.48 64.8 ;
    END
  END o[41]
  PIN o[420]
    DIRECTION OUTPUT ;
    USE SIGNAL ;
    PORT
      LAYER M5 ;
        RECT  13.776 64.716 13.8 64.8 ;
    END
  END o[420]
  PIN o[421]
    DIRECTION OUTPUT ;
    USE SIGNAL ;
    PORT
      LAYER M5 ;
        RECT  13.872 64.716 13.896 64.8 ;
    END
  END o[421]
  PIN o[422]
    DIRECTION OUTPUT ;
    USE SIGNAL ;
    PORT
      LAYER M5 ;
        RECT  13.968 64.716 13.992 64.8 ;
    END
  END o[422]
  PIN o[423]
    DIRECTION OUTPUT ;
    USE SIGNAL ;
    PORT
      LAYER M5 ;
        RECT  14.064 64.716 14.088 64.8 ;
    END
  END o[423]
  PIN o[424]
    DIRECTION OUTPUT ;
    USE SIGNAL ;
    PORT
      LAYER M5 ;
        RECT  14.16 64.716 14.184 64.8 ;
    END
  END o[424]
  PIN o[425]
    DIRECTION OUTPUT ;
    USE SIGNAL ;
    PORT
      LAYER M5 ;
        RECT  14.256 64.716 14.28 64.8 ;
    END
  END o[425]
  PIN o[426]
    DIRECTION OUTPUT ;
    USE SIGNAL ;
    PORT
      LAYER M5 ;
        RECT  14.352 64.716 14.376 64.8 ;
    END
  END o[426]
  PIN o[427]
    DIRECTION OUTPUT ;
    USE SIGNAL ;
    PORT
      LAYER M5 ;
        RECT  14.448 64.716 14.472 64.8 ;
    END
  END o[427]
  PIN o[428]
    DIRECTION OUTPUT ;
    USE SIGNAL ;
    PORT
      LAYER M5 ;
        RECT  14.544 64.716 14.568 64.8 ;
    END
  END o[428]
  PIN o[429]
    DIRECTION OUTPUT ;
    USE SIGNAL ;
    PORT
      LAYER M5 ;
        RECT  14.64 64.716 14.664 64.8 ;
    END
  END o[429]
  PIN o[42]
    DIRECTION OUTPUT ;
    USE SIGNAL ;
    PORT
      LAYER M5 ;
        RECT  33.552 64.716 33.576 64.8 ;
    END
  END o[42]
  PIN o[430]
    DIRECTION OUTPUT ;
    USE SIGNAL ;
    PORT
      LAYER M5 ;
        RECT  14.736 64.716 14.76 64.8 ;
    END
  END o[430]
  PIN o[431]
    DIRECTION OUTPUT ;
    USE SIGNAL ;
    PORT
      LAYER M5 ;
        RECT  14.832 64.716 14.856 64.8 ;
    END
  END o[431]
  PIN o[432]
    DIRECTION OUTPUT ;
    USE SIGNAL ;
    PORT
      LAYER M5 ;
        RECT  14.928 64.716 14.952 64.8 ;
    END
  END o[432]
  PIN o[433]
    DIRECTION OUTPUT ;
    USE SIGNAL ;
    PORT
      LAYER M5 ;
        RECT  15.024 64.716 15.048 64.8 ;
    END
  END o[433]
  PIN o[434]
    DIRECTION OUTPUT ;
    USE SIGNAL ;
    PORT
      LAYER M5 ;
        RECT  15.12 64.716 15.144 64.8 ;
    END
  END o[434]
  PIN o[435]
    DIRECTION OUTPUT ;
    USE SIGNAL ;
    PORT
      LAYER M5 ;
        RECT  15.216 64.716 15.24 64.8 ;
    END
  END o[435]
  PIN o[436]
    DIRECTION OUTPUT ;
    USE SIGNAL ;
    PORT
      LAYER M5 ;
        RECT  15.312 64.716 15.336 64.8 ;
    END
  END o[436]
  PIN o[437]
    DIRECTION OUTPUT ;
    USE SIGNAL ;
    PORT
      LAYER M5 ;
        RECT  15.408 64.716 15.432 64.8 ;
    END
  END o[437]
  PIN o[438]
    DIRECTION OUTPUT ;
    USE SIGNAL ;
    PORT
      LAYER M5 ;
        RECT  15.504 64.716 15.528 64.8 ;
    END
  END o[438]
  PIN o[439]
    DIRECTION OUTPUT ;
    USE SIGNAL ;
    PORT
      LAYER M5 ;
        RECT  15.6 64.716 15.624 64.8 ;
    END
  END o[439]
  PIN o[43]
    DIRECTION OUTPUT ;
    USE SIGNAL ;
    PORT
      LAYER M5 ;
        RECT  33.648 64.716 33.672 64.8 ;
    END
  END o[43]
  PIN o[440]
    DIRECTION OUTPUT ;
    USE SIGNAL ;
    PORT
      LAYER M5 ;
        RECT  15.696 64.716 15.72 64.8 ;
    END
  END o[440]
  PIN o[441]
    DIRECTION OUTPUT ;
    USE SIGNAL ;
    PORT
      LAYER M5 ;
        RECT  15.792 64.716 15.816 64.8 ;
    END
  END o[441]
  PIN o[442]
    DIRECTION OUTPUT ;
    USE SIGNAL ;
    PORT
      LAYER M5 ;
        RECT  15.888 64.716 15.912 64.8 ;
    END
  END o[442]
  PIN o[443]
    DIRECTION OUTPUT ;
    USE SIGNAL ;
    PORT
      LAYER M5 ;
        RECT  15.984 64.716 16.008 64.8 ;
    END
  END o[443]
  PIN o[444]
    DIRECTION OUTPUT ;
    USE SIGNAL ;
    PORT
      LAYER M5 ;
        RECT  16.08 64.716 16.104 64.8 ;
    END
  END o[444]
  PIN o[445]
    DIRECTION OUTPUT ;
    USE SIGNAL ;
    PORT
      LAYER M5 ;
        RECT  16.176 64.716 16.2 64.8 ;
    END
  END o[445]
  PIN o[446]
    DIRECTION OUTPUT ;
    USE SIGNAL ;
    PORT
      LAYER M5 ;
        RECT  16.272 64.716 16.296 64.8 ;
    END
  END o[446]
  PIN o[447]
    DIRECTION OUTPUT ;
    USE SIGNAL ;
    PORT
      LAYER M5 ;
        RECT  16.368 64.716 16.392 64.8 ;
    END
  END o[447]
  PIN o[448]
    DIRECTION OUTPUT ;
    USE SIGNAL ;
    PORT
      LAYER M5 ;
        RECT  3.408 64.716 3.432 64.8 ;
    END
  END o[448]
  PIN o[449]
    DIRECTION OUTPUT ;
    USE SIGNAL ;
    PORT
      LAYER M5 ;
        RECT  3.504 64.716 3.528 64.8 ;
    END
  END o[449]
  PIN o[44]
    DIRECTION OUTPUT ;
    USE SIGNAL ;
    PORT
      LAYER M5 ;
        RECT  33.744 64.716 33.768 64.8 ;
    END
  END o[44]
  PIN o[450]
    DIRECTION OUTPUT ;
    USE SIGNAL ;
    PORT
      LAYER M5 ;
        RECT  3.6 64.716 3.624 64.8 ;
    END
  END o[450]
  PIN o[451]
    DIRECTION OUTPUT ;
    USE SIGNAL ;
    PORT
      LAYER M5 ;
        RECT  3.696 64.716 3.72 64.8 ;
    END
  END o[451]
  PIN o[452]
    DIRECTION OUTPUT ;
    USE SIGNAL ;
    PORT
      LAYER M5 ;
        RECT  3.792 64.716 3.816 64.8 ;
    END
  END o[452]
  PIN o[453]
    DIRECTION OUTPUT ;
    USE SIGNAL ;
    PORT
      LAYER M5 ;
        RECT  3.888 64.716 3.912 64.8 ;
    END
  END o[453]
  PIN o[454]
    DIRECTION OUTPUT ;
    USE SIGNAL ;
    PORT
      LAYER M5 ;
        RECT  3.984 64.716 4.008 64.8 ;
    END
  END o[454]
  PIN o[455]
    DIRECTION OUTPUT ;
    USE SIGNAL ;
    PORT
      LAYER M5 ;
        RECT  4.08 64.716 4.104 64.8 ;
    END
  END o[455]
  PIN o[456]
    DIRECTION OUTPUT ;
    USE SIGNAL ;
    PORT
      LAYER M5 ;
        RECT  4.176 64.716 4.2 64.8 ;
    END
  END o[456]
  PIN o[457]
    DIRECTION OUTPUT ;
    USE SIGNAL ;
    PORT
      LAYER M5 ;
        RECT  4.272 64.716 4.296 64.8 ;
    END
  END o[457]
  PIN o[458]
    DIRECTION OUTPUT ;
    USE SIGNAL ;
    PORT
      LAYER M5 ;
        RECT  4.368 64.716 4.392 64.8 ;
    END
  END o[458]
  PIN o[459]
    DIRECTION OUTPUT ;
    USE SIGNAL ;
    PORT
      LAYER M5 ;
        RECT  4.464 64.716 4.488 64.8 ;
    END
  END o[459]
  PIN o[45]
    DIRECTION OUTPUT ;
    USE SIGNAL ;
    PORT
      LAYER M5 ;
        RECT  33.84 64.716 33.864 64.8 ;
    END
  END o[45]
  PIN o[460]
    DIRECTION OUTPUT ;
    USE SIGNAL ;
    PORT
      LAYER M5 ;
        RECT  4.56 64.716 4.584 64.8 ;
    END
  END o[460]
  PIN o[461]
    DIRECTION OUTPUT ;
    USE SIGNAL ;
    PORT
      LAYER M5 ;
        RECT  4.656 64.716 4.68 64.8 ;
    END
  END o[461]
  PIN o[462]
    DIRECTION OUTPUT ;
    USE SIGNAL ;
    PORT
      LAYER M5 ;
        RECT  4.752 64.716 4.776 64.8 ;
    END
  END o[462]
  PIN o[463]
    DIRECTION OUTPUT ;
    USE SIGNAL ;
    PORT
      LAYER M5 ;
        RECT  4.848 64.716 4.872 64.8 ;
    END
  END o[463]
  PIN o[464]
    DIRECTION OUTPUT ;
    USE SIGNAL ;
    PORT
      LAYER M5 ;
        RECT  4.944 64.716 4.968 64.8 ;
    END
  END o[464]
  PIN o[465]
    DIRECTION OUTPUT ;
    USE SIGNAL ;
    PORT
      LAYER M5 ;
        RECT  5.04 64.716 5.064 64.8 ;
    END
  END o[465]
  PIN o[466]
    DIRECTION OUTPUT ;
    USE SIGNAL ;
    PORT
      LAYER M5 ;
        RECT  5.136 64.716 5.16 64.8 ;
    END
  END o[466]
  PIN o[467]
    DIRECTION OUTPUT ;
    USE SIGNAL ;
    PORT
      LAYER M5 ;
        RECT  5.232 64.716 5.256 64.8 ;
    END
  END o[467]
  PIN o[468]
    DIRECTION OUTPUT ;
    USE SIGNAL ;
    PORT
      LAYER M5 ;
        RECT  5.328 64.716 5.352 64.8 ;
    END
  END o[468]
  PIN o[469]
    DIRECTION OUTPUT ;
    USE SIGNAL ;
    PORT
      LAYER M5 ;
        RECT  5.424 64.716 5.448 64.8 ;
    END
  END o[469]
  PIN o[46]
    DIRECTION OUTPUT ;
    USE SIGNAL ;
    PORT
      LAYER M5 ;
        RECT  33.936 64.716 33.96 64.8 ;
    END
  END o[46]
  PIN o[470]
    DIRECTION OUTPUT ;
    USE SIGNAL ;
    PORT
      LAYER M5 ;
        RECT  5.52 64.716 5.544 64.8 ;
    END
  END o[470]
  PIN o[471]
    DIRECTION OUTPUT ;
    USE SIGNAL ;
    PORT
      LAYER M5 ;
        RECT  5.616 64.716 5.64 64.8 ;
    END
  END o[471]
  PIN o[472]
    DIRECTION OUTPUT ;
    USE SIGNAL ;
    PORT
      LAYER M5 ;
        RECT  5.712 64.716 5.736 64.8 ;
    END
  END o[472]
  PIN o[473]
    DIRECTION OUTPUT ;
    USE SIGNAL ;
    PORT
      LAYER M5 ;
        RECT  5.808 64.716 5.832 64.8 ;
    END
  END o[473]
  PIN o[474]
    DIRECTION OUTPUT ;
    USE SIGNAL ;
    PORT
      LAYER M5 ;
        RECT  5.904 64.716 5.928 64.8 ;
    END
  END o[474]
  PIN o[475]
    DIRECTION OUTPUT ;
    USE SIGNAL ;
    PORT
      LAYER M5 ;
        RECT  6 64.716 6.024 64.8 ;
    END
  END o[475]
  PIN o[476]
    DIRECTION OUTPUT ;
    USE SIGNAL ;
    PORT
      LAYER M5 ;
        RECT  6.096 64.716 6.12 64.8 ;
    END
  END o[476]
  PIN o[477]
    DIRECTION OUTPUT ;
    USE SIGNAL ;
    PORT
      LAYER M5 ;
        RECT  6.192 64.716 6.216 64.8 ;
    END
  END o[477]
  PIN o[478]
    DIRECTION OUTPUT ;
    USE SIGNAL ;
    PORT
      LAYER M5 ;
        RECT  6.288 64.716 6.312 64.8 ;
    END
  END o[478]
  PIN o[479]
    DIRECTION OUTPUT ;
    USE SIGNAL ;
    PORT
      LAYER M5 ;
        RECT  6.384 64.716 6.408 64.8 ;
    END
  END o[479]
  PIN o[47]
    DIRECTION OUTPUT ;
    USE SIGNAL ;
    PORT
      LAYER M5 ;
        RECT  34.032 64.716 34.056 64.8 ;
    END
  END o[47]
  PIN o[480]
    DIRECTION OUTPUT ;
    USE SIGNAL ;
    PORT
      LAYER M5 ;
        RECT  16.464 64.716 16.488 64.8 ;
    END
  END o[480]
  PIN o[481]
    DIRECTION OUTPUT ;
    USE SIGNAL ;
    PORT
      LAYER M5 ;
        RECT  16.56 64.716 16.584 64.8 ;
    END
  END o[481]
  PIN o[482]
    DIRECTION OUTPUT ;
    USE SIGNAL ;
    PORT
      LAYER M5 ;
        RECT  16.656 64.716 16.68 64.8 ;
    END
  END o[482]
  PIN o[483]
    DIRECTION OUTPUT ;
    USE SIGNAL ;
    PORT
      LAYER M5 ;
        RECT  16.752 64.716 16.776 64.8 ;
    END
  END o[483]
  PIN o[484]
    DIRECTION OUTPUT ;
    USE SIGNAL ;
    PORT
      LAYER M5 ;
        RECT  16.848 64.716 16.872 64.8 ;
    END
  END o[484]
  PIN o[485]
    DIRECTION OUTPUT ;
    USE SIGNAL ;
    PORT
      LAYER M5 ;
        RECT  16.944 64.716 16.968 64.8 ;
    END
  END o[485]
  PIN o[486]
    DIRECTION OUTPUT ;
    USE SIGNAL ;
    PORT
      LAYER M5 ;
        RECT  17.04 64.716 17.064 64.8 ;
    END
  END o[486]
  PIN o[487]
    DIRECTION OUTPUT ;
    USE SIGNAL ;
    PORT
      LAYER M5 ;
        RECT  17.136 64.716 17.16 64.8 ;
    END
  END o[487]
  PIN o[488]
    DIRECTION OUTPUT ;
    USE SIGNAL ;
    PORT
      LAYER M5 ;
        RECT  17.232 64.716 17.256 64.8 ;
    END
  END o[488]
  PIN o[489]
    DIRECTION OUTPUT ;
    USE SIGNAL ;
    PORT
      LAYER M5 ;
        RECT  17.328 64.716 17.352 64.8 ;
    END
  END o[489]
  PIN o[48]
    DIRECTION OUTPUT ;
    USE SIGNAL ;
    PORT
      LAYER M5 ;
        RECT  34.128 64.716 34.152 64.8 ;
    END
  END o[48]
  PIN o[490]
    DIRECTION OUTPUT ;
    USE SIGNAL ;
    PORT
      LAYER M5 ;
        RECT  17.424 64.716 17.448 64.8 ;
    END
  END o[490]
  PIN o[491]
    DIRECTION OUTPUT ;
    USE SIGNAL ;
    PORT
      LAYER M5 ;
        RECT  17.52 64.716 17.544 64.8 ;
    END
  END o[491]
  PIN o[492]
    DIRECTION OUTPUT ;
    USE SIGNAL ;
    PORT
      LAYER M5 ;
        RECT  17.616 64.716 17.64 64.8 ;
    END
  END o[492]
  PIN o[493]
    DIRECTION OUTPUT ;
    USE SIGNAL ;
    PORT
      LAYER M5 ;
        RECT  17.712 64.716 17.736 64.8 ;
    END
  END o[493]
  PIN o[494]
    DIRECTION OUTPUT ;
    USE SIGNAL ;
    PORT
      LAYER M5 ;
        RECT  17.808 64.716 17.832 64.8 ;
    END
  END o[494]
  PIN o[495]
    DIRECTION OUTPUT ;
    USE SIGNAL ;
    PORT
      LAYER M5 ;
        RECT  17.904 64.716 17.928 64.8 ;
    END
  END o[495]
  PIN o[496]
    DIRECTION OUTPUT ;
    USE SIGNAL ;
    PORT
      LAYER M5 ;
        RECT  18 64.716 18.024 64.8 ;
    END
  END o[496]
  PIN o[497]
    DIRECTION OUTPUT ;
    USE SIGNAL ;
    PORT
      LAYER M5 ;
        RECT  18.096 64.716 18.12 64.8 ;
    END
  END o[497]
  PIN o[498]
    DIRECTION OUTPUT ;
    USE SIGNAL ;
    PORT
      LAYER M5 ;
        RECT  18.192 64.716 18.216 64.8 ;
    END
  END o[498]
  PIN o[499]
    DIRECTION OUTPUT ;
    USE SIGNAL ;
    PORT
      LAYER M5 ;
        RECT  18.288 64.716 18.312 64.8 ;
    END
  END o[499]
  PIN o[49]
    DIRECTION OUTPUT ;
    USE SIGNAL ;
    PORT
      LAYER M5 ;
        RECT  34.224 64.716 34.248 64.8 ;
    END
  END o[49]
  PIN o[4]
    DIRECTION OUTPUT ;
    USE SIGNAL ;
    PORT
      LAYER M5 ;
        RECT  26.832 64.716 26.856 64.8 ;
    END
  END o[4]
  PIN o[500]
    DIRECTION OUTPUT ;
    USE SIGNAL ;
    PORT
      LAYER M5 ;
        RECT  18.384 64.716 18.408 64.8 ;
    END
  END o[500]
  PIN o[501]
    DIRECTION OUTPUT ;
    USE SIGNAL ;
    PORT
      LAYER M5 ;
        RECT  18.48 64.716 18.504 64.8 ;
    END
  END o[501]
  PIN o[502]
    DIRECTION OUTPUT ;
    USE SIGNAL ;
    PORT
      LAYER M5 ;
        RECT  18.576 64.716 18.6 64.8 ;
    END
  END o[502]
  PIN o[503]
    DIRECTION OUTPUT ;
    USE SIGNAL ;
    PORT
      LAYER M5 ;
        RECT  18.672 64.716 18.696 64.8 ;
    END
  END o[503]
  PIN o[504]
    DIRECTION OUTPUT ;
    USE SIGNAL ;
    PORT
      LAYER M5 ;
        RECT  18.768 64.716 18.792 64.8 ;
    END
  END o[504]
  PIN o[505]
    DIRECTION OUTPUT ;
    USE SIGNAL ;
    PORT
      LAYER M5 ;
        RECT  18.864 64.716 18.888 64.8 ;
    END
  END o[505]
  PIN o[506]
    DIRECTION OUTPUT ;
    USE SIGNAL ;
    PORT
      LAYER M5 ;
        RECT  18.96 64.716 18.984 64.8 ;
    END
  END o[506]
  PIN o[507]
    DIRECTION OUTPUT ;
    USE SIGNAL ;
    PORT
      LAYER M5 ;
        RECT  19.056 64.716 19.08 64.8 ;
    END
  END o[507]
  PIN o[508]
    DIRECTION OUTPUT ;
    USE SIGNAL ;
    PORT
      LAYER M5 ;
        RECT  19.152 64.716 19.176 64.8 ;
    END
  END o[508]
  PIN o[509]
    DIRECTION OUTPUT ;
    USE SIGNAL ;
    PORT
      LAYER M5 ;
        RECT  19.248 64.716 19.272 64.8 ;
    END
  END o[509]
  PIN o[50]
    DIRECTION OUTPUT ;
    USE SIGNAL ;
    PORT
      LAYER M5 ;
        RECT  34.32 64.716 34.344 64.8 ;
    END
  END o[50]
  PIN o[510]
    DIRECTION OUTPUT ;
    USE SIGNAL ;
    PORT
      LAYER M5 ;
        RECT  19.344 64.716 19.368 64.8 ;
    END
  END o[510]
  PIN o[511]
    DIRECTION OUTPUT ;
    USE SIGNAL ;
    PORT
      LAYER M5 ;
        RECT  19.44 64.716 19.464 64.8 ;
    END
  END o[511]
  PIN o[512]
    DIRECTION OUTPUT ;
    USE SIGNAL ;
    PORT
      LAYER M5 ;
        RECT  25.872 64.716 25.896 64.8 ;
    END
  END o[512]
  PIN o[513]
    DIRECTION OUTPUT ;
    USE SIGNAL ;
    PORT
      LAYER M5 ;
        RECT  25.968 64.716 25.992 64.8 ;
    END
  END o[513]
  PIN o[514]
    DIRECTION OUTPUT ;
    USE SIGNAL ;
    PORT
      LAYER M5 ;
        RECT  26.064 64.716 26.088 64.8 ;
    END
  END o[514]
  PIN o[51]
    DIRECTION OUTPUT ;
    USE SIGNAL ;
    PORT
      LAYER M5 ;
        RECT  34.416 64.716 34.44 64.8 ;
    END
  END o[51]
  PIN o[52]
    DIRECTION OUTPUT ;
    USE SIGNAL ;
    PORT
      LAYER M5 ;
        RECT  34.512 64.716 34.536 64.8 ;
    END
  END o[52]
  PIN o[53]
    DIRECTION OUTPUT ;
    USE SIGNAL ;
    PORT
      LAYER M5 ;
        RECT  34.608 64.716 34.632 64.8 ;
    END
  END o[53]
  PIN o[54]
    DIRECTION OUTPUT ;
    USE SIGNAL ;
    PORT
      LAYER M5 ;
        RECT  34.704 64.716 34.728 64.8 ;
    END
  END o[54]
  PIN o[55]
    DIRECTION OUTPUT ;
    USE SIGNAL ;
    PORT
      LAYER M5 ;
        RECT  34.8 64.716 34.824 64.8 ;
    END
  END o[55]
  PIN o[56]
    DIRECTION OUTPUT ;
    USE SIGNAL ;
    PORT
      LAYER M5 ;
        RECT  34.896 64.716 34.92 64.8 ;
    END
  END o[56]
  PIN o[57]
    DIRECTION OUTPUT ;
    USE SIGNAL ;
    PORT
      LAYER M5 ;
        RECT  34.992 64.716 35.016 64.8 ;
    END
  END o[57]
  PIN o[58]
    DIRECTION OUTPUT ;
    USE SIGNAL ;
    PORT
      LAYER M5 ;
        RECT  35.088 64.716 35.112 64.8 ;
    END
  END o[58]
  PIN o[59]
    DIRECTION OUTPUT ;
    USE SIGNAL ;
    PORT
      LAYER M5 ;
        RECT  35.184 64.716 35.208 64.8 ;
    END
  END o[59]
  PIN o[5]
    DIRECTION OUTPUT ;
    USE SIGNAL ;
    PORT
      LAYER M5 ;
        RECT  26.928 64.716 26.952 64.8 ;
    END
  END o[5]
  PIN o[60]
    DIRECTION OUTPUT ;
    USE SIGNAL ;
    PORT
      LAYER M5 ;
        RECT  35.28 64.716 35.304 64.8 ;
    END
  END o[60]
  PIN o[61]
    DIRECTION OUTPUT ;
    USE SIGNAL ;
    PORT
      LAYER M5 ;
        RECT  35.376 64.716 35.4 64.8 ;
    END
  END o[61]
  PIN o[62]
    DIRECTION OUTPUT ;
    USE SIGNAL ;
    PORT
      LAYER M5 ;
        RECT  35.472 64.716 35.496 64.8 ;
    END
  END o[62]
  PIN o[63]
    DIRECTION OUTPUT ;
    USE SIGNAL ;
    PORT
      LAYER M5 ;
        RECT  35.568 64.716 35.592 64.8 ;
    END
  END o[63]
  PIN o[64]
    DIRECTION OUTPUT ;
    USE SIGNAL ;
    PORT
      LAYER M5 ;
        RECT  45.648 64.716 45.672 64.8 ;
    END
  END o[64]
  PIN o[65]
    DIRECTION OUTPUT ;
    USE SIGNAL ;
    PORT
      LAYER M5 ;
        RECT  45.744 64.716 45.768 64.8 ;
    END
  END o[65]
  PIN o[66]
    DIRECTION OUTPUT ;
    USE SIGNAL ;
    PORT
      LAYER M5 ;
        RECT  45.84 64.716 45.864 64.8 ;
    END
  END o[66]
  PIN o[67]
    DIRECTION OUTPUT ;
    USE SIGNAL ;
    PORT
      LAYER M5 ;
        RECT  45.936 64.716 45.96 64.8 ;
    END
  END o[67]
  PIN o[68]
    DIRECTION OUTPUT ;
    USE SIGNAL ;
    PORT
      LAYER M5 ;
        RECT  46.032 64.716 46.056 64.8 ;
    END
  END o[68]
  PIN o[69]
    DIRECTION OUTPUT ;
    USE SIGNAL ;
    PORT
      LAYER M5 ;
        RECT  46.128 64.716 46.152 64.8 ;
    END
  END o[69]
  PIN o[6]
    DIRECTION OUTPUT ;
    USE SIGNAL ;
    PORT
      LAYER M5 ;
        RECT  27.024 64.716 27.048 64.8 ;
    END
  END o[6]
  PIN o[70]
    DIRECTION OUTPUT ;
    USE SIGNAL ;
    PORT
      LAYER M5 ;
        RECT  46.224 64.716 46.248 64.8 ;
    END
  END o[70]
  PIN o[71]
    DIRECTION OUTPUT ;
    USE SIGNAL ;
    PORT
      LAYER M5 ;
        RECT  46.32 64.716 46.344 64.8 ;
    END
  END o[71]
  PIN o[72]
    DIRECTION OUTPUT ;
    USE SIGNAL ;
    PORT
      LAYER M5 ;
        RECT  46.416 64.716 46.44 64.8 ;
    END
  END o[72]
  PIN o[73]
    DIRECTION OUTPUT ;
    USE SIGNAL ;
    PORT
      LAYER M5 ;
        RECT  46.512 64.716 46.536 64.8 ;
    END
  END o[73]
  PIN o[74]
    DIRECTION OUTPUT ;
    USE SIGNAL ;
    PORT
      LAYER M5 ;
        RECT  46.608 64.716 46.632 64.8 ;
    END
  END o[74]
  PIN o[75]
    DIRECTION OUTPUT ;
    USE SIGNAL ;
    PORT
      LAYER M5 ;
        RECT  46.704 64.716 46.728 64.8 ;
    END
  END o[75]
  PIN o[76]
    DIRECTION OUTPUT ;
    USE SIGNAL ;
    PORT
      LAYER M5 ;
        RECT  46.8 64.716 46.824 64.8 ;
    END
  END o[76]
  PIN o[77]
    DIRECTION OUTPUT ;
    USE SIGNAL ;
    PORT
      LAYER M5 ;
        RECT  46.896 64.716 46.92 64.8 ;
    END
  END o[77]
  PIN o[78]
    DIRECTION OUTPUT ;
    USE SIGNAL ;
    PORT
      LAYER M5 ;
        RECT  46.992 64.716 47.016 64.8 ;
    END
  END o[78]
  PIN o[79]
    DIRECTION OUTPUT ;
    USE SIGNAL ;
    PORT
      LAYER M5 ;
        RECT  47.088 64.716 47.112 64.8 ;
    END
  END o[79]
  PIN o[7]
    DIRECTION OUTPUT ;
    USE SIGNAL ;
    PORT
      LAYER M5 ;
        RECT  27.12 64.716 27.144 64.8 ;
    END
  END o[7]
  PIN o[80]
    DIRECTION OUTPUT ;
    USE SIGNAL ;
    PORT
      LAYER M5 ;
        RECT  47.184 64.716 47.208 64.8 ;
    END
  END o[80]
  PIN o[81]
    DIRECTION OUTPUT ;
    USE SIGNAL ;
    PORT
      LAYER M5 ;
        RECT  47.28 64.716 47.304 64.8 ;
    END
  END o[81]
  PIN o[82]
    DIRECTION OUTPUT ;
    USE SIGNAL ;
    PORT
      LAYER M5 ;
        RECT  47.376 64.716 47.4 64.8 ;
    END
  END o[82]
  PIN o[83]
    DIRECTION OUTPUT ;
    USE SIGNAL ;
    PORT
      LAYER M5 ;
        RECT  47.472 64.716 47.496 64.8 ;
    END
  END o[83]
  PIN o[84]
    DIRECTION OUTPUT ;
    USE SIGNAL ;
    PORT
      LAYER M5 ;
        RECT  47.568 64.716 47.592 64.8 ;
    END
  END o[84]
  PIN o[85]
    DIRECTION OUTPUT ;
    USE SIGNAL ;
    PORT
      LAYER M5 ;
        RECT  47.664 64.716 47.688 64.8 ;
    END
  END o[85]
  PIN o[86]
    DIRECTION OUTPUT ;
    USE SIGNAL ;
    PORT
      LAYER M5 ;
        RECT  47.76 64.716 47.784 64.8 ;
    END
  END o[86]
  PIN o[87]
    DIRECTION OUTPUT ;
    USE SIGNAL ;
    PORT
      LAYER M5 ;
        RECT  47.856 64.716 47.88 64.8 ;
    END
  END o[87]
  PIN o[88]
    DIRECTION OUTPUT ;
    USE SIGNAL ;
    PORT
      LAYER M5 ;
        RECT  47.952 64.716 47.976 64.8 ;
    END
  END o[88]
  PIN o[89]
    DIRECTION OUTPUT ;
    USE SIGNAL ;
    PORT
      LAYER M5 ;
        RECT  48.048 64.716 48.072 64.8 ;
    END
  END o[89]
  PIN o[8]
    DIRECTION OUTPUT ;
    USE SIGNAL ;
    PORT
      LAYER M5 ;
        RECT  27.216 64.716 27.24 64.8 ;
    END
  END o[8]
  PIN o[90]
    DIRECTION OUTPUT ;
    USE SIGNAL ;
    PORT
      LAYER M5 ;
        RECT  48.144 64.716 48.168 64.8 ;
    END
  END o[90]
  PIN o[91]
    DIRECTION OUTPUT ;
    USE SIGNAL ;
    PORT
      LAYER M5 ;
        RECT  48.24 64.716 48.264 64.8 ;
    END
  END o[91]
  PIN o[92]
    DIRECTION OUTPUT ;
    USE SIGNAL ;
    PORT
      LAYER M5 ;
        RECT  48.336 64.716 48.36 64.8 ;
    END
  END o[92]
  PIN o[93]
    DIRECTION OUTPUT ;
    USE SIGNAL ;
    PORT
      LAYER M5 ;
        RECT  48.432 64.716 48.456 64.8 ;
    END
  END o[93]
  PIN o[94]
    DIRECTION OUTPUT ;
    USE SIGNAL ;
    PORT
      LAYER M5 ;
        RECT  48.528 64.716 48.552 64.8 ;
    END
  END o[94]
  PIN o[95]
    DIRECTION OUTPUT ;
    USE SIGNAL ;
    PORT
      LAYER M5 ;
        RECT  48.624 64.716 48.648 64.8 ;
    END
  END o[95]
  PIN o[96]
    DIRECTION OUTPUT ;
    USE SIGNAL ;
    PORT
      LAYER M5 ;
        RECT  57.936 64.716 57.96 64.8 ;
    END
  END o[96]
  PIN o[97]
    DIRECTION OUTPUT ;
    USE SIGNAL ;
    PORT
      LAYER M5 ;
        RECT  58.032 64.716 58.056 64.8 ;
    END
  END o[97]
  PIN o[98]
    DIRECTION OUTPUT ;
    USE SIGNAL ;
    PORT
      LAYER M5 ;
        RECT  58.128 64.716 58.152 64.8 ;
    END
  END o[98]
  PIN o[99]
    DIRECTION OUTPUT ;
    USE SIGNAL ;
    PORT
      LAYER M5 ;
        RECT  58.224 64.716 58.248 64.8 ;
    END
  END o[99]
  PIN o[9]
    DIRECTION OUTPUT ;
    USE SIGNAL ;
    PORT
      LAYER M5 ;
        RECT  27.312 64.716 27.336 64.8 ;
    END
  END o[9]
  PIN rs[0]
    DIRECTION INPUT ;
    USE SIGNAL ;
    PORT
      LAYER M5 ;
        RECT  25.584 0 25.608 0.084 ;
    END
  END rs[0]
  PIN VDD
    DIRECTION INOUT ;
    USE POWER ;
    PORT
      LAYER M5 ;
        RECT  61.992 2.151 62.112 62.649 ;
        RECT  56.592 2.151 56.712 62.649 ;
        RECT  51.192 2.151 51.312 62.649 ;
        RECT  45.792 2.151 45.912 62.649 ;
        RECT  40.392 2.151 40.512 62.649 ;
        RECT  34.992 2.151 35.112 62.649 ;
        RECT  29.592 2.151 29.712 62.649 ;
        RECT  24.192 2.151 24.312 62.649 ;
        RECT  18.792 2.151 18.912 62.649 ;
        RECT  13.392 2.151 13.512 62.649 ;
        RECT  7.992 2.151 8.112 62.649 ;
        RECT  2.592 2.151 2.712 62.649 ;
    END
  END VDD
  PIN VSS
    DIRECTION INOUT ;
    USE GROUND ;
    PORT
      LAYER M5 ;
        RECT  61.8 2.137 61.92 62.663 ;
        RECT  56.4 2.137 56.52 62.663 ;
        RECT  51 2.137 51.12 62.663 ;
        RECT  45.6 2.137 45.72 62.663 ;
        RECT  40.2 2.137 40.32 62.663 ;
        RECT  34.8 2.137 34.92 62.663 ;
        RECT  29.4 2.137 29.52 62.663 ;
        RECT  24 2.137 24.12 62.663 ;
        RECT  18.6 2.137 18.72 62.663 ;
        RECT  13.2 2.137 13.32 62.663 ;
        RECT  7.8 2.137 7.92 62.663 ;
        RECT  2.4 2.137 2.52 62.663 ;
    END
  END VSS
  OBS
    LAYER RVTN ;
     RECT  2.16 2.16 62.64 2.295 ;
     RECT  2.16 2.565 62.64 2.835 ;
     RECT  2.16 3.105 62.64 3.375 ;
     RECT  2.16 3.645 62.64 3.915 ;
     RECT  2.16 4.185 62.64 4.455 ;
     RECT  2.16 4.725 62.64 4.995 ;
     RECT  2.16 5.265 62.64 5.535 ;
     RECT  2.16 5.805 62.64 6.075 ;
     RECT  2.16 6.345 62.64 6.615 ;
     RECT  2.16 6.885 62.64 7.155 ;
     RECT  2.16 7.425 62.64 7.695 ;
     RECT  2.16 7.965 62.64 8.235 ;
     RECT  2.16 8.505 62.64 8.775 ;
     RECT  2.16 9.045 62.64 9.315 ;
     RECT  2.16 9.585 62.64 9.855 ;
     RECT  2.16 10.125 62.64 10.395 ;
     RECT  2.16 10.665 62.64 10.935 ;
     RECT  2.16 11.205 62.64 11.475 ;
     RECT  2.16 11.745 62.64 12.015 ;
     RECT  2.16 12.285 62.64 12.555 ;
     RECT  2.16 12.825 62.64 13.095 ;
     RECT  2.16 13.365 62.64 13.635 ;
     RECT  2.16 13.905 62.64 14.175 ;
     RECT  2.16 14.445 62.64 14.715 ;
     RECT  2.16 14.985 62.64 15.255 ;
     RECT  2.16 15.525 62.64 15.795 ;
     RECT  2.16 16.065 62.64 16.335 ;
     RECT  2.16 16.605 62.64 16.875 ;
     RECT  2.16 17.145 62.64 17.415 ;
     RECT  2.16 17.685 62.64 17.955 ;
     RECT  2.16 18.225 62.64 18.495 ;
     RECT  2.16 18.765 62.64 19.035 ;
     RECT  2.16 19.305 62.64 19.575 ;
     RECT  2.16 19.845 62.64 20.115 ;
     RECT  2.16 20.385 62.64 20.655 ;
     RECT  2.16 20.925 62.64 21.195 ;
     RECT  2.16 21.465 62.64 21.735 ;
     RECT  2.16 22.005 62.64 22.275 ;
     RECT  2.16 22.545 62.64 22.815 ;
     RECT  2.16 23.085 62.64 23.355 ;
     RECT  2.16 23.625 62.64 23.895 ;
     RECT  2.16 24.165 62.64 24.435 ;
     RECT  2.16 24.705 62.64 24.975 ;
     RECT  2.16 25.245 62.64 25.515 ;
     RECT  2.16 25.785 62.64 26.055 ;
     RECT  2.16 26.325 62.64 26.595 ;
     RECT  2.16 26.865 62.64 27.135 ;
     RECT  2.16 27.405 62.64 27.675 ;
     RECT  2.16 27.945 62.64 28.215 ;
     RECT  2.16 28.485 62.64 28.755 ;
     RECT  2.16 29.025 62.64 29.295 ;
     RECT  2.16 29.565 62.64 29.835 ;
     RECT  2.16 30.105 62.64 30.375 ;
     RECT  2.16 30.645 62.64 30.915 ;
     RECT  2.16 31.185 62.64 31.455 ;
     RECT  2.16 31.725 62.64 31.995 ;
     RECT  2.16 32.265 62.64 32.535 ;
     RECT  2.16 32.805 62.64 33.075 ;
     RECT  2.16 33.345 62.64 33.615 ;
     RECT  2.16 33.885 62.64 34.155 ;
     RECT  2.16 34.425 62.64 34.695 ;
     RECT  2.16 34.965 62.64 35.235 ;
     RECT  2.16 35.505 62.64 35.775 ;
     RECT  2.16 36.045 62.64 36.315 ;
     RECT  2.16 36.585 62.64 36.855 ;
     RECT  2.16 37.125 62.64 37.395 ;
     RECT  2.16 37.665 62.64 37.935 ;
     RECT  2.16 38.205 62.64 38.475 ;
     RECT  2.16 38.745 62.64 39.015 ;
     RECT  2.16 39.285 62.64 39.555 ;
     RECT  2.16 39.825 62.64 40.095 ;
     RECT  2.16 40.365 62.64 40.635 ;
     RECT  2.16 40.905 62.64 41.175 ;
     RECT  2.16 41.445 62.64 41.715 ;
     RECT  2.16 41.985 62.64 42.255 ;
     RECT  2.16 42.525 62.64 42.795 ;
     RECT  2.16 43.065 62.64 43.335 ;
     RECT  2.16 43.605 62.64 43.875 ;
     RECT  2.16 44.145 62.64 44.415 ;
     RECT  2.16 44.685 62.64 44.955 ;
     RECT  2.16 45.225 62.64 45.495 ;
     RECT  2.16 45.765 62.64 46.035 ;
     RECT  2.16 46.305 62.64 46.575 ;
     RECT  2.16 46.845 62.64 47.115 ;
     RECT  2.16 47.385 62.64 47.655 ;
     RECT  2.16 47.925 62.64 48.195 ;
     RECT  2.16 48.465 62.64 48.735 ;
     RECT  2.16 49.005 62.64 49.275 ;
     RECT  2.16 49.545 62.64 49.815 ;
     RECT  2.16 50.085 62.64 50.355 ;
     RECT  2.16 50.625 62.64 50.895 ;
     RECT  2.16 51.165 62.64 51.435 ;
     RECT  2.16 51.705 62.64 51.975 ;
     RECT  2.16 52.245 62.64 52.515 ;
     RECT  2.16 52.785 62.64 53.055 ;
     RECT  2.16 53.325 62.64 53.595 ;
     RECT  2.16 53.865 62.64 54.135 ;
     RECT  2.16 54.405 62.64 54.675 ;
     RECT  2.16 54.945 62.64 55.215 ;
     RECT  2.16 55.485 62.64 55.755 ;
     RECT  2.16 56.025 62.64 56.295 ;
     RECT  2.16 56.565 62.64 56.835 ;
     RECT  2.16 57.105 62.64 57.375 ;
     RECT  2.16 57.645 62.64 57.915 ;
     RECT  2.16 58.185 62.64 58.455 ;
     RECT  2.16 58.725 62.64 58.995 ;
     RECT  2.16 59.265 62.64 59.535 ;
     RECT  2.16 59.805 62.64 60.075 ;
     RECT  2.16 60.345 62.64 60.615 ;
     RECT  2.16 60.885 62.64 61.155 ;
     RECT  2.16 61.425 62.64 61.695 ;
     RECT  2.16 61.965 62.64 62.235 ;
     RECT  2.16 62.505 62.64 62.64 ;
    LAYER RVTP ;
     RECT  2.16 2.295 62.64 2.565 ;
     RECT  2.16 2.835 62.64 3.105 ;
     RECT  2.16 3.375 62.64 3.645 ;
     RECT  2.16 3.915 62.64 4.185 ;
     RECT  2.16 4.455 62.64 4.725 ;
     RECT  2.16 4.995 62.64 5.265 ;
     RECT  2.16 5.535 62.64 5.805 ;
     RECT  2.16 6.075 62.64 6.345 ;
     RECT  2.16 6.615 62.64 6.885 ;
     RECT  2.16 7.155 62.64 7.425 ;
     RECT  2.16 7.695 62.64 7.965 ;
     RECT  2.16 8.235 62.64 8.505 ;
     RECT  2.16 8.775 62.64 9.045 ;
     RECT  2.16 9.315 62.64 9.585 ;
     RECT  2.16 9.855 62.64 10.125 ;
     RECT  2.16 10.395 62.64 10.665 ;
     RECT  2.16 10.935 62.64 11.205 ;
     RECT  2.16 11.475 62.64 11.745 ;
     RECT  2.16 12.015 62.64 12.285 ;
     RECT  2.16 12.555 62.64 12.825 ;
     RECT  2.16 13.095 62.64 13.365 ;
     RECT  2.16 13.635 62.64 13.905 ;
     RECT  2.16 14.175 62.64 14.445 ;
     RECT  2.16 14.715 62.64 14.985 ;
     RECT  2.16 15.255 62.64 15.525 ;
     RECT  2.16 15.795 62.64 16.065 ;
     RECT  2.16 16.335 62.64 16.605 ;
     RECT  2.16 16.875 62.64 17.145 ;
     RECT  2.16 17.415 62.64 17.685 ;
     RECT  2.16 17.955 62.64 18.225 ;
     RECT  2.16 18.495 62.64 18.765 ;
     RECT  2.16 19.035 62.64 19.305 ;
     RECT  2.16 19.575 62.64 19.845 ;
     RECT  2.16 20.115 62.64 20.385 ;
     RECT  2.16 20.655 62.64 20.925 ;
     RECT  2.16 21.195 62.64 21.465 ;
     RECT  2.16 21.735 62.64 22.005 ;
     RECT  2.16 22.275 62.64 22.545 ;
     RECT  2.16 22.815 62.64 23.085 ;
     RECT  2.16 23.355 62.64 23.625 ;
     RECT  2.16 23.895 62.64 24.165 ;
     RECT  2.16 24.435 62.64 24.705 ;
     RECT  2.16 24.975 62.64 25.245 ;
     RECT  2.16 25.515 62.64 25.785 ;
     RECT  2.16 26.055 62.64 26.325 ;
     RECT  2.16 26.595 62.64 26.865 ;
     RECT  2.16 27.135 62.64 27.405 ;
     RECT  2.16 27.675 62.64 27.945 ;
     RECT  2.16 28.215 62.64 28.485 ;
     RECT  2.16 28.755 62.64 29.025 ;
     RECT  2.16 29.295 62.64 29.565 ;
     RECT  2.16 29.835 62.64 30.105 ;
     RECT  2.16 30.375 62.64 30.645 ;
     RECT  2.16 30.915 62.64 31.185 ;
     RECT  2.16 31.455 62.64 31.725 ;
     RECT  2.16 31.995 62.64 32.265 ;
     RECT  2.16 32.535 62.64 32.805 ;
     RECT  2.16 33.075 62.64 33.345 ;
     RECT  2.16 33.615 62.64 33.885 ;
     RECT  2.16 34.155 62.64 34.425 ;
     RECT  2.16 34.695 62.64 34.965 ;
     RECT  2.16 35.235 62.64 35.505 ;
     RECT  2.16 35.775 62.64 36.045 ;
     RECT  2.16 36.315 62.64 36.585 ;
     RECT  2.16 36.855 62.64 37.125 ;
     RECT  2.16 37.395 62.64 37.665 ;
     RECT  2.16 37.935 62.64 38.205 ;
     RECT  2.16 38.475 62.64 38.745 ;
     RECT  2.16 39.015 62.64 39.285 ;
     RECT  2.16 39.555 62.64 39.825 ;
     RECT  2.16 40.095 62.64 40.365 ;
     RECT  2.16 40.635 62.64 40.905 ;
     RECT  2.16 41.175 62.64 41.445 ;
     RECT  2.16 41.715 62.64 41.985 ;
     RECT  2.16 42.255 62.64 42.525 ;
     RECT  2.16 42.795 62.64 43.065 ;
     RECT  2.16 43.335 62.64 43.605 ;
     RECT  2.16 43.875 62.64 44.145 ;
     RECT  2.16 44.415 62.64 44.685 ;
     RECT  2.16 44.955 62.64 45.225 ;
     RECT  2.16 45.495 62.64 45.765 ;
     RECT  2.16 46.035 62.64 46.305 ;
     RECT  2.16 46.575 62.64 46.845 ;
     RECT  2.16 47.115 62.64 47.385 ;
     RECT  2.16 47.655 62.64 47.925 ;
     RECT  2.16 48.195 62.64 48.465 ;
     RECT  2.16 48.735 62.64 49.005 ;
     RECT  2.16 49.275 62.64 49.545 ;
     RECT  2.16 49.815 62.64 50.085 ;
     RECT  2.16 50.355 62.64 50.625 ;
     RECT  2.16 50.895 62.64 51.165 ;
     RECT  2.16 51.435 62.64 51.705 ;
     RECT  2.16 51.975 62.64 52.245 ;
     RECT  2.16 52.515 62.64 52.785 ;
     RECT  2.16 53.055 62.64 53.325 ;
     RECT  2.16 53.595 62.64 53.865 ;
     RECT  2.16 54.135 62.64 54.405 ;
     RECT  2.16 54.675 62.64 54.945 ;
     RECT  2.16 55.215 62.64 55.485 ;
     RECT  2.16 55.755 62.64 56.025 ;
     RECT  2.16 56.295 62.64 56.565 ;
     RECT  2.16 56.835 62.64 57.105 ;
     RECT  2.16 57.375 62.64 57.645 ;
     RECT  2.16 57.915 62.64 58.185 ;
     RECT  2.16 58.455 62.64 58.725 ;
     RECT  2.16 58.995 62.64 59.265 ;
     RECT  2.16 59.535 62.64 59.805 ;
     RECT  2.16 60.075 62.64 60.345 ;
     RECT  2.16 60.615 62.64 60.885 ;
     RECT  2.16 61.155 62.64 61.425 ;
     RECT  2.16 61.695 62.64 61.965 ;
     RECT  2.16 62.235 62.64 62.505 ;
    LAYER M1 ;
     RECT  2.16 2.151 62.64 62.649 ;
    LAYER M2 ;
     RECT  2.16 2.151 4.711 62.649 ;
     RECT  4.711 2.151 4.811 62.694 ;
     RECT  4.811 2.151 9.175 62.649 ;
     RECT  9.175 2.151 10.031 62.694 ;
     RECT  10.031 2.151 10.831 62.649 ;
     RECT  10.831 2.151 11.039 62.694 ;
     RECT  11.039 2.151 16.051 62.649 ;
     RECT  16.051 2.151 16.151 62.694 ;
     RECT  16.151 2.151 20.119 62.649 ;
     RECT  20.119 2.151 24.755 62.694 ;
     RECT  24.755 2.151 39.307 62.649 ;
     RECT  39.307 2.106 41.027 62.649 ;
     RECT  41.027 2.151 45.103 62.649 ;
     RECT  45.103 2.151 46.823 62.694 ;
     RECT  46.823 2.151 49.603 62.649 ;
     RECT  49.603 2.151 50.819 62.694 ;
     RECT  50.819 2.151 54.679 62.649 ;
     RECT  54.679 2.151 57.587 62.73 ;
     RECT  57.587 2.151 60.943 62.694 ;
     RECT  60.943 2.106 60.979 62.694 ;
     RECT  60.979 2.106 61.583 62.766 ;
     RECT  61.583 2.106 62.159 62.649 ;
     RECT  62.159 2.151 62.64 62.649 ;
     RECT  62.64 59.472 62.699 62.604 ;
     RECT  62.64 7.74 62.735 13.932 ;
     RECT  62.64 25.254 62.735 35.802 ;
     RECT  62.64 43.11 62.735 43.326 ;
     RECT  62.64 20.7 62.771 24.498 ;
     RECT  62.64 45.936 62.807 49.914 ;
     RECT  62.771 24.48 62.951 24.498 ;
     RECT  62.64 3.69 63.059 3.978 ;
     RECT  62.735 7.776 63.239 13.932 ;
     RECT  62.771 20.7 63.239 23.652 ;
     RECT  62.64 39.33 63.239 42.282 ;
     RECT  62.64 5.58 63.275 6.84 ;
     RECT  63.239 7.776 63.275 9.306 ;
     RECT  62.64 14.688 63.275 19.332 ;
     RECT  63.239 22.086 63.275 23.652 ;
     RECT  62.735 25.254 63.275 33.948 ;
     RECT  62.64 36.828 63.275 38.304 ;
     RECT  62.807 46.08 63.275 49.914 ;
     RECT  63.275 5.58 63.311 6.066 ;
     RECT  63.275 7.776 63.311 9.036 ;
     RECT  63.239 10.098 63.311 13.932 ;
     RECT  63.239 20.7 63.311 21.258 ;
     RECT  63.275 23.094 63.311 23.652 ;
     RECT  63.239 42.264 63.311 42.282 ;
     RECT  63.275 49.32 63.311 49.914 ;
     RECT  63.311 20.898 63.347 21.258 ;
     RECT  63.275 25.524 63.347 33.948 ;
     RECT  62.699 59.472 63.383 62.424 ;
     RECT  63.059 3.96 63.563 3.978 ;
     RECT  63.383 61.776 63.707 62.424 ;
     RECT  63.311 9.018 63.779 9.036 ;
     RECT  63.347 29.07 63.779 33.948 ;
     RECT  63.275 36.828 63.779 38.196 ;
     RECT  63.347 21.24 63.851 21.258 ;
     RECT  62.735 34.74 63.851 35.802 ;
     RECT  63.779 36.828 63.851 37.764 ;
     RECT  63.239 39.33 63.851 41.508 ;
     RECT  63.275 46.08 63.851 48.528 ;
     RECT  63.275 6.822 63.887 6.84 ;
     RECT  63.311 7.776 63.887 8.262 ;
     RECT  63.311 10.098 63.887 13.464 ;
     RECT  63.275 14.76 63.887 19.332 ;
     RECT  63.311 23.436 63.887 23.652 ;
     RECT  63.347 25.596 63.887 28.314 ;
     RECT  63.779 29.07 63.887 29.556 ;
     RECT  63.851 39.33 63.887 40.194 ;
     RECT  63.851 40.95 63.887 40.968 ;
     RECT  62.735 43.308 63.887 43.326 ;
     RECT  63.851 47.736 63.887 48.528 ;
     RECT  62.64 50.904 63.887 55.206 ;
     RECT  63.311 5.58 63.923 5.598 ;
     RECT  63.887 7.776 63.923 7.794 ;
     RECT  63.887 10.098 63.923 10.926 ;
     RECT  63.887 15.066 63.923 19.332 ;
     RECT  63.887 23.436 63.923 23.454 ;
     RECT  63.887 25.686 63.923 28.314 ;
     RECT  63.887 47.736 63.923 47.952 ;
     RECT  62.64 56.034 63.923 58.716 ;
     RECT  63.923 15.066 63.959 17.784 ;
     RECT  63.923 18.81 63.959 19.332 ;
     RECT  63.311 49.32 64.435 49.842 ;
     RECT  63.887 52.758 64.499 55.206 ;
     RECT  63.923 58.392 64.507 58.716 ;
     RECT  63.383 59.472 64.507 59.832 ;
     RECT  63.923 26.604 64.543 28.314 ;
     RECT  63.887 29.07 64.543 29.358 ;
     RECT  63.923 56.034 64.571 57.402 ;
     RECT  63.923 10.098 64.579 10.116 ;
     RECT  63.959 15.066 64.607 16.974 ;
     RECT  64.543 26.604 64.607 29.358 ;
     RECT  64.499 54.99 64.607 55.206 ;
     RECT  64.571 56.916 64.607 57.402 ;
     RECT  63.923 10.908 64.615 10.926 ;
     RECT  63.887 11.826 64.615 12.546 ;
     RECT  63.887 40.176 64.615 40.194 ;
     RECT  63.851 46.08 64.615 46.098 ;
     RECT  64.507 58.392 64.615 59.832 ;
     RECT  64.579 10.026 64.643 10.116 ;
     RECT  64.615 10.908 64.643 12.546 ;
     RECT  64.607 28.296 64.643 29.358 ;
     RECT  63.851 36.828 64.643 36.846 ;
     RECT  63.923 47.934 64.643 47.952 ;
     RECT  63.887 50.94 64.643 51.354 ;
     RECT  64.499 52.758 64.643 54.126 ;
     RECT  64.643 10.026 64.679 10.044 ;
     RECT  63.887 13.302 64.679 13.464 ;
     RECT  63.959 18.846 64.679 19.332 ;
     RECT  64.607 26.604 64.679 27.468 ;
     RECT  63.851 34.74 64.679 35.064 ;
     RECT  64.643 50.94 64.679 51.228 ;
     RECT  64.643 53.334 64.679 53.424 ;
     RECT  64.607 56.916 64.679 57.204 ;
     RECT  63.707 61.776 64.679 62.298 ;
     RECT  64.643 29.07 64.687 29.358 ;
     RECT  64.643 10.908 64.715 11.574 ;
     RECT  64.643 12.528 64.715 12.546 ;
     RECT  64.607 15.066 64.715 16.29 ;
     RECT  63.959 17.766 64.715 17.784 ;
     RECT  64.679 18.846 64.715 19.098 ;
     RECT  63.275 22.086 64.715 22.104 ;
     RECT  64.615 23.166 64.715 23.184 ;
     RECT  63.923 25.686 64.715 25.704 ;
     RECT  64.679 27.45 64.715 27.468 ;
     RECT  64.643 28.296 64.715 28.314 ;
     RECT  64.687 29.07 64.715 29.628 ;
     RECT  63.779 31.968 64.715 33.948 ;
     RECT  64.679 35.046 64.715 35.064 ;
     RECT  64.615 39.6 64.715 40.194 ;
     RECT  64.615 41.994 64.715 42.012 ;
     RECT  64.615 46.08 64.715 46.26 ;
     RECT  64.435 49.176 64.715 49.842 ;
     RECT  64.679 51.21 64.715 51.228 ;
     RECT  64.679 53.334 64.715 53.352 ;
     RECT  64.607 54.99 64.715 55.008 ;
     RECT  64.571 56.034 64.715 56.052 ;
     RECT  64.679 57.186 64.715 57.204 ;
     RECT  64.615 58.392 64.715 59.994 ;
     RECT  64.579 60.966 64.715 60.984 ;
     RECT  64.679 61.776 64.715 61.794 ;
     RECT  64.679 26.604 64.787 26.622 ;
     RECT  64.715 29.61 64.787 29.628 ;
    LAYER M3 ;
     RECT  24.66 1.147 24.678 2.143 ;
     RECT  41.004 2.101 41.022 2.143 ;
     RECT  62.136 2.101 62.154 2.143 ;
     RECT  18.615 2.143 18.705 2.191 ;
     RECT  39.312 2.101 39.33 2.191 ;
     RECT  60.948 2.101 60.966 2.191 ;
     RECT  11.052 2.191 11.07 2.227 ;
     RECT  13.215 2.143 13.305 2.227 ;
     RECT  61.815 2.143 62.154 2.227 ;
     RECT  8.784 2.227 8.802 2.251 ;
     RECT  13.215 2.227 13.77 2.251 ;
     RECT  25.416 1.723 25.434 2.251 ;
     RECT  51.015 2.143 51.105 2.251 ;
     RECT  8.676 2.251 8.802 2.263 ;
     RECT  12.6 2.251 13.77 2.263 ;
     RECT  21.168 2.191 21.186 2.263 ;
     RECT  28.224 2.227 28.242 2.263 ;
     RECT  34.815 2.143 34.905 2.263 ;
     RECT  43.272 2.191 43.29 2.263 ;
     RECT  46.764 2.227 46.782 2.263 ;
     RECT  51.015 2.251 51.21 2.263 ;
     RECT  60.948 2.191 61.074 2.263 ;
     RECT  61.815 2.227 62.37 2.263 ;
     RECT  18.036 2.191 18.705 2.299 ;
     RECT  32.94 2.227 32.958 2.299 ;
     RECT  41.832 2.263 41.85 2.299 ;
     RECT  42.84 2.263 43.29 2.299 ;
     RECT  44.784 2.227 44.802 2.299 ;
     RECT  55.08 2.227 55.098 2.299 ;
     RECT  60.948 2.263 62.37 2.299 ;
     RECT  8.676 2.263 8.874 2.335 ;
     RECT  17.568 2.299 18.705 2.335 ;
     RECT  20.484 2.263 21.186 2.335 ;
     RECT  31.32 2.263 31.338 2.335 ;
     RECT  37.548 2.299 37.566 2.335 ;
     RECT  55.08 2.299 55.242 2.335 ;
     RECT  12.6 2.263 13.914 2.371 ;
     RECT  15.588 2.227 15.606 2.371 ;
     RECT  16.632 2.335 16.65 2.371 ;
     RECT  24.015 2.143 24.678 2.371 ;
     RECT  25.416 2.251 25.758 2.371 ;
     RECT  29.415 2.143 29.505 2.371 ;
     RECT  30.924 2.335 31.338 2.371 ;
     RECT  32.112 2.227 32.13 2.371 ;
     RECT  32.94 2.299 33.318 2.371 ;
     RECT  34.092 2.263 34.905 2.371 ;
     RECT  37.368 2.335 37.566 2.371 ;
     RECT  38.556 2.299 38.574 2.371 ;
     RECT  39.312 2.191 39.474 2.371 ;
     RECT  40.215 2.143 41.022 2.371 ;
     RECT  41.832 2.299 43.29 2.371 ;
     RECT  44.28 2.299 44.874 2.371 ;
     RECT  45.615 2.143 45.705 2.371 ;
     RECT  46.764 2.263 47.394 2.371 ;
     RECT  48.42 2.227 48.438 2.371 ;
     RECT  49.536 2.227 49.554 2.371 ;
     RECT  50.976 2.263 51.39 2.371 ;
     RECT  55.044 2.335 55.242 2.371 ;
     RECT  2.415 2.143 2.505 2.413 ;
     RECT  7.815 2.143 7.905 2.413 ;
     RECT  8.676 2.335 9.126 2.413 ;
     RECT  17.46 2.335 18.705 2.413 ;
     RECT  29.16 2.371 29.505 2.413 ;
     RECT  34.092 2.371 34.974 2.413 ;
     RECT  41.832 2.371 45.705 2.413 ;
     RECT  46.44 2.371 47.394 2.413 ;
     RECT  56.415 2.143 56.505 2.413 ;
     RECT  12.6 2.371 14.634 2.461 ;
     RECT  34.092 2.413 35.097 2.461 ;
     RECT  36.036 2.191 36.558 2.461 ;
     RECT  37.368 2.371 37.638 2.461 ;
     RECT  38.448 2.371 38.574 2.461 ;
     RECT  39.312 2.371 41.022 2.461 ;
     RECT  17.46 2.413 18.897 2.489 ;
     RECT  20.232 2.335 21.186 2.491 ;
     RECT  59.04 2.461 59.058 2.491 ;
     RECT  15.588 2.371 16.65 2.497 ;
     RECT  17.46 2.489 17.586 2.497 ;
     RECT  23.904 2.371 25.758 2.533 ;
     RECT  58.608 2.491 59.058 2.533 ;
     RECT  15.588 2.497 17.586 2.569 ;
     RECT  20.232 2.491 21.33 2.569 ;
     RECT  58.356 2.533 59.058 2.569 ;
     RECT  12.564 2.461 14.634 2.605 ;
     RECT  15.444 2.569 17.586 2.605 ;
     RECT  29.16 2.413 29.697 2.605 ;
     RECT  30.924 2.371 32.13 2.605 ;
     RECT  32.868 2.371 33.318 2.605 ;
     RECT  34.092 2.461 37.638 2.605 ;
     RECT  38.376 2.461 41.022 2.605 ;
     RECT  41.832 2.413 47.394 2.605 ;
     RECT  50.796 2.371 51.39 2.605 ;
     RECT  53.532 2.371 53.55 2.605 ;
     RECT  55.044 2.371 55.458 2.605 ;
     RECT  56.415 2.413 56.697 2.605 ;
     RECT  6.912 2.569 6.93 2.641 ;
     RECT  7.815 2.413 9.126 2.641 ;
     RECT  10.332 2.227 11.07 2.641 ;
     RECT  18.468 2.489 18.897 2.641 ;
     RECT  20.052 2.569 21.33 2.641 ;
     RECT  22.392 2.488 22.41 2.641 ;
     RECT  23.688 2.533 25.758 2.641 ;
     RECT  28.224 2.263 28.422 2.641 ;
     RECT  29.16 2.605 32.13 2.641 ;
     RECT  32.868 2.605 37.638 2.641 ;
     RECT  48.168 2.371 48.438 2.641 ;
     RECT  49.428 2.371 49.554 2.641 ;
     RECT  50.76 2.605 51.39 2.641 ;
     RECT  53.496 2.605 53.55 2.641 ;
     RECT  54.684 2.605 56.697 2.641 ;
     RECT  58.248 2.569 59.058 2.641 ;
     RECT  60.624 2.299 62.37 2.641 ;
     RECT  9.936 2.641 11.07 2.731 ;
     RECT  12.564 2.605 17.586 2.731 ;
     RECT  52.596 2.641 57.186 2.731 ;
     RECT  58.14 2.641 59.058 2.731 ;
     RECT  48.168 2.641 49.554 2.767 ;
     RECT  50.328 2.641 51.39 2.767 ;
     RECT  60.012 2.641 62.37 2.767 ;
     RECT  29.16 2.641 37.638 2.779 ;
     RECT  38.376 2.605 47.394 2.779 ;
     RECT  52.596 2.731 59.058 2.839 ;
     RECT  29.16 2.779 47.394 2.875 ;
     RECT  48.168 2.767 51.39 2.875 ;
     RECT  28.152 2.641 28.422 2.911 ;
     RECT  29.16 2.875 51.39 2.911 ;
     RECT  52.164 2.839 59.058 2.911 ;
     RECT  28.152 2.911 59.058 3.109 ;
     RECT  59.904 2.767 62.37 3.109 ;
     RECT  6.84 2.641 9.126 3.181 ;
     RECT  9.936 2.731 17.586 3.181 ;
     RECT  28.152 3.109 62.37 3.181 ;
     RECT  6.84 3.181 17.586 3.209 ;
     RECT  18.468 2.641 27.378 3.271 ;
     RECT  28.152 3.181 62.442 3.271 ;
     RECT  7.056 3.209 17.586 3.389 ;
     RECT  16.812 3.389 17.586 3.541 ;
     RECT  18.468 3.271 62.442 3.541 ;
     RECT  16.812 3.541 62.442 3.685 ;
     RECT  16.812 3.685 63.054 3.749 ;
     RECT  16.812 3.749 57.762 3.839 ;
     RECT  58.5 3.749 63.054 3.955 ;
     RECT  7.056 3.389 16.074 4.153 ;
     RECT  6.84 4.153 16.074 4.423 ;
     RECT  6.588 4.423 16.074 4.507 ;
     RECT  16.884 3.839 57.762 4.603 ;
     RECT  58.5 3.955 63.558 4.603 ;
     RECT  6.552 4.507 16.074 4.693 ;
     RECT  16.884 4.603 63.558 4.693 ;
     RECT  6.552 4.693 63.558 4.747 ;
     RECT  5.976 4.747 63.558 4.765 ;
     RECT  5.76 4.765 63.558 4.793 ;
     RECT  6.552 4.793 63.558 4.919 ;
     RECT  23.724 4.919 63.558 5.027 ;
     RECT  23.724 5.027 46.494 5.165 ;
     RECT  28.764 5.165 46.494 5.261 ;
     RECT  47.268 5.027 63.558 5.575 ;
     RECT  5.76 4.793 5.778 5.645 ;
     RECT  6.552 4.919 22.95 5.737 ;
     RECT  23.724 5.165 27.99 5.737 ;
     RECT  28.836 5.261 46.494 5.809 ;
     RECT  47.268 5.575 63.918 5.809 ;
     RECT  6.552 5.737 27.99 5.971 ;
     RECT  6.264 5.971 27.99 6.151 ;
     RECT  28.836 5.809 63.918 6.151 ;
     RECT  5.328 6.283 5.346 6.511 ;
     RECT  5.112 6.511 5.346 6.691 ;
     RECT  4.932 6.691 5.346 6.781 ;
     RECT  6.264 6.151 63.918 6.781 ;
     RECT  4.176 6.691 4.194 6.889 ;
     RECT  4.932 6.781 63.918 6.889 ;
     RECT  2.415 2.413 2.697 6.925 ;
     RECT  2.415 6.925 3.294 6.961 ;
     RECT  4.104 6.889 63.918 6.961 ;
     RECT  2.415 6.961 63.918 8.311 ;
     RECT  2.376 8.311 63.918 8.525 ;
     RECT  2.415 8.525 63.918 9.197 ;
     RECT  2.415 9.197 63.27 9.311 ;
     RECT  2.415 9.311 63.234 9.851 ;
     RECT  64.548 9.739 64.638 10.021 ;
     RECT  64.548 10.021 64.674 10.061 ;
     RECT  64.548 10.061 64.638 10.121 ;
     RECT  63.216 9.851 63.234 10.129 ;
     RECT  2.415 9.851 62.442 10.291 ;
     RECT  64.548 10.121 64.566 10.411 ;
     RECT  63.216 10.129 63.27 10.705 ;
     RECT  64.476 10.411 64.566 10.705 ;
     RECT  2.376 10.291 62.442 10.795 ;
     RECT  63.216 10.705 64.566 10.795 ;
     RECT  2.376 10.795 64.566 10.891 ;
     RECT  2.376 10.891 64.71 11.213 ;
     RECT  2.376 11.213 63.882 11.237 ;
     RECT  2.376 11.237 63.27 11.281 ;
     RECT  2.304 11.281 63.27 11.405 ;
     RECT  64.62 11.213 64.71 11.885 ;
     RECT  2.415 11.405 63.27 12.047 ;
     RECT  63.756 12.235 63.846 12.389 ;
     RECT  2.415 12.047 62.802 12.523 ;
     RECT  64.692 11.885 64.71 12.551 ;
     RECT  2.34 12.523 62.802 12.907 ;
     RECT  2.34 12.907 63.27 13.171 ;
     RECT  64.476 12.715 64.602 13.171 ;
     RECT  2.34 13.171 64.602 13.288 ;
     RECT  2.34 13.288 64.674 13.661 ;
     RECT  2.415 13.661 64.674 13.973 ;
     RECT  63.252 13.973 64.674 14.189 ;
     RECT  63.252 14.189 64.638 14.237 ;
     RECT  63.252 14.237 63.882 14.711 ;
     RECT  63.288 14.711 63.882 14.765 ;
     RECT  64.62 14.237 64.638 15.019 ;
     RECT  2.415 13.973 62.514 15.547 ;
     RECT  2.415 15.547 62.586 15.593 ;
     RECT  63.828 14.765 63.882 15.691 ;
     RECT  64.62 15.019 64.71 15.691 ;
     RECT  63.828 15.691 64.71 16.267 ;
     RECT  63.252 16.267 64.71 16.304 ;
     RECT  2.415 15.593 62.514 16.673 ;
     RECT  63.252 16.304 64.638 16.685 ;
     RECT  16.704 16.673 62.514 16.799 ;
     RECT  63.9 16.685 64.638 17.455 ;
     RECT  16.704 16.799 62.478 17.581 ;
     RECT  2.415 16.673 15.966 17.611 ;
     RECT  2.412 17.611 15.966 17.617 ;
     RECT  63.864 17.455 64.638 17.659 ;
     RECT  63.252 17.659 64.638 17.761 ;
     RECT  63.252 17.761 64.71 17.933 ;
     RECT  2.376 17.617 15.966 17.995 ;
     RECT  16.704 17.581 62.514 17.995 ;
     RECT  2.376 17.995 62.514 18.077 ;
     RECT  42.84 18.077 62.514 18.193 ;
     RECT  63.252 17.933 64.53 18.193 ;
     RECT  42.84 18.193 64.53 18.317 ;
     RECT  63.828 18.317 64.53 18.841 ;
     RECT  63.828 18.841 64.71 18.989 ;
     RECT  2.376 18.077 42.066 19.075 ;
     RECT  42.84 18.317 62.766 19.075 ;
     RECT  63.864 18.989 63.882 19.949 ;
     RECT  2.376 19.075 62.766 20.075 ;
     RECT  64.656 18.989 64.71 20.141 ;
     RECT  64.656 20.141 64.674 20.525 ;
     RECT  2.415 20.075 62.766 20.695 ;
     RECT  2.415 20.695 63.306 20.779 ;
     RECT  2.415 20.779 63.846 21.263 ;
     RECT  2.415 21.263 63.342 21.293 ;
     RECT  2.415 21.293 63.306 21.569 ;
     RECT  64.692 21.547 64.71 22.109 ;
     RECT  45.576 21.569 63.306 22.219 ;
     RECT  45.576 22.219 63.558 22.315 ;
     RECT  2.415 21.569 44.802 22.513 ;
     RECT  45.576 22.315 63.882 22.513 ;
     RECT  2.415 22.513 63.882 22.795 ;
     RECT  2.415 22.795 64.494 22.891 ;
     RECT  2.415 22.891 64.602 23.131 ;
     RECT  2.415 23.131 64.638 23.161 ;
     RECT  2.415 23.161 64.71 23.213 ;
     RECT  2.415 23.213 64.566 23.657 ;
     RECT  64.548 23.657 64.566 24.043 ;
     RECT  2.415 23.657 63.558 24.197 ;
     RECT  2.415 24.197 3.798 24.899 ;
     RECT  4.572 24.197 63.558 24.907 ;
     RECT  64.548 24.043 64.638 24.907 ;
     RECT  4.572 24.907 64.638 25.387 ;
     RECT  4.572 25.387 64.71 25.709 ;
     RECT  2.415 24.899 3.762 25.861 ;
     RECT  4.572 25.709 64.674 25.861 ;
     RECT  2.415 25.861 64.674 26.599 ;
     RECT  2.415 26.599 64.782 26.717 ;
     RECT  64.404 26.717 64.782 27.149 ;
     RECT  2.415 26.717 63.27 27.239 ;
     RECT  64.476 27.149 64.782 28.021 ;
     RECT  2.415 27.239 62.946 28.481 ;
     RECT  2.415 28.481 3.402 28.553 ;
     RECT  63.864 28.021 64.782 28.555 ;
     RECT  4.14 28.481 62.946 28.831 ;
     RECT  63.828 28.555 64.782 28.831 ;
     RECT  4.14 28.831 64.782 28.859 ;
     RECT  64.62 28.859 64.782 28.877 ;
     RECT  2.415 28.553 3.294 29.029 ;
     RECT  2.34 29.029 3.294 29.069 ;
     RECT  4.14 28.859 63.882 29.461 ;
     RECT  2.415 29.069 3.294 29.605 ;
     RECT  64.656 28.877 64.782 29.633 ;
     RECT  64.656 29.633 64.71 29.645 ;
     RECT  4.104 29.461 63.882 30.125 ;
     RECT  2.415 29.605 3.33 30.181 ;
     RECT  4.104 30.125 63.774 30.181 ;
     RECT  64.656 29.645 64.674 30.221 ;
     RECT  2.415 30.181 63.774 30.685 ;
     RECT  2.376 30.685 63.774 31.483 ;
     RECT  2.376 31.483 63.846 31.649 ;
     RECT  2.415 31.649 63.846 32.011 ;
     RECT  64.692 31.531 64.71 32.011 ;
     RECT  2.415 32.011 64.71 32.801 ;
     RECT  64.44 32.801 64.71 33.575 ;
     RECT  2.415 32.801 63.27 33.881 ;
     RECT  64.512 33.575 64.71 34.507 ;
     RECT  64.476 34.507 64.71 34.735 ;
     RECT  63.864 34.735 64.71 35.069 ;
     RECT  63.864 35.069 64.638 35.213 ;
     RECT  63.864 35.213 63.882 35.309 ;
     RECT  2.415 33.881 62.946 35.509 ;
     RECT  63.828 35.755 63.846 35.807 ;
     RECT  2.376 35.509 62.946 36.811 ;
     RECT  63.828 36.715 63.846 36.811 ;
     RECT  64.62 35.213 64.638 36.851 ;
     RECT  2.376 36.811 63.846 37.625 ;
     RECT  41.904 37.625 63.846 37.769 ;
     RECT  2.376 37.625 41.166 38.039 ;
     RECT  2.376 38.039 5.094 38.129 ;
     RECT  2.415 38.129 5.094 38.152 ;
     RECT  41.904 37.769 63.774 38.201 ;
     RECT  6.012 38.039 41.166 38.713 ;
     RECT  41.904 38.201 63.738 38.713 ;
     RECT  2.415 38.152 5.058 38.983 ;
     RECT  2.415 38.983 5.13 39.083 ;
     RECT  4.932 39.083 5.13 39.119 ;
     RECT  6.012 38.713 63.738 39.209 ;
     RECT  6.804 39.209 63.738 39.325 ;
     RECT  64.512 39.115 64.53 39.325 ;
     RECT  4.968 39.119 5.13 39.361 ;
     RECT  6.012 39.209 6.03 39.361 ;
     RECT  6.804 39.325 64.53 39.547 ;
     RECT  6.804 39.547 64.638 39.595 ;
     RECT  2.415 39.083 4.158 39.631 ;
     RECT  6.804 39.595 64.71 39.725 ;
     RECT  2.376 39.631 4.158 39.901 ;
     RECT  4.968 39.361 6.03 39.901 ;
     RECT  6.804 39.725 63.882 39.917 ;
     RECT  42.012 39.917 63.882 40.127 ;
     RECT  2.376 39.901 6.03 40.135 ;
     RECT  6.804 39.917 41.274 40.135 ;
     RECT  64.62 39.725 64.71 40.199 ;
     RECT  2.376 40.135 41.274 40.637 ;
     RECT  64.62 40.199 64.638 40.637 ;
     RECT  2.415 40.637 41.274 40.711 ;
     RECT  2.415 40.711 41.31 40.945 ;
     RECT  42.048 40.127 63.882 40.945 ;
     RECT  2.415 40.945 63.882 41.035 ;
     RECT  2.415 41.035 64.53 41.165 ;
     RECT  2.415 41.165 63.846 41.645 ;
     RECT  2.415 41.645 63.306 41.675 ;
     RECT  64.62 41.659 64.638 41.989 ;
     RECT  2.415 41.675 42.174 42.187 ;
     RECT  64.62 41.989 64.71 42.187 ;
     RECT  42.912 41.675 63.306 42.287 ;
     RECT  64.512 42.187 64.71 42.413 ;
     RECT  64.692 42.413 64.71 42.557 ;
     RECT  2.376 42.187 42.174 42.601 ;
     RECT  42.912 42.287 62.946 42.601 ;
     RECT  2.376 42.601 62.946 44.609 ;
     RECT  2.376 44.609 41.67 44.879 ;
     RECT  42.408 44.609 62.946 44.879 ;
     RECT  63.864 43.303 63.882 45.163 ;
     RECT  64.692 45.115 64.71 45.163 ;
     RECT  63.864 45.163 64.71 45.293 ;
     RECT  64.548 45.293 64.71 45.581 ;
     RECT  2.415 44.879 41.67 45.697 ;
     RECT  42.444 44.879 62.946 45.697 ;
     RECT  2.415 45.697 62.946 46.201 ;
     RECT  64.62 45.581 64.71 46.265 ;
     RECT  64.62 46.265 64.638 46.301 ;
     RECT  2.376 46.201 62.946 46.309 ;
     RECT  2.376 46.309 63.306 46.603 ;
     RECT  2.376 46.603 63.846 46.805 ;
     RECT  2.415 46.805 63.846 46.925 ;
     RECT  63.756 46.925 63.846 47.323 ;
     RECT  64.62 47.131 64.638 47.323 ;
     RECT  2.415 46.925 62.946 48.139 ;
     RECT  63.756 47.323 64.638 48.139 ;
     RECT  2.415 48.139 64.638 48.811 ;
     RECT  2.376 48.811 64.638 49.171 ;
     RECT  2.376 49.171 64.71 49.343 ;
     RECT  2.376 49.343 63.306 50.429 ;
     RECT  2.376 50.429 62.946 50.855 ;
     RECT  64.476 49.343 64.71 50.899 ;
     RECT  63.864 50.899 64.71 51.233 ;
     RECT  63.864 51.233 64.638 51.437 ;
     RECT  2.415 50.855 62.946 51.475 ;
     RECT  63.864 51.437 63.882 51.475 ;
     RECT  2.415 51.475 63.882 52.109 ;
     RECT  64.62 51.437 64.638 52.651 ;
     RECT  2.415 52.109 63.846 52.861 ;
     RECT  64.62 52.651 64.674 52.939 ;
     RECT  2.376 52.861 63.846 53.035 ;
     RECT  64.62 52.939 64.71 53.357 ;
     RECT  64.62 53.357 64.674 53.429 ;
     RECT  2.376 53.035 63.882 53.803 ;
     RECT  64.62 53.429 64.638 53.803 ;
     RECT  2.376 53.803 64.638 54.329 ;
     RECT  2.415 54.329 64.638 54.955 ;
     RECT  2.415 54.955 64.71 55.013 ;
     RECT  2.415 55.013 64.638 55.211 ;
     RECT  2.415 55.211 63.882 55.469 ;
     RECT  64.62 55.211 64.638 55.915 ;
     RECT  64.62 55.915 64.71 56.011 ;
     RECT  2.415 55.469 63.234 56.203 ;
     RECT  2.415 56.203 63.27 56.633 ;
     RECT  2.415 56.633 63.162 56.831 ;
     RECT  2.415 56.831 63.09 56.911 ;
     RECT  2.376 56.911 63.09 57.065 ;
     RECT  64.476 56.011 64.71 57.067 ;
     RECT  64.44 57.067 64.71 57.197 ;
     RECT  64.512 57.197 64.71 57.209 ;
     RECT  2.376 57.065 63.018 57.371 ;
     RECT  64.512 57.209 64.638 57.485 ;
     RECT  2.376 57.371 62.946 57.581 ;
     RECT  63.9 57.919 63.918 58.219 ;
     RECT  63.9 58.219 64.638 58.315 ;
     RECT  2.415 57.581 62.946 58.747 ;
     RECT  2.376 58.747 62.946 59.189 ;
     RECT  63.9 58.315 64.71 59.467 ;
     RECT  63.864 59.467 64.71 59.789 ;
     RECT  63.9 59.789 64.71 59.999 ;
     RECT  63.9 59.999 64.674 60.173 ;
     RECT  2.415 59.189 62.946 60.511 ;
     RECT  63.9 60.173 64.53 60.511 ;
     RECT  2.415 60.511 64.53 60.557 ;
     RECT  64.512 60.557 64.53 60.653 ;
     RECT  64.584 60.907 64.602 60.961 ;
     RECT  64.584 60.961 64.71 60.989 ;
     RECT  2.415 60.557 63.378 61.123 ;
     RECT  2.376 61.123 63.378 61.259 ;
     RECT  64.656 60.989 64.71 61.799 ;
     RECT  2.376 61.259 63.306 61.889 ;
     RECT  2.415 61.889 63.306 62.033 ;
     RECT  39.528 62.033 63.306 62.131 ;
     RECT  21.024 62.033 38.61 62.189 ;
     RECT  2.415 62.033 20.286 62.195 ;
     RECT  64.656 61.799 64.674 62.303 ;
     RECT  39.528 62.131 63.882 62.339 ;
     RECT  2.415 62.195 2.697 62.387 ;
     RECT  3.564 62.195 20.286 62.429 ;
     RECT  21.024 62.189 23.166 62.429 ;
     RECT  24.015 62.189 38.61 62.429 ;
     RECT  39.528 62.339 41.886 62.429 ;
     RECT  42.66 62.339 63.882 62.429 ;
     RECT  3.564 62.429 20.25 62.501 ;
     RECT  41.076 62.429 41.742 62.573 ;
     RECT  43.164 62.429 63.882 62.579 ;
     RECT  8.82 62.501 20.25 62.609 ;
     RECT  43.488 62.579 63.882 62.609 ;
     RECT  2.415 62.387 2.505 62.657 ;
     RECT  24.015 62.429 28.062 62.657 ;
     RECT  39.528 62.429 40.305 62.657 ;
     RECT  3.564 62.501 8.01 62.669 ;
     RECT  8.82 62.609 20.142 62.699 ;
     RECT  24.732 62.657 28.062 62.699 ;
     RECT  3.564 62.669 7.686 62.717 ;
     RECT  29.052 62.429 38.61 62.765 ;
     RECT  44.352 62.609 63.882 62.765 ;
     RECT  8.82 62.699 20.07 62.813 ;
     RECT  44.352 62.765 63.306 62.813 ;
     RECT  43.488 62.609 43.506 62.957 ;
     RECT  44.352 62.813 44.37 63.005 ;
     RECT  3.564 62.717 5.166 63.245 ;
     RECT  13.176 62.813 20.07 63.245 ;
     RECT  13.176 63.245 17.658 63.293 ;
     RECT  29.124 62.765 38.61 63.293 ;
     RECT  45.216 62.813 63.306 63.293 ;
     RECT  13.356 63.293 17.658 63.341 ;
     RECT  45.216 63.293 62.946 63.341 ;
     RECT  13.608 63.341 17.658 63.533 ;
     RECT  41.076 62.573 41.094 63.533 ;
     RECT  48.06 63.341 62.946 63.581 ;
     RECT  45.216 63.341 47.286 63.629 ;
     RECT  48.24 63.581 62.946 63.677 ;
     RECT  8.82 62.813 12.438 63.739 ;
     RECT  6.084 62.717 7.686 63.773 ;
     RECT  14.796 63.533 17.658 63.773 ;
     RECT  4.32 63.245 5.166 63.821 ;
     RECT  6.084 63.773 6.426 63.821 ;
     RECT  14.796 63.773 15.93 63.821 ;
     RECT  18.576 63.245 20.07 63.821 ;
     RECT  32.58 63.293 38.61 63.821 ;
     RECT  39.528 62.657 39.546 63.821 ;
     RECT  48.24 63.677 50.85 63.821 ;
     RECT  52.056 63.677 62.946 63.821 ;
     RECT  25.344 62.699 28.062 63.835 ;
     RECT  4.716 63.821 4.842 63.869 ;
     RECT  8.784 63.739 12.438 63.869 ;
     RECT  14.796 63.821 15.318 63.869 ;
     RECT  17.028 63.773 17.658 63.869 ;
     RECT  29.268 63.293 31.842 63.869 ;
     RECT  32.832 63.821 38.61 63.869 ;
     RECT  45.216 63.629 47.178 63.869 ;
     RECT  48.888 63.821 50.85 63.869 ;
     RECT  52.056 63.821 59.274 63.869 ;
     RECT  60.48 63.821 62.946 63.869 ;
     RECT  7.236 63.773 7.686 63.917 ;
     RECT  8.784 63.869 11.682 63.917 ;
     RECT  32.868 63.869 35.766 63.917 ;
     RECT  52.056 63.869 54.378 63.917 ;
     RECT  55.152 63.869 55.782 63.917 ;
     RECT  60.48 63.869 60.786 63.917 ;
     RECT  61.524 63.869 62.946 63.917 ;
     RECT  25.344 63.835 28.458 63.965 ;
     RECT  29.304 63.869 31.842 63.965 ;
     RECT  32.868 63.917 35.694 63.965 ;
     RECT  52.056 63.917 52.794 63.965 ;
     RECT  56.808 63.869 59.058 63.965 ;
     RECT  61.524 63.917 62.334 63.965 ;
     RECT  26.892 63.965 28.458 64.397 ;
     RECT  12.42 63.869 12.438 64.411 ;
     RECT  13.608 63.533 14.022 64.411 ;
     RECT  52.056 63.965 52.578 64.411 ;
     RECT  56.88 63.965 59.058 64.445 ;
     RECT  21.204 62.429 23.166 64.459 ;
     RECT  12.42 64.411 14.022 64.541 ;
     RECT  20.88 64.459 23.166 64.541 ;
     RECT  29.736 63.965 31.842 64.541 ;
     RECT  56.88 64.445 57.582 64.541 ;
     RECT  14.796 63.869 15.21 64.589 ;
     RECT  27.108 64.397 28.458 64.589 ;
     RECT  29.736 64.541 30.762 64.589 ;
     RECT  36.612 63.869 38.61 64.589 ;
     RECT  51.948 64.411 52.578 64.589 ;
     RECT  58.752 64.445 59.058 64.589 ;
     RECT  18.792 63.821 20.07 64.603 ;
     RECT  55.548 63.917 55.782 64.603 ;
     RECT  8.82 63.917 11.682 64.637 ;
     RECT  14.004 64.541 14.022 64.637 ;
     RECT  20.88 64.541 21.51 64.637 ;
     RECT  25.344 63.965 26.082 64.637 ;
     RECT  29.736 64.589 30.006 64.637 ;
     RECT  32.904 63.965 35.298 64.637 ;
     RECT  36.612 64.589 36.63 64.637 ;
     RECT  45.972 63.869 46.638 64.637 ;
     RECT  18.684 64.603 20.07 64.651 ;
     RECT  20.88 64.637 20.898 64.651 ;
     RECT  51.948 64.589 52.326 64.651 ;
     RECT  4.716 63.869 4.734 64.685 ;
     RECT  7.236 63.917 7.254 64.685 ;
     RECT  8.82 64.637 9.522 64.685 ;
     RECT  10.656 64.637 11.61 64.685 ;
     RECT  12.42 64.541 12.438 64.685 ;
     RECT  14.796 64.589 14.814 64.685 ;
     RECT  18.684 64.651 20.898 64.685 ;
     RECT  22.716 64.541 23.166 64.685 ;
     RECT  25.344 64.637 25.902 64.685 ;
     RECT  27.144 64.589 28.458 64.685 ;
     RECT  29.808 64.637 29.826 64.685 ;
     RECT  30.744 64.589 30.762 64.685 ;
     RECT  31.5 64.541 31.842 64.685 ;
     RECT  33.588 64.637 35.298 64.685 ;
     RECT  37.368 64.589 38.61 64.685 ;
     RECT  45.216 63.869 45.234 64.685 ;
     RECT  46.62 64.637 46.638 64.685 ;
     RECT  48.888 63.869 49.914 64.685 ;
     RECT  50.832 63.869 50.85 64.685 ;
     RECT  51.876 64.651 52.326 64.685 ;
     RECT  53.568 63.917 54.378 64.685 ;
     RECT  56.88 64.541 56.898 64.685 ;
     RECT  58.86 64.589 59.058 64.685 ;
     RECT  60.768 63.917 60.786 64.685 ;
     RECT  61.524 63.965 61.542 64.685 ;
     RECT  62.316 63.965 62.334 64.685 ;
     RECT  18.684 64.685 18.702 64.733 ;
     RECT  23.148 64.685 23.166 64.733 ;
     RECT  51.876 64.685 51.966 64.733 ;
     RECT  55.548 64.603 56.034 64.733 ;
     RECT  15.624 64.651 15.642 64.781 ;
     RECT  19.98 64.685 20.646 64.781 ;
     RECT  25.344 64.685 25.362 64.781 ;
     RECT  51.876 64.733 51.894 64.781 ;
     RECT  55.548 64.733 55.566 64.781 ;
     RECT  59.832 64.651 59.85 64.781 ;
    LAYER M4 ;
     RECT  2.293 57.552 2.365 57.576 ;
     RECT  2.365 8.496 2.408 8.52 ;
     RECT  2.365 10.32 2.408 10.344 ;
     RECT  2.252 11.376 2.408 11.4 ;
     RECT  2.285 12.528 2.408 12.552 ;
     RECT  2.293 13.632 2.408 14.952 ;
     RECT  2.401 17.616 2.408 17.64 ;
     RECT  2.329 29.04 2.408 29.064 ;
     RECT  2.293 30.048 2.408 30.072 ;
     RECT  2.293 31.968 2.408 31.992 ;
     RECT  2.365 37.584 2.408 37.608 ;
     RECT  2.365 40.608 2.408 40.632 ;
     RECT  2.365 44.736 2.408 44.76 ;
     RECT  2.365 46.224 2.408 46.248 ;
     RECT  2.365 57.408 2.408 57.576 ;
     RECT  2.293 58.752 2.408 58.776 ;
     RECT  2.408 2.148 2.512 62.652 ;
     RECT  2.512 2.418 2.704 62.382 ;
     RECT  2.704 24.432 2.819 34.392 ;
     RECT  2.704 35.76 2.837 35.784 ;
     RECT  2.704 49.248 2.86 59.736 ;
     RECT  2.819 24.432 2.873 28.68 ;
     RECT  2.819 29.664 2.905 33.096 ;
     RECT  2.873 24.432 2.915 28.584 ;
     RECT  2.704 14.112 2.953 15.24 ;
     RECT  2.704 22.272 2.953 23.016 ;
     RECT  2.704 7.392 2.963 8.712 ;
     RECT  2.704 44.448 3.161 48.264 ;
     RECT  2.86 57.408 3.203 59.736 ;
     RECT  2.86 49.248 3.233 56.424 ;
     RECT  3.233 49.248 3.251 56.328 ;
     RECT  2.915 24.432 3.34 24.456 ;
     RECT  2.905 29.808 3.347 33.096 ;
     RECT  2.704 36.816 3.377 37.848 ;
     RECT  3.203 57.408 3.395 59.592 ;
     RECT  2.953 14.112 3.413 15.048 ;
     RECT  2.915 25.44 3.443 28.584 ;
     RECT  3.251 49.248 3.485 55.272 ;
     RECT  2.704 60.816 3.493 62.382 ;
     RECT  2.704 42.144 3.539 43.128 ;
     RECT  3.251 56.304 3.701 56.328 ;
     RECT  3.443 25.44 3.731 28.536 ;
     RECT  3.493 60.816 3.737 63.24 ;
     RECT  3.731 25.44 3.773 27.96 ;
     RECT  3.161 47.76 3.781 48.264 ;
     RECT  3.485 49.248 3.781 54.6 ;
     RECT  3.413 14.112 3.805 14.856 ;
     RECT  3.377 36.864 3.805 37.848 ;
     RECT  3.161 44.448 3.809 46.728 ;
     RECT  2.704 20.496 3.841 21.192 ;
     RECT  3.788 35.472 3.841 35.496 ;
     RECT  2.819 34.32 3.875 34.344 ;
     RECT  3.841 19.776 3.913 21.192 ;
     RECT  3.913 19.248 3.925 21.192 ;
     RECT  3.773 25.44 3.971 26.856 ;
     RECT  3.737 60.816 3.989 62.664 ;
     RECT  3.539 42.144 4.025 42.744 ;
     RECT  2.704 40.128 4.061 40.632 ;
     RECT  2.704 11.376 4.129 11.688 ;
     RECT  4.025 42.144 4.129 42.696 ;
     RECT  4.061 40.176 4.165 40.632 ;
     RECT  4.129 41.616 4.165 42.696 ;
     RECT  4.129 11.376 4.201 12.552 ;
     RECT  2.963 7.872 4.205 8.712 ;
     RECT  2.704 10.32 4.277 10.344 ;
     RECT  4.201 11.376 4.309 12.6 ;
     RECT  2.704 16.56 4.345 16.584 ;
     RECT  2.704 17.616 4.345 17.64 ;
     RECT  3.841 35.472 4.417 35.736 ;
     RECT  4.205 8.16 4.489 8.712 ;
     RECT  4.417 34.656 4.501 35.736 ;
     RECT  3.395 57.408 4.525 58.728 ;
     RECT  3.925 20.928 4.547 21.192 ;
     RECT  4.261 63.744 4.549 63.816 ;
     RECT  4.309 11.136 4.561 12.6 ;
     RECT  3.805 13.632 4.561 14.856 ;
     RECT  4.345 16.56 4.561 17.64 ;
     RECT  3.809 44.448 4.561 44.76 ;
     RECT  4.561 11.136 4.597 17.64 ;
     RECT  3.773 27.936 4.601 27.96 ;
     RECT  4.501 34.656 4.637 35.88 ;
     RECT  4.525 57.408 4.7 59.544 ;
     RECT  3.347 30.624 4.709 33.096 ;
     RECT  4.549 63.744 4.745 64.68 ;
     RECT  4.7 56.976 4.777 59.544 ;
     RECT  3.781 47.76 4.789 54.6 ;
     RECT  4.741 55.824 4.789 55.848 ;
     RECT  3.989 62.352 4.805 62.664 ;
     RECT  4.745 63.744 4.805 63.864 ;
     RECT  4.489 8.16 4.835 10.104 ;
     RECT  4.789 47.76 4.849 55.992 ;
     RECT  4.777 56.976 4.849 59.832 ;
     RECT  3.989 60.816 4.849 61.224 ;
     RECT  4.561 43.872 4.876 44.76 ;
     RECT  4.709 30.624 4.889 31.8 ;
     RECT  4.597 11.136 4.925 18.168 ;
     RECT  4.849 47.76 4.961 61.224 ;
     RECT  4.889 30.624 4.981 31.416 ;
     RECT  4.921 28.128 4.988 28.872 ;
     RECT  4.981 30.528 4.988 31.416 ;
     RECT  4.165 40.176 4.988 42.696 ;
     RECT  4.961 55.872 5.033 61.224 ;
     RECT  3.971 25.44 5.057 26.808 ;
     RECT  2.953 22.272 5.065 22.776 ;
     RECT  4.637 35.712 5.065 35.88 ;
     RECT  3.805 36.864 5.065 37.896 ;
     RECT  4.988 40.176 5.075 42.792 ;
     RECT  5.065 22.272 5.077 22.824 ;
     RECT  5.077 22.272 5.101 23.064 ;
     RECT  5.057 24.528 5.101 26.808 ;
     RECT  4.961 47.76 5.105 54.456 ;
     RECT  4.925 12.48 5.123 18.168 ;
     RECT  5.101 22.272 5.123 26.808 ;
     RECT  5.075 40.176 5.125 42.552 ;
     RECT  4.876 44.448 5.125 44.76 ;
     RECT  3.809 45.744 5.125 46.728 ;
     RECT  5.033 56.736 5.141 61.224 ;
     RECT  4.637 34.656 5.173 34.68 ;
     RECT  5.123 22.272 5.177 26.712 ;
     RECT  4.835 8.16 5.213 9.768 ;
     RECT  5.105 47.76 5.213 54.408 ;
     RECT  4.805 62.352 5.267 63.864 ;
     RECT  5.125 39.84 5.269 42.552 ;
     RECT  5.213 47.76 5.276 52.872 ;
     RECT  5.065 35.712 5.315 38.136 ;
     RECT  5.101 6.816 5.317 6.84 ;
     RECT  5.125 44.448 5.317 46.728 ;
     RECT  5.276 47.712 5.317 52.872 ;
     RECT  5.173 34.128 5.321 34.68 ;
     RECT  5.269 39.408 5.356 42.552 ;
     RECT  5.317 6.288 5.365 6.84 ;
     RECT  5.123 12.576 5.389 18.168 ;
     RECT  3.925 19.248 5.389 19.8 ;
     RECT  5.213 8.16 5.393 8.712 ;
     RECT  5.389 12.576 5.393 19.8 ;
     RECT  5.213 9.744 5.411 9.768 ;
     RECT  5.315 35.712 5.411 37.848 ;
     RECT  5.321 34.128 5.429 34.344 ;
     RECT  5.267 63.792 5.459 63.864 ;
     RECT  4.925 11.136 5.461 11.496 ;
     RECT  5.393 8.16 5.465 8.52 ;
     RECT  4.988 28.128 5.501 31.416 ;
     RECT  5.356 40.176 5.573 42.552 ;
     RECT  5.141 56.976 5.605 61.224 ;
     RECT  5.267 62.352 5.605 62.712 ;
     RECT  5.393 12.864 5.677 19.8 ;
     RECT  4.547 20.928 5.677 21.096 ;
     RECT  5.365 6.192 5.701 6.84 ;
     RECT  5.411 35.712 5.701 37.656 ;
     RECT  5.429 34.128 5.747 34.2 ;
     RECT  5.501 29.568 5.753 31.416 ;
     RECT  4.709 33.072 5.753 33.096 ;
     RECT  5.701 5.616 5.789 6.84 ;
     RECT  5.753 29.616 5.789 31.416 ;
     RECT  5.317 44.448 5.789 52.872 ;
     RECT  5.789 6.192 5.965 6.84 ;
     RECT  5.501 28.128 5.965 28.44 ;
     RECT  5.789 44.448 5.969 48.984 ;
     RECT  5.213 54.144 6.109 54.408 ;
     RECT  5.789 50.064 6.113 52.872 ;
     RECT  6.109 54.144 6.325 54.696 ;
     RECT  5.965 6.192 6.329 6.984 ;
     RECT  6.113 50.064 6.329 52.44 ;
     RECT  5.177 22.272 6.361 26.664 ;
     RECT  5.965 27.84 6.361 28.44 ;
     RECT  5.459 63.792 6.373 63.816 ;
     RECT  5.677 12.864 6.397 21.096 ;
     RECT  6.361 22.272 6.397 28.44 ;
     RECT  5.969 44.448 6.428 46.92 ;
     RECT  5.605 56.976 6.437 62.712 ;
     RECT  5.461 10.8 6.469 11.496 ;
     RECT  5.573 40.368 6.469 42.552 ;
     RECT  6.428 44.064 6.515 46.92 ;
     RECT  5.965 4.752 6.541 4.776 ;
     RECT  5.465 8.496 6.541 8.52 ;
     RECT  6.541 7.968 6.577 8.52 ;
     RECT  6.397 12.816 6.581 21.096 ;
     RECT  6.397 22.176 6.649 28.44 ;
     RECT  5.789 30.816 6.653 31.416 ;
     RECT  6.581 14.496 6.721 21.096 ;
     RECT  6.329 6.192 6.757 6.216 ;
     RECT  6.649 22.176 6.793 28.584 ;
     RECT  5.789 29.616 6.793 29.784 ;
     RECT  6.469 40.368 6.829 42.6 ;
     RECT  6.437 56.976 6.829 58.68 ;
     RECT  5.701 35.424 6.86 37.656 ;
     RECT  5.747 34.128 6.893 34.152 ;
     RECT  6.329 50.064 6.901 52.344 ;
     RECT  6.721 14.496 6.937 21.144 ;
     RECT  6.793 22.176 6.937 29.784 ;
     RECT  6.829 56.496 6.937 58.68 ;
     RECT  6.937 14.496 6.997 29.784 ;
     RECT  6.829 39.6 7.009 42.6 ;
     RECT  6.325 53.52 7.053 54.696 ;
     RECT  6.937 55.824 7.053 58.68 ;
     RECT  6.515 44.448 7.093 46.92 ;
     RECT  5.969 48.192 7.093 48.984 ;
     RECT  6.469 10.608 7.117 11.496 ;
     RECT  6.437 59.76 7.153 62.712 ;
     RECT  6.373 63.744 7.153 63.816 ;
     RECT  6.901 2.784 7.189 3.144 ;
     RECT  7.153 59.76 7.189 63.816 ;
     RECT  7.189 59.76 7.225 63.864 ;
     RECT  7.009 38.688 7.297 42.6 ;
     RECT  7.093 44.448 7.381 48.984 ;
     RECT  6.901 50.016 7.381 52.344 ;
     RECT  7.117 10.608 7.441 11.736 ;
     RECT  6.577 7.872 7.477 8.52 ;
     RECT  6.893 34.128 7.513 34.2 ;
     RECT  6.86 35.376 7.513 37.656 ;
     RECT  7.441 10.368 7.525 11.736 ;
     RECT  6.581 12.816 7.525 13.512 ;
     RECT  7.053 53.52 7.525 58.68 ;
     RECT  7.525 53.52 7.549 58.728 ;
     RECT  7.225 59.76 7.549 64.68 ;
     RECT  7.525 10.368 7.621 13.512 ;
     RECT  6.997 14.496 7.621 29.832 ;
     RECT  7.621 10.368 7.657 29.832 ;
     RECT  6.653 31.392 7.657 31.416 ;
     RECT  6.757 5.808 7.765 6.216 ;
     RECT  6.757 33.072 7.765 33.096 ;
     RECT  7.549 53.52 7.801 64.68 ;
     RECT  7.189 2.784 7.808 3.432 ;
     RECT  6.541 4.512 7.808 4.776 ;
     RECT  7.765 5.808 7.808 6.648 ;
     RECT  7.477 7.872 7.808 8.952 ;
     RECT  7.657 10.368 7.808 31.416 ;
     RECT  7.765 32.784 7.808 33.096 ;
     RECT  7.513 34.128 7.808 37.656 ;
     RECT  7.297 38.688 7.808 43.32 ;
     RECT  7.381 44.448 7.808 52.344 ;
     RECT  7.801 53.328 7.808 64.68 ;
     RECT  7.808 2.148 7.912 64.68 ;
     RECT  7.912 2.256 8.104 64.68 ;
     RECT  8.104 10.368 8.165 13.224 ;
     RECT  8.104 2.256 8.531 6.216 ;
     RECT  8.531 2.256 8.597 3.72 ;
     RECT  8.165 10.368 8.597 11.448 ;
     RECT  8.597 2.256 8.723 3.432 ;
     RECT  8.723 3.12 8.777 3.432 ;
     RECT  8.104 47.856 8.867 64.68 ;
     RECT  8.531 5.664 8.885 6.216 ;
     RECT  8.104 14.208 8.963 39.048 ;
     RECT  8.104 8.928 8.993 8.952 ;
     RECT  8.165 12.48 9.097 13.224 ;
     RECT  8.963 14.208 9.097 28.584 ;
     RECT  8.104 40.032 9.097 46.632 ;
     RECT  8.867 47.856 9.097 55.416 ;
     RECT  9.097 40.032 9.155 55.416 ;
     RECT  8.885 6 9.241 6.216 ;
     RECT  9.241 6 9.253 6.648 ;
     RECT  9.155 40.032 9.299 49.8 ;
     RECT  9.155 51.072 9.299 55.416 ;
     RECT  8.867 56.448 9.353 64.68 ;
     RECT  9.253 6 9.385 6.792 ;
     RECT  9.299 52.944 9.389 55.416 ;
     RECT  8.963 29.616 9.425 39.048 ;
     RECT  9.353 58.416 9.425 64.68 ;
     RECT  8.597 10.656 9.493 11.448 ;
     RECT  9.097 12.48 9.493 28.584 ;
     RECT  9.299 40.032 9.497 49.704 ;
     RECT  9.425 58.56 9.533 64.68 ;
     RECT  9.389 52.992 9.569 55.416 ;
     RECT  9.493 10.656 9.601 28.584 ;
     RECT  9.385 6 9.637 6.888 ;
     RECT  9.493 7.92 9.637 8.856 ;
     RECT  9.637 6 9.713 8.856 ;
     RECT  9.497 40.032 9.713 49.512 ;
     RECT  8.777 3.12 9.925 3.336 ;
     RECT  9.713 6 9.961 8.568 ;
     RECT  9.601 10.224 10.117 28.584 ;
     RECT  9.425 29.616 10.117 38.904 ;
     RECT  9.961 5.04 10.177 8.568 ;
     RECT  10.117 10.224 10.181 38.904 ;
     RECT  9.925 2.736 10.213 3.336 ;
     RECT  9.713 40.032 10.253 48.984 ;
     RECT  10.181 24.096 10.325 38.904 ;
     RECT  10.325 24.384 10.361 38.904 ;
     RECT  9.569 52.992 10.403 54.84 ;
     RECT  10.181 10.224 10.499 23.064 ;
     RECT  9.299 51.072 10.505 51.912 ;
     RECT  9.533 58.56 10.505 64.632 ;
     RECT  10.505 60.768 10.597 64.632 ;
     RECT  10.499 10.224 10.609 22.872 ;
     RECT  10.403 53.04 10.645 54.84 ;
     RECT  9.353 56.448 10.645 57.288 ;
     RECT  10.645 56.256 10.655 57.288 ;
     RECT  10.505 58.56 10.655 59.784 ;
     RECT  10.505 51.072 10.717 51.336 ;
     RECT  10.645 53.04 10.717 54.936 ;
     RECT  10.655 56.256 10.739 59.784 ;
     RECT  10.597 60.768 10.739 64.68 ;
     RECT  10.361 24.432 10.741 38.904 ;
     RECT  10.739 56.256 10.748 58.68 ;
     RECT  10.213 2.736 10.757 3.384 ;
     RECT  10.253 40.32 10.789 48.984 ;
     RECT  10.748 56.112 10.789 58.68 ;
     RECT  10.177 4.656 10.861 8.568 ;
     RECT  10.609 10.08 10.861 22.872 ;
     RECT  10.789 40.32 10.883 49.608 ;
     RECT  10.717 53.04 10.897 54.984 ;
     RECT  10.789 56.016 10.897 58.68 ;
     RECT  10.741 24.432 10.973 38.952 ;
     RECT  10.861 4.656 11.045 22.872 ;
     RECT  11.045 4.656 11.117 16.872 ;
     RECT  10.883 40.32 11.225 49.08 ;
     RECT  10.973 32.592 11.257 38.952 ;
     RECT  11.225 40.32 11.257 44.376 ;
     RECT  10.717 50.88 11.293 51.336 ;
     RECT  11.045 18.144 11.297 22.872 ;
     RECT  11.293 50.592 11.365 51.336 ;
     RECT  11.225 45.552 11.405 49.08 ;
     RECT  10.897 53.04 11.405 58.68 ;
     RECT  11.257 32.592 11.441 44.376 ;
     RECT  11.405 45.696 11.459 49.08 ;
     RECT  11.405 53.04 11.513 56.856 ;
     RECT  11.117 4.944 11.549 16.872 ;
     RECT  11.513 54.192 11.585 56.856 ;
     RECT  11.585 55.632 11.699 56.856 ;
     RECT  10.973 24.432 11.941 31.608 ;
     RECT  11.365 50.352 11.941 51.336 ;
     RECT  11.513 53.04 11.941 53.064 ;
     RECT  11.441 32.592 11.945 42.312 ;
     RECT  11.699 55.92 11.981 56.856 ;
     RECT  11.459 46.128 12.085 49.08 ;
     RECT  11.617 59.856 12.092 59.88 ;
     RECT  10.757 2.736 12.188 3.336 ;
     RECT  11.945 32.592 12.197 37.512 ;
     RECT  11.549 5.376 12.227 16.872 ;
     RECT  12.188 2.736 12.229 4.104 ;
     RECT  11.297 19.056 12.229 22.872 ;
     RECT  11.941 23.856 12.229 31.608 ;
     RECT  11.405 57.84 12.229 58.68 ;
     RECT  12.197 35.424 12.233 37.512 ;
     RECT  11.981 56.016 12.409 56.856 ;
     RECT  12.229 57.84 12.409 58.728 ;
     RECT  12.092 59.856 12.409 60.072 ;
     RECT  12.227 5.808 12.517 16.872 ;
     RECT  12.409 56.016 12.553 60.072 ;
     RECT  10.739 61.056 12.553 64.68 ;
     RECT  12.517 5.808 12.565 17.208 ;
     RECT  12.229 19.056 12.565 31.608 ;
     RECT  12.085 46.128 12.757 49.128 ;
     RECT  12.229 2.256 12.769 4.104 ;
     RECT  11.945 38.592 12.805 42.312 ;
     RECT  11.441 43.296 12.805 44.376 ;
     RECT  11.941 50.352 12.913 53.064 ;
     RECT  11.585 54.192 12.913 54.408 ;
     RECT  12.913 50.352 12.949 54.408 ;
     RECT  12.565 5.808 13.045 31.608 ;
     RECT  12.197 32.592 13.045 34.104 ;
     RECT  12.757 46.08 13.093 49.128 ;
     RECT  12.949 50.112 13.093 54.744 ;
     RECT  12.805 38.592 13.129 44.376 ;
     RECT  13.093 45.696 13.129 54.744 ;
     RECT  12.769 2.256 13.208 4.776 ;
     RECT  13.045 5.808 13.208 34.104 ;
     RECT  12.233 35.424 13.208 37.368 ;
     RECT  13.129 38.592 13.208 54.744 ;
     RECT  12.553 56.016 13.208 64.68 ;
     RECT  13.208 2.148 13.312 64.68 ;
     RECT  13.312 2.256 13.504 64.68 ;
     RECT  13.504 2.256 13.619 23.208 ;
     RECT  13.504 50.064 13.681 60.456 ;
     RECT  13.681 54.72 13.715 60.456 ;
     RECT  13.619 2.256 13.781 12.84 ;
     RECT  13.781 5.328 13.811 12.84 ;
     RECT  13.504 24.48 13.817 49.08 ;
     RECT  13.504 61.44 13.859 64.68 ;
     RECT  13.619 13.824 13.955 23.208 ;
     RECT  13.955 13.824 14.141 23.112 ;
     RECT  13.811 5.328 14.177 7.944 ;
     RECT  14.141 19.344 14.285 23.112 ;
     RECT  13.859 61.584 14.291 64.68 ;
     RECT  13.811 9.024 14.393 12.84 ;
     RECT  14.285 19.344 14.393 20.328 ;
     RECT  14.393 11.136 14.465 12.84 ;
     RECT  14.285 21.456 14.465 23.112 ;
     RECT  13.715 57.024 14.465 60.456 ;
     RECT  13.817 24.48 14.497 48.984 ;
     RECT  14.497 24.384 14.537 48.984 ;
     RECT  14.465 57.024 14.627 58.776 ;
     RECT  14.537 38.4 14.645 48.984 ;
     RECT  14.465 11.376 14.749 12.84 ;
     RECT  14.141 13.824 14.749 18.168 ;
     RECT  14.627 57.024 14.753 58.68 ;
     RECT  13.715 54.72 14.785 55.944 ;
     RECT  14.753 57.024 14.785 58.536 ;
     RECT  13.681 50.064 14.821 53.688 ;
     RECT  14.785 54.72 14.821 58.536 ;
     RECT  14.291 61.584 14.821 63.528 ;
     RECT  14.645 46.272 14.857 48.984 ;
     RECT  14.821 50.064 14.857 58.536 ;
     RECT  14.537 30.336 14.861 37.368 ;
     RECT  14.645 38.4 14.861 45.288 ;
     RECT  14.393 9.024 14.969 10.008 ;
     RECT  14.861 38.4 14.977 45.048 ;
     RECT  14.465 22.032 15.005 23.112 ;
     RECT  13.781 2.256 15.145 4.152 ;
     RECT  14.177 5.328 15.145 7.848 ;
     RECT  14.537 24.384 15.157 29.064 ;
     RECT  15.157 23.808 15.244 29.064 ;
     RECT  14.821 61.44 15.289 63.528 ;
     RECT  14.291 64.56 15.289 64.68 ;
     RECT  15.145 2.256 15.293 7.848 ;
     RECT  15.293 4.464 15.329 7.848 ;
     RECT  15.329 5.04 15.361 7.848 ;
     RECT  14.749 11.376 15.509 18.168 ;
     RECT  15.293 2.256 15.581 3.336 ;
     RECT  15.509 17.472 15.613 18.168 ;
     RECT  14.393 19.44 15.613 20.328 ;
     RECT  15.289 61.44 15.613 64.68 ;
     RECT  15.581 2.256 15.617 2.856 ;
     RECT  14.969 9.36 15.637 10.008 ;
     RECT  15.637 9.36 15.649 10.248 ;
     RECT  15.509 11.376 15.649 16.392 ;
     RECT  14.857 46.272 15.781 58.536 ;
     RECT  15.617 2.832 15.797 2.856 ;
     RECT  15.244 24.192 15.865 29.064 ;
     RECT  14.861 30.384 15.865 37.368 ;
     RECT  15.781 46.224 15.865 58.536 ;
     RECT  15.613 61.44 15.941 64.776 ;
     RECT  15.865 24.192 15.973 37.368 ;
     RECT  14.977 38.4 15.973 44.568 ;
     RECT  15.865 46.224 15.973 58.776 ;
     RECT  14.465 59.76 15.973 60.456 ;
     RECT  15.973 46.224 16.081 60.456 ;
     RECT  15.005 22.032 16.104 22.776 ;
     RECT  15.649 9.36 16.193 16.392 ;
     RECT  16.193 9.36 16.213 10.44 ;
     RECT  16.081 46.032 16.213 60.456 ;
     RECT  15.941 61.44 16.213 63.768 ;
     RECT  16.213 9.312 16.259 10.44 ;
     RECT  15.973 24.192 16.301 44.568 ;
     RECT  16.213 46.032 16.307 63.768 ;
     RECT  16.259 9.312 16.373 10.008 ;
     RECT  16.307 46.032 16.445 60.408 ;
     RECT  15.613 17.472 16.481 20.328 ;
     RECT  16.373 9.36 16.553 10.008 ;
     RECT  16.445 46.032 16.553 58.824 ;
     RECT  16.481 19.344 16.585 20.328 ;
     RECT  16.301 43.92 16.657 44.568 ;
     RECT  16.553 46.032 16.657 58.776 ;
     RECT  16.657 43.92 16.661 58.776 ;
     RECT  16.652 3.36 16.739 3.384 ;
     RECT  16.585 19.344 16.796 20.712 ;
     RECT  16.104 22.032 16.796 23.16 ;
     RECT  16.301 24.192 16.979 42.648 ;
     RECT  16.307 61.632 17.017 63.768 ;
     RECT  15.941 64.752 17.017 64.776 ;
     RECT  16.193 11.616 17.077 16.392 ;
     RECT  16.481 17.472 17.077 18.36 ;
     RECT  16.796 19.344 17.089 23.16 ;
     RECT  16.979 24.192 17.089 39.048 ;
     RECT  15.361 5.04 17.273 8.184 ;
     RECT  17.273 5.04 17.381 7.176 ;
     RECT  16.661 43.92 17.453 58.68 ;
     RECT  17.077 11.616 17.461 18.36 ;
     RECT  17.089 19.344 17.461 39.048 ;
     RECT  17.453 43.92 17.489 44.472 ;
     RECT  16.445 59.856 17.521 60.408 ;
     RECT  17.017 61.632 17.521 64.776 ;
     RECT  17.461 11.616 17.555 39.048 ;
     RECT  16.979 40.032 17.557 42.648 ;
     RECT  17.489 43.92 17.557 43.944 ;
     RECT  17.557 40.032 17.603 43.944 ;
     RECT  17.555 11.616 17.629 38.808 ;
     RECT  17.453 45.744 17.653 58.68 ;
     RECT  17.521 59.856 17.653 64.776 ;
     RECT  16.553 9.888 17.809 10.008 ;
     RECT  17.629 11.184 17.809 38.808 ;
     RECT  17.273 8.16 18.277 8.184 ;
     RECT  17.381 5.712 18.373 7.176 ;
     RECT  18.277 8.16 18.373 8.568 ;
     RECT  17.809 9.888 18.421 38.808 ;
     RECT  17.603 40.032 18.449 43.32 ;
     RECT  18.421 9.84 18.469 38.808 ;
     RECT  17.917 4.512 18.608 4.536 ;
     RECT  18.373 5.712 18.608 8.808 ;
     RECT  18.469 9.792 18.608 38.808 ;
     RECT  18.449 39.984 18.608 43.32 ;
     RECT  17.653 45.744 18.608 64.776 ;
     RECT  18.608 2.148 18.712 64.776 ;
     RECT  18.712 2.418 18.803 64.776 ;
     RECT  18.803 2.418 18.904 62.76 ;
     RECT  18.904 2.736 19.001 3.432 ;
     RECT  18.904 46.368 19.001 62.76 ;
     RECT  18.904 5.136 19.037 45.048 ;
     RECT  19.037 5.136 19.043 24.312 ;
     RECT  19.001 46.368 19.043 62.52 ;
     RECT  19.001 2.736 19.253 3.336 ;
     RECT  18.803 63.792 19.289 64.776 ;
     RECT  19.043 5.136 19.475 17.64 ;
     RECT  19.037 25.296 19.685 45.048 ;
     RECT  19.289 63.84 19.763 64.776 ;
     RECT  19.475 9.696 19.765 17.64 ;
     RECT  19.475 5.136 19.804 8.28 ;
     RECT  19.685 25.296 19.907 40.056 ;
     RECT  19.765 9.888 19.955 17.64 ;
     RECT  19.763 64.416 19.955 64.776 ;
     RECT  19.043 18.672 20.005 24.312 ;
     RECT  19.907 25.296 20.005 39.912 ;
     RECT  19.043 46.752 20.101 62.52 ;
     RECT  19.804 5.136 20.153 8.184 ;
     RECT  20.101 46.032 20.189 62.52 ;
     RECT  20.189 54.72 20.261 62.52 ;
     RECT  20.005 18.672 20.291 39.912 ;
     RECT  19.253 2.736 20.329 2.76 ;
     RECT  20.291 18.672 20.405 39.528 ;
     RECT  20.329 2.736 20.437 3.384 ;
     RECT  20.405 18.672 20.437 20.04 ;
     RECT  20.437 2.496 20.653 3.384 ;
     RECT  20.495 4.368 20.653 4.392 ;
     RECT  19.685 41.04 20.725 45.048 ;
     RECT  20.189 46.032 20.725 53.64 ;
     RECT  19.955 9.936 20.765 17.64 ;
     RECT  20.765 9.984 20.773 17.64 ;
     RECT  20.437 18.624 20.773 20.04 ;
     RECT  20.153 5.472 20.833 8.184 ;
     RECT  20.725 40.992 20.869 53.64 ;
     RECT  20.869 40.896 21.013 53.64 ;
     RECT  20.261 54.72 21.089 62.232 ;
     RECT  19.955 64.464 21.193 64.776 ;
     RECT  21.089 54.72 21.244 62.184 ;
     RECT  21.193 63.84 21.253 64.776 ;
     RECT  20.405 21.072 21.301 39.528 ;
     RECT  21.013 40.512 21.301 53.64 ;
     RECT  21.253 63.744 21.587 64.776 ;
     RECT  21.301 21.072 21.637 53.64 ;
     RECT  21.637 21.072 21.733 53.688 ;
     RECT  21.244 54.72 21.733 59.448 ;
     RECT  20.653 2.496 21.773 4.392 ;
     RECT  20.833 5.472 21.773 8.664 ;
     RECT  20.773 9.984 21.805 20.04 ;
     RECT  21.733 21.072 21.805 59.448 ;
     RECT  21.587 63.84 21.875 64.776 ;
     RECT  21.875 63.888 21.971 64.776 ;
     RECT  21.805 9.984 22.133 59.448 ;
     RECT  21.244 60.528 22.277 62.184 ;
     RECT  21.773 5.856 22.309 8.664 ;
     RECT  22.277 60.528 22.313 61.992 ;
     RECT  22.313 60.528 22.381 61.752 ;
     RECT  21.773 2.496 22.421 4.056 ;
     RECT  21.971 64.512 22.547 64.776 ;
     RECT  22.309 5.856 22.549 8.76 ;
     RECT  22.421 2.88 22.565 4.056 ;
     RECT  22.547 64.656 22.745 64.776 ;
     RECT  22.549 5.856 22.769 8.856 ;
     RECT  22.133 9.984 22.769 20.088 ;
     RECT  22.565 3.36 22.777 4.056 ;
     RECT  22.133 21.072 22.889 59.448 ;
     RECT  22.777 3.36 22.925 4.728 ;
     RECT  22.925 3.36 22.961 4.584 ;
     RECT  22.745 64.704 23.177 64.776 ;
     RECT  22.889 46.08 23.317 59.448 ;
     RECT  22.381 60.432 23.317 61.752 ;
     RECT  22.769 5.856 23.533 20.088 ;
     RECT  22.889 21.072 23.533 45 ;
     RECT  23.317 46.08 23.857 61.752 ;
     RECT  22.961 4.032 23.965 4.584 ;
     RECT  23.533 5.856 23.965 45 ;
     RECT  23.965 4.032 24.008 45 ;
     RECT  23.857 46.08 24.008 62.184 ;
     RECT  24.008 2.148 24.112 62.652 ;
     RECT  24.112 2.256 24.304 62.382 ;
     RECT  24.304 3.6 24.467 61.992 ;
     RECT  24.467 3.6 24.689 43.128 ;
     RECT  24.689 5.088 24.797 43.128 ;
     RECT  24.797 5.712 24.851 43.128 ;
     RECT  24.467 44.112 25.091 61.992 ;
     RECT  24.851 10.416 25.373 43.128 ;
     RECT  23.177 64.752 25.373 64.776 ;
     RECT  24.649 1.152 25.405 1.176 ;
     RECT  24.304 2.256 25.405 2.28 ;
     RECT  25.405 1.152 25.523 2.28 ;
     RECT  25.523 1.152 25.619 1.176 ;
     RECT  25.373 38.208 25.667 43.128 ;
     RECT  24.689 3.6 25.693 3.864 ;
     RECT  25.523 2.256 25.729 2.28 ;
     RECT  25.693 3.6 25.729 4.296 ;
     RECT  25.729 2.256 25.765 4.296 ;
     RECT  25.765 2.256 25.769 4.392 ;
     RECT  25.667 42 25.801 43.128 ;
     RECT  25.091 44.112 25.801 45 ;
     RECT  25.373 10.416 25.805 37.224 ;
     RECT  25.769 2.784 25.945 4.392 ;
     RECT  24.851 5.712 25.945 9.384 ;
     RECT  25.829 64.656 25.957 64.68 ;
     RECT  25.945 2.784 26.101 9.384 ;
     RECT  25.805 10.416 26.101 21.096 ;
     RECT  25.801 42 26.125 45 ;
     RECT  25.091 46.224 26.125 61.992 ;
     RECT  26.053 63.216 26.201 63.24 ;
     RECT  25.957 64.608 26.377 64.68 ;
     RECT  25.805 22.272 26.525 37.224 ;
     RECT  26.525 22.464 26.669 37.224 ;
     RECT  26.669 22.656 26.732 37.224 ;
     RECT  25.667 38.208 26.732 41.016 ;
     RECT  26.732 22.656 26.773 41.016 ;
     RECT  26.125 42 26.773 61.992 ;
     RECT  26.773 22.656 27.065 61.992 ;
     RECT  26.101 2.784 27.205 21.096 ;
     RECT  27.205 2.784 27.385 21.192 ;
     RECT  27.065 44.112 27.497 61.992 ;
     RECT  27.497 59.088 27.565 61.992 ;
     RECT  27.385 2.784 27.644 21.24 ;
     RECT  27.065 22.656 27.644 43.128 ;
     RECT  27.644 2.784 28.165 43.128 ;
     RECT  28.165 2.256 28.253 43.128 ;
     RECT  28.253 2.784 28.405 43.128 ;
     RECT  27.497 44.112 28.405 58.104 ;
     RECT  28.405 2.784 28.501 58.104 ;
     RECT  27.565 59.088 28.501 62.424 ;
     RECT  26.377 63.84 28.513 64.68 ;
     RECT  28.501 2.784 29.029 62.424 ;
     RECT  28.513 63.84 29.029 63.96 ;
     RECT  29.029 2.784 29.408 63.96 ;
     RECT  29.408 2.148 29.512 63.96 ;
     RECT  29.512 2.418 29.681 63.96 ;
     RECT  29.681 2.418 29.704 64.632 ;
     RECT  29.704 60.72 29.747 64.632 ;
     RECT  29.747 64.464 29.797 64.632 ;
     RECT  29.704 2.64 29.945 59.736 ;
     RECT  29.747 60.72 30.053 63.24 ;
     RECT  30.053 63.216 30.485 63.24 ;
     RECT  29.945 23.136 30.757 59.736 ;
     RECT  30.053 60.72 30.757 61.992 ;
     RECT  29.945 2.64 30.809 22.056 ;
     RECT  29.797 64.464 30.841 64.68 ;
     RECT  30.809 2.64 30.989 6.648 ;
     RECT  30.809 7.728 31.045 22.056 ;
     RECT  30.757 23.136 31.045 61.992 ;
     RECT  31.045 7.728 31.129 61.992 ;
     RECT  31.129 7.728 31.235 62.184 ;
     RECT  30.989 2.64 31.285 2.664 ;
     RECT  31.285 2.256 31.331 2.664 ;
     RECT  30.989 3.984 31.331 6.648 ;
     RECT  31.331 4.368 31.709 6.648 ;
     RECT  31.235 61.488 32.005 62.184 ;
     RECT  31.331 2.256 32.141 2.28 ;
     RECT  31.235 7.728 32.245 60.456 ;
     RECT  32.245 7.104 32.281 60.456 ;
     RECT  32.005 61.488 32.281 62.232 ;
     RECT  32.281 7.104 32.425 62.232 ;
     RECT  32.425 7.104 32.461 62.664 ;
     RECT  30.841 63.84 32.461 64.68 ;
     RECT  32.461 7.104 32.537 64.68 ;
     RECT  32.537 7.104 32.789 42.984 ;
     RECT  31.709 4.368 32.929 5.784 ;
     RECT  32.789 7.104 32.929 42.6 ;
     RECT  32.537 44.208 33.221 64.68 ;
     RECT  33.289 2.304 33.541 2.328 ;
     RECT  33.469 3.36 33.541 3.384 ;
     RECT  32.929 4.368 33.541 42.6 ;
     RECT  33.221 44.208 33.644 61.512 ;
     RECT  33.644 43.728 33.731 61.512 ;
     RECT  33.731 44.256 34.225 61.512 ;
     RECT  33.221 62.688 34.225 64.68 ;
     RECT  33.541 2.304 34.364 42.6 ;
     RECT  34.364 2.304 34.808 42.744 ;
     RECT  34.225 44.256 34.808 64.68 ;
     RECT  34.808 2.148 34.912 64.68 ;
     RECT  34.912 2.418 35.104 64.68 ;
     RECT  35.104 43.872 35.245 64.68 ;
     RECT  35.245 44.352 35.353 64.68 ;
     RECT  35.353 44.352 36.083 64.632 ;
     RECT  36.083 44.352 36.209 62.712 ;
     RECT  36.083 63.744 36.353 64.632 ;
     RECT  36.209 44.352 36.457 62.28 ;
     RECT  35.104 2.784 36.469 42.84 ;
     RECT  36.457 43.872 36.469 62.28 ;
     RECT  36.469 2.784 36.569 62.28 ;
     RECT  36.569 20.16 36.929 62.28 ;
     RECT  36.929 20.16 36.995 61.944 ;
     RECT  36.995 20.16 37.109 53.592 ;
     RECT  36.353 63.84 37.285 64.632 ;
     RECT  36.995 54.624 37.361 61.944 ;
     RECT  36.569 2.784 37.505 19.128 ;
     RECT  37.505 4.512 37.957 19.128 ;
     RECT  37.109 20.496 38.077 53.496 ;
     RECT  37.361 54.624 38.077 60.888 ;
     RECT  37.957 4.512 38.101 19.368 ;
     RECT  38.077 20.496 38.101 60.888 ;
     RECT  38.101 4.512 38.225 60.888 ;
     RECT  37.285 63.84 38.533 64.68 ;
     RECT  37.505 2.784 38.581 3.096 ;
     RECT  38.533 63.792 38.621 64.68 ;
     RECT  38.621 63.792 38.675 63.864 ;
     RECT  38.225 4.704 38.773 60.888 ;
     RECT  37.361 61.872 38.773 61.944 ;
     RECT  38.581 2.784 39.017 3.432 ;
     RECT  38.773 4.704 39.017 61.944 ;
     RECT  39.017 2.832 39.301 3.432 ;
     RECT  38.675 63.792 39.557 63.816 ;
     RECT  39.017 4.704 40.069 61.032 ;
     RECT  39.301 2.832 40.165 3.576 ;
     RECT  40.165 2.544 40.208 3.576 ;
     RECT  40.069 4.656 40.208 61.032 ;
     RECT  39.949 62.448 40.208 62.472 ;
     RECT  40.208 2.148 40.312 62.652 ;
     RECT  40.312 2.256 40.643 62.472 ;
     RECT  40.643 38.448 40.78 62.472 ;
     RECT  40.643 2.88 40.817 3.144 ;
     RECT  40.78 38.784 41.357 62.472 ;
     RECT  41.357 45.168 41.452 62.472 ;
     RECT  41.452 45.168 41.501 61.176 ;
     RECT  41.357 38.784 41.537 43.608 ;
     RECT  40.643 4.224 41.605 36.984 ;
     RECT  41.605 4.224 41.689 37.128 ;
     RECT  41.452 62.448 41.713 62.472 ;
     RECT  41.065 63.504 41.713 63.528 ;
     RECT  40.817 3.12 41.785 3.144 ;
     RECT  41.689 4.224 41.785 37.08 ;
     RECT  41.785 3.12 41.891 37.08 ;
     RECT  41.537 38.784 41.893 43.56 ;
     RECT  41.891 3.12 41.929 4.584 ;
     RECT  41.929 2.976 41.965 4.584 ;
     RECT  41.893 38.544 42.181 43.56 ;
     RECT  41.965 2.88 42.217 4.584 ;
     RECT  41.501 60.24 42.469 61.176 ;
     RECT  41.713 62.448 42.469 63.528 ;
     RECT  42.181 38.208 42.659 43.56 ;
     RECT  41.501 45.168 42.793 59.16 ;
     RECT  42.659 38.784 42.829 43.56 ;
     RECT  42.793 45.024 42.937 59.16 ;
     RECT  42.469 60.24 42.937 63.528 ;
     RECT  41.891 5.712 43.013 37.08 ;
     RECT  43.013 6 43.045 37.08 ;
     RECT  43.045 6 43.049 37.608 ;
     RECT  42.217 2.304 43.139 4.584 ;
     RECT  42.937 45.024 43.225 63.528 ;
     RECT  43.049 6.048 43.265 37.608 ;
     RECT  42.829 38.784 43.297 43.704 ;
     RECT  43.225 44.928 43.297 63.528 ;
     RECT  43.297 38.784 43.331 63.528 ;
     RECT  43.139 3.936 43.445 4.584 ;
     RECT  43.265 6.288 43.769 37.608 ;
     RECT  43.769 6.912 44.149 37.608 ;
     RECT  43.331 38.784 44.149 61.752 ;
     RECT  43.139 2.304 44.309 2.904 ;
     RECT  44.309 2.496 44.485 2.904 ;
     RECT  44.149 6.912 44.809 61.752 ;
     RECT  44.809 6.72 45.013 61.752 ;
     RECT  43.331 62.928 45.025 63.528 ;
     RECT  45.025 62.784 45.457 63.528 ;
     RECT  45.205 64.656 45.457 64.68 ;
     RECT  44.485 2.496 45.565 3.048 ;
     RECT  45.013 6.24 45.601 61.752 ;
     RECT  45.457 62.784 45.601 64.68 ;
     RECT  45.565 2.496 45.608 3.336 ;
     RECT  43.445 4.416 45.608 4.584 ;
     RECT  45.601 6.24 45.608 64.68 ;
     RECT  45.608 2.148 45.712 64.68 ;
     RECT  45.712 2.418 45.904 64.68 ;
     RECT  45.904 6.576 45.929 64.68 ;
     RECT  45.904 2.496 46.189 5.352 ;
     RECT  46.189 4.368 46.469 5.352 ;
     RECT  46.189 2.496 46.865 3.384 ;
     RECT  45.929 6.816 47.125 64.68 ;
     RECT  46.865 2.784 47.189 3.384 ;
     RECT  47.189 3.072 47.333 3.384 ;
     RECT  47.125 6.816 48.049 64.776 ;
     RECT  46.469 4.368 48.229 4.584 ;
     RECT  48.229 4.368 48.301 5.256 ;
     RECT  47.333 3.072 48.409 3.096 ;
     RECT  48.301 4.272 48.62 5.256 ;
     RECT  48.62 4.272 48.661 5.304 ;
     RECT  48.661 4.272 48.697 5.688 ;
     RECT  48.049 6.672 48.697 64.776 ;
     RECT  48.409 2.688 48.805 3.096 ;
     RECT  48.805 2.688 48.841 3.144 ;
     RECT  48.697 4.272 48.841 64.776 ;
     RECT  48.841 2.688 48.844 64.776 ;
     RECT  48.844 2.688 49.885 5.4 ;
     RECT  48.844 6.384 49.885 64.776 ;
     RECT  49.885 2.688 50.579 64.776 ;
     RECT  50.579 2.688 50.869 63.672 ;
     RECT  50.869 2.256 51.008 63.672 ;
     RECT  51.008 2.148 51.112 63.672 ;
     RECT  51.112 2.256 51.221 63.672 ;
     RECT  51.221 2.418 51.304 63.672 ;
     RECT  51.304 3.024 51.797 63.672 ;
     RECT  51.797 60.816 51.877 63.672 ;
     RECT  50.579 64.656 51.877 64.776 ;
     RECT  51.877 60.816 51.905 64.776 ;
     RECT  51.905 60.816 52.013 64.728 ;
     RECT  51.797 3.024 53.125 59.832 ;
     RECT  52.013 60.864 53.125 64.728 ;
     RECT  53.125 3.024 53.309 64.728 ;
     RECT  53.309 3.024 53.461 3.912 ;
     RECT  53.309 5.232 53.849 64.728 ;
     RECT  53.849 5.232 54.173 43.512 ;
     RECT  53.461 2.64 54.277 3.912 ;
     RECT  54.173 5.232 54.277 37.08 ;
     RECT  54.277 2.64 54.713 37.08 ;
     RECT  54.173 38.112 55.045 43.512 ;
     RECT  53.849 44.736 55.045 64.728 ;
     RECT  55.045 38.112 55.235 64.728 ;
     RECT  55.235 44.928 55.283 64.728 ;
     RECT  55.235 38.112 55.324 43.608 ;
     RECT  55.283 47.328 55.537 64.728 ;
     RECT  54.713 2.736 55.573 37.08 ;
     RECT  55.324 38.112 55.573 43.56 ;
     RECT  55.573 2.736 56.365 43.56 ;
     RECT  55.283 44.928 56.365 46.344 ;
     RECT  56.365 2.736 56.408 46.344 ;
     RECT  55.537 47.328 56.408 64.776 ;
     RECT  56.408 2.148 56.512 64.776 ;
     RECT  56.512 2.418 56.704 64.776 ;
     RECT  56.704 2.832 57.485 64.776 ;
     RECT  57.485 2.832 58.309 3.096 ;
     RECT  58.309 2.784 58.561 3.096 ;
     RECT  57.485 4.224 58.561 64.776 ;
     RECT  58.561 2.784 58.597 64.776 ;
     RECT  58.597 2.496 59.123 64.776 ;
     RECT  59.123 3.696 59.357 64.776 ;
     RECT  59.357 4.992 59.393 64.776 ;
     RECT  59.393 5.184 59.861 64.776 ;
     RECT  59.357 3.696 60.325 3.864 ;
     RECT  60.325 3.696 60.361 4.008 ;
     RECT  59.861 5.184 60.361 64.68 ;
     RECT  59.123 2.496 61.441 2.52 ;
     RECT  60.361 3.696 61.441 64.68 ;
     RECT  61.441 2.496 61.808 64.68 ;
     RECT  61.808 2.148 61.912 64.68 ;
     RECT  61.912 2.418 62.104 64.68 ;
     RECT  62.104 3.648 62.165 4.152 ;
     RECT  62.104 6.048 62.243 57.384 ;
     RECT  62.165 3.648 62.339 3.912 ;
     RECT  62.243 6.096 62.345 57.384 ;
     RECT  62.104 58.464 62.345 64.68 ;
     RECT  62.339 3.888 62.381 3.912 ;
     RECT  62.345 6.096 62.417 43.032 ;
     RECT  62.345 44.016 62.435 57.384 ;
     RECT  62.417 6.096 62.453 42.648 ;
     RECT  62.435 44.064 62.489 44.088 ;
     RECT  62.345 58.464 62.675 63.96 ;
     RECT  62.675 62.64 62.867 63.96 ;
     RECT  62.867 62.64 63.539 63.912 ;
     RECT  62.675 58.464 63.635 61.608 ;
     RECT  63.539 62.64 63.827 62.76 ;
     RECT  63.827 62.736 63.923 62.76 ;
     RECT  63.539 63.888 64.019 63.912 ;
     RECT  62.435 45.12 64.609 57.384 ;
     RECT  63.635 58.464 64.609 61.224 ;
     RECT  64.609 45.12 64.645 61.224 ;
     RECT  62.453 6.864 64.721 42.552 ;
     RECT  64.645 45.12 64.721 61.32 ;
     RECT  64.721 6.864 64.764 42.408 ;
     RECT  64.721 45.264 64.764 61.32 ;
    LAYER M5 ;
     RECT  25.488 0.016 25.608 1.187 ;
     RECT  25.488 1.187 25.512 1.763 ;
     RECT  2.4 2.137 2.52 2.151 ;
     RECT  7.8 2.137 7.92 2.151 ;
     RECT  13.2 2.137 13.32 2.151 ;
     RECT  18.6 2.137 18.72 2.151 ;
     RECT  24 2.137 24.12 2.151 ;
     RECT  29.4 2.137 29.52 2.151 ;
     RECT  34.8 2.137 34.92 2.151 ;
     RECT  40.2 2.137 40.32 2.151 ;
     RECT  45.6 2.137 45.72 2.151 ;
     RECT  51 2.137 51.12 2.151 ;
     RECT  56.4 2.137 56.52 2.151 ;
     RECT  61.8 2.137 61.92 2.151 ;
     RECT  7.8 2.151 8.112 2.245 ;
     RECT  13.2 2.151 13.512 2.245 ;
     RECT  40.2 2.151 40.512 2.245 ;
     RECT  51 2.151 51.312 2.245 ;
     RECT  45.6 2.151 45.912 2.485 ;
     RECT  50.88 2.245 51.312 2.677 ;
     RECT  28.176 2.245 28.2 2.819 ;
     RECT  40.2 2.245 40.632 2.821 ;
     RECT  61.8 2.151 62.112 2.821 ;
     RECT  34.8 2.151 35.112 2.869 ;
     RECT  43.104 2.293 43.128 2.869 ;
     RECT  53.472 2.629 53.496 3.061 ;
     RECT  7.8 2.245 8.712 3.109 ;
     RECT  6.912 3.109 8.712 3.155 ;
     RECT  34.8 2.869 35.832 3.155 ;
     RECT  39.312 2.821 40.632 3.397 ;
     RECT  12.24 2.245 14.28 3.443 ;
     RECT  38.592 3.397 40.632 3.443 ;
     RECT  45.6 2.485 46.152 3.443 ;
     RECT  38.592 3.443 40.512 3.587 ;
     RECT  24 2.151 24.312 3.589 ;
     RECT  61.632 2.821 62.112 3.637 ;
     RECT  61.632 3.637 62.328 3.685 ;
     RECT  24 3.589 24.6 3.829 ;
     RECT  59.088 3.397 59.112 3.829 ;
     RECT  25.776 2.821 25.8 3.877 ;
     RECT  53.472 3.061 54.36 3.923 ;
     RECT  33.744 2.293 33.768 3.925 ;
     RECT  34.8 3.155 35.112 3.925 ;
     RECT  50.4 2.677 51.312 3.925 ;
     RECT  59.088 3.829 59.64 3.925 ;
     RECT  31.296 2.245 31.32 4.019 ;
     RECT  12.24 3.443 13.512 4.115 ;
     RECT  43.104 2.869 43.368 4.115 ;
     RECT  20.544 3.157 20.568 4.213 ;
     RECT  50.4 3.925 51.576 4.213 ;
     RECT  50.112 4.213 51.576 4.261 ;
     RECT  20.544 4.213 20.76 4.403 ;
     RECT  25.776 3.877 26.76 4.403 ;
     RECT  33.744 3.925 35.112 4.403 ;
     RECT  58.656 3.925 59.64 4.451 ;
     RECT  33.792 4.403 35.112 4.453 ;
     RECT  45.6 3.443 46.104 4.453 ;
     RECT  48.336 3.061 48.36 4.453 ;
     RECT  56.4 2.151 56.712 4.453 ;
     RECT  40.08 3.587 40.512 4.501 ;
     RECT  50.112 4.261 51.864 4.501 ;
     RECT  56.4 4.453 56.808 4.501 ;
     RECT  6.912 3.155 8.52 4.691 ;
     RECT  10.8 3.301 10.824 4.691 ;
     RECT  33.792 4.453 35.928 4.693 ;
     RECT  33.792 4.693 36.984 4.741 ;
     RECT  54.336 3.923 54.36 4.979 ;
     RECT  27.984 3.637 28.008 4.981 ;
     RECT  31.152 4.981 31.176 5.029 ;
     RECT  16.704 3.349 16.728 5.075 ;
     RECT  41.664 4.549 41.688 5.077 ;
     RECT  50.112 4.501 51.912 5.077 ;
     RECT  40.08 4.501 40.632 5.219 ;
     RECT  48.336 4.453 48.792 5.219 ;
     RECT  15.312 2.821 15.336 5.269 ;
     RECT  29.4 2.151 29.712 5.269 ;
     RECT  15.312 5.269 16.296 5.315 ;
     RECT  48.672 5.219 48.792 5.315 ;
     RECT  26.064 4.403 26.76 5.317 ;
     RECT  48.72 5.315 48.792 5.365 ;
     RECT  50.112 5.077 52.68 5.365 ;
     RECT  26.064 5.317 26.808 5.461 ;
     RECT  27.936 4.981 28.008 5.461 ;
     RECT  30.816 5.029 31.32 5.461 ;
     RECT  33.792 4.741 37.56 5.461 ;
     RECT  38.592 3.587 38.616 5.461 ;
     RECT  26.064 5.461 28.008 5.557 ;
     RECT  29.088 5.269 29.712 5.557 ;
     RECT  30.768 5.461 31.32 5.603 ;
     RECT  33.792 5.461 38.616 5.603 ;
     RECT  58.704 4.451 59.64 5.605 ;
     RECT  7.8 4.691 8.52 5.653 ;
     RECT  18.6 2.151 18.912 5.701 ;
     RECT  10.704 5.029 10.728 5.747 ;
     RECT  7.8 5.653 8.856 5.797 ;
     RECT  58.608 5.605 59.64 5.797 ;
     RECT  30.816 5.603 31.32 5.843 ;
     RECT  43.344 4.115 43.368 5.989 ;
     RECT  24 3.829 24.744 6.035 ;
     RECT  40.2 5.219 40.632 6.037 ;
     RECT  41.664 5.077 41.88 6.037 ;
     RECT  5.712 5.605 5.736 6.181 ;
     RECT  54.096 5.221 54.12 6.181 ;
     RECT  55.44 4.501 56.808 6.181 ;
     RECT  45.6 4.453 46.2 6.229 ;
     RECT  5.376 6.181 5.736 6.323 ;
     RECT  43.008 5.989 43.368 6.323 ;
     RECT  26.064 5.557 29.712 6.371 ;
     RECT  31.248 5.843 31.32 6.371 ;
     RECT  54.096 6.181 56.808 6.371 ;
     RECT  60.912 3.685 62.328 6.371 ;
     RECT  54.096 6.371 56.712 6.373 ;
     RECT  22.032 6.181 22.056 6.517 ;
     RECT  22.032 6.517 22.2 6.565 ;
     RECT  57.936 5.797 59.64 6.661 ;
     RECT  60.912 6.371 62.232 6.661 ;
     RECT  26.064 6.371 28.008 6.707 ;
     RECT  22.032 6.565 22.872 6.709 ;
     RECT  36.288 5.603 38.616 6.755 ;
     RECT  6.864 5.797 8.856 6.757 ;
     RECT  5.376 6.323 5.4 6.805 ;
     RECT  20.736 4.403 20.76 6.851 ;
     RECT  53.664 6.373 56.712 6.851 ;
     RECT  38.592 6.755 38.616 6.853 ;
     RECT  40.2 6.037 41.88 6.853 ;
     RECT  22.032 6.709 22.92 6.901 ;
     RECT  21.072 6.901 22.92 7.043 ;
     RECT  21.216 7.043 22.92 7.091 ;
     RECT  24 6.035 24.6 7.141 ;
     RECT  24 7.141 24.792 7.189 ;
     RECT  38.592 6.853 41.88 7.285 ;
     RECT  43.008 6.323 43.032 7.285 ;
     RECT  2.4 2.151 2.712 7.381 ;
     RECT  57.936 6.661 62.232 7.381 ;
     RECT  21.312 7.091 22.92 7.475 ;
     RECT  26.064 6.707 27.96 7.475 ;
     RECT  48.72 5.365 52.68 7.477 ;
     RECT  12.192 5.365 12.216 7.619 ;
     RECT  45.024 6.229 46.2 7.619 ;
     RECT  16.224 5.315 16.296 7.667 ;
     RECT  57.936 7.381 62.328 7.667 ;
     RECT  29.4 6.371 29.712 7.717 ;
     RECT  31.248 6.371 31.272 7.717 ;
     RECT  6.864 6.757 9.288 7.765 ;
     RECT  13.2 4.115 13.512 7.765 ;
     RECT  38.592 7.285 43.032 7.765 ;
     RECT  24 7.189 25.032 7.811 ;
     RECT  45.6 7.619 46.2 7.861 ;
     RECT  53.664 6.851 53.688 7.861 ;
     RECT  54.816 6.851 56.712 7.861 ;
     RECT  29.4 7.717 31.272 7.957 ;
     RECT  32.256 7.093 32.28 7.957 ;
     RECT  45.6 7.861 47.112 7.957 ;
     RECT  26.112 7.475 27.96 8.003 ;
     RECT  38.592 7.765 43.944 8.003 ;
     RECT  18.6 5.701 19.704 8.005 ;
     RECT  6.864 7.765 9.864 8.051 ;
     RECT  40.08 8.003 43.944 8.147 ;
     RECT  38.592 8.003 38.808 8.195 ;
     RECT  41.568 8.147 43.944 8.197 ;
     RECT  18.384 8.005 19.704 8.245 ;
     RECT  21.648 7.475 22.92 8.245 ;
     RECT  36.288 6.755 37.176 8.389 ;
     RECT  40.08 8.147 40.512 8.483 ;
     RECT  29.136 7.957 32.28 8.485 ;
     RECT  48.48 7.477 52.68 8.485 ;
     RECT  53.664 7.861 56.712 8.485 ;
     RECT  58.128 7.667 62.328 8.485 ;
     RECT  45.6 7.957 47.16 8.531 ;
     RECT  7.8 8.051 9.864 8.579 ;
     RECT  2.4 7.381 2.952 8.723 ;
     RECT  5.136 6.805 5.4 8.723 ;
     RECT  58.128 8.485 62.376 8.773 ;
     RECT  13.2 7.765 13.8 8.867 ;
     RECT  58.128 8.773 62.424 8.869 ;
     RECT  41.568 8.197 44.472 8.963 ;
     RECT  38.784 8.195 38.808 9.059 ;
     RECT  48.48 8.485 56.712 9.061 ;
     RECT  58.032 8.869 62.424 9.061 ;
     RECT  36.288 8.389 37.464 9.109 ;
     RECT  43.92 8.963 44.472 9.203 ;
     RECT  29.088 8.485 32.28 9.251 ;
     RECT  44.352 9.203 44.472 9.251 ;
     RECT  40.2 8.483 40.512 9.253 ;
     RECT  41.568 8.963 42.264 9.253 ;
     RECT  48.48 9.061 62.424 9.253 ;
     RECT  33.792 5.603 35.112 9.301 ;
     RECT  44.352 9.251 44.376 9.443 ;
     RECT  48.48 9.253 62.712 9.443 ;
     RECT  45.6 8.531 46.44 9.493 ;
     RECT  29.088 9.251 32.232 9.587 ;
     RECT  48.624 9.443 62.712 9.637 ;
     RECT  18.384 8.245 19.752 9.877 ;
     RECT  36.288 9.109 37.56 10.021 ;
     RECT  5.376 8.723 5.4 10.069 ;
     RECT  26.112 8.003 27.192 10.069 ;
     RECT  24 7.811 24.792 10.117 ;
     RECT  21.648 8.245 22.968 10.165 ;
     RECT  24 10.117 24.84 10.165 ;
     RECT  14.88 5.989 14.904 10.213 ;
     RECT  16.224 7.667 16.248 10.213 ;
     RECT  33.792 9.301 35.208 10.213 ;
     RECT  36.24 10.021 37.56 10.213 ;
     RECT  40.2 9.253 42.264 10.261 ;
     RECT  40.2 10.261 42.744 10.403 ;
     RECT  14.88 10.213 16.248 10.451 ;
     RECT  13.2 8.867 13.512 10.453 ;
     RECT  14.88 10.451 16.056 10.453 ;
     RECT  64.608 10.453 64.632 10.643 ;
     RECT  18.384 9.877 19.944 10.693 ;
     RECT  18.336 10.693 19.944 10.789 ;
     RECT  21.648 10.165 24.84 10.789 ;
     RECT  26.112 10.069 27.288 10.789 ;
     RECT  26.112 10.789 27.432 10.837 ;
     RECT  29.088 9.587 31.176 10.837 ;
     RECT  33.792 10.213 37.56 10.837 ;
     RECT  48.624 9.637 63.24 10.883 ;
     RECT  21.36 10.789 24.84 10.933 ;
     RECT  26.112 10.837 31.176 10.933 ;
     RECT  21.36 10.933 31.176 11.123 ;
     RECT  18.336 10.789 20.04 11.125 ;
     RECT  33.792 10.837 37.752 11.269 ;
     RECT  2.4 8.723 2.712 11.365 ;
     RECT  4.8 10.069 5.4 11.365 ;
     RECT  6.48 10.597 6.504 11.365 ;
     RECT  13.2 10.453 16.056 11.411 ;
     RECT  45.6 9.493 46.872 11.413 ;
     RECT  4.8 11.365 6.504 11.459 ;
     RECT  40.2 10.403 42.216 11.653 ;
     RECT  45.024 11.413 46.872 11.749 ;
     RECT  48.72 10.883 62.664 11.845 ;
     RECT  40.2 11.653 42.744 11.891 ;
     RECT  7.8 8.579 9.528 11.941 ;
     RECT  13.2 11.411 14.904 11.987 ;
     RECT  15.888 11.411 16.056 11.989 ;
     RECT  17.904 11.125 20.04 11.989 ;
     RECT  21.36 11.123 26.184 11.989 ;
     RECT  45.024 11.749 47.448 11.989 ;
     RECT  48.48 11.845 62.664 11.989 ;
     RECT  45.024 11.989 62.664 12.035 ;
     RECT  11.856 10.645 11.88 12.181 ;
     RECT  13.2 11.987 14.232 12.181 ;
     RECT  11.856 12.181 14.232 12.227 ;
     RECT  27.264 11.123 31.176 12.275 ;
     RECT  33.792 11.269 37.8 12.277 ;
     RECT  39.024 11.653 39.048 12.277 ;
     RECT  17.904 11.989 26.184 12.325 ;
     RECT  27.264 12.275 27.912 12.325 ;
     RECT  17.904 12.325 27.912 12.419 ;
     RECT  53.712 12.035 62.664 12.421 ;
     RECT  45.024 12.035 52.68 12.469 ;
     RECT  44.976 12.469 52.68 12.515 ;
     RECT  7.536 11.941 9.528 12.517 ;
     RECT  2.304 11.365 2.712 12.563 ;
     RECT  10.752 10.213 10.776 12.755 ;
     RECT  15.888 11.989 16.2 12.755 ;
     RECT  15.984 12.755 16.2 13.045 ;
     RECT  17.904 12.419 27.432 13.045 ;
     RECT  44.976 12.515 48.936 13.045 ;
     RECT  15.984 13.045 27.432 13.091 ;
     RECT  43.872 13.045 48.936 13.091 ;
     RECT  33.792 12.277 39.048 13.139 ;
     RECT  50.16 12.515 52.68 13.139 ;
     RECT  33.792 13.139 35.208 13.283 ;
     RECT  50.256 13.139 52.68 13.285 ;
     RECT  53.712 12.421 63.24 13.285 ;
     RECT  16.176 13.091 27.432 13.331 ;
     RECT  32.208 9.587 32.232 13.381 ;
     RECT  4.8 11.459 5.88 13.475 ;
     RECT  43.872 13.091 47.832 13.571 ;
     RECT  11.856 12.227 13.608 13.573 ;
     RECT  17.568 13.331 27.432 13.619 ;
     RECT  64.608 12.805 64.632 13.619 ;
     RECT  2.4 12.563 2.712 13.621 ;
     RECT  36.24 13.139 39.048 13.621 ;
     RECT  40.2 11.891 41.928 13.621 ;
     RECT  4.8 13.475 5.688 13.907 ;
     RECT  43.872 13.571 44.088 13.907 ;
     RECT  11.328 13.573 13.608 13.957 ;
     RECT  36.24 13.621 41.928 14.005 ;
     RECT  22.848 13.619 27.432 14.197 ;
     RECT  48.912 13.091 48.936 14.197 ;
     RECT  50.256 13.285 63.24 14.197 ;
     RECT  32.208 13.381 33.048 14.291 ;
     RECT  45.6 13.571 47.832 14.291 ;
     RECT  34.176 13.283 35.208 14.389 ;
     RECT  36.24 14.005 42.792 14.389 ;
     RECT  11.328 13.957 13.752 14.531 ;
     RECT  2.304 13.621 2.712 14.677 ;
     RECT  34.176 14.389 42.792 14.677 ;
     RECT  29.088 12.275 31.176 14.771 ;
     RECT  5.04 13.907 5.688 14.773 ;
     RECT  7.536 12.517 9.576 14.773 ;
     RECT  33.936 14.677 42.792 14.773 ;
     RECT  43.872 13.907 43.944 14.773 ;
     RECT  29.136 14.771 31.176 14.821 ;
     RECT  32.208 14.291 32.424 14.821 ;
     RECT  22.848 14.197 27.768 14.867 ;
     RECT  48.912 14.197 63.24 14.867 ;
     RECT  2.304 14.677 2.904 14.963 ;
     RECT  29.136 14.821 32.424 15.011 ;
     RECT  17.568 13.619 21.72 15.013 ;
     RECT  33.936 14.773 43.944 15.059 ;
     RECT  52.656 14.867 62.424 15.107 ;
     RECT  14.784 14.725 14.808 15.205 ;
     RECT  16.176 13.331 16.2 15.205 ;
     RECT  2.4 14.963 2.904 15.251 ;
     RECT  22.848 14.867 26.424 15.251 ;
     RECT  7.536 14.773 9.768 15.301 ;
     RECT  43.248 15.059 43.944 15.301 ;
     RECT  45.6 14.291 46.152 15.301 ;
     RECT  47.28 14.291 47.832 15.301 ;
     RECT  11.952 14.531 13.752 15.347 ;
     RECT  45.6 15.301 47.832 15.349 ;
     RECT  48.912 14.867 51.432 15.349 ;
     RECT  27.744 14.867 27.768 15.491 ;
     RECT  33.936 15.059 42.216 15.587 ;
     RECT  33.936 15.587 40.632 15.733 ;
     RECT  11.952 15.347 13.608 15.827 ;
     RECT  33.648 15.733 40.632 15.827 ;
     RECT  43.248 15.301 44.424 15.877 ;
     RECT  45.6 15.349 51.432 15.877 ;
     RECT  23.712 15.251 26.424 16.019 ;
     RECT  32.4 15.011 32.424 16.019 ;
     RECT  43.248 15.877 51.432 16.021 ;
     RECT  41.904 15.587 42.216 16.069 ;
     RECT  43.248 16.021 51.576 16.069 ;
     RECT  36.24 15.827 40.632 16.115 ;
     RECT  41.904 16.069 51.672 16.307 ;
     RECT  7.536 15.301 10.728 16.357 ;
     RECT  5.04 14.773 5.736 16.499 ;
     RECT  42.192 16.307 51.672 16.499 ;
     RECT  50.736 16.499 51.672 16.501 ;
     RECT  52.656 15.107 62.112 16.501 ;
     RECT  5.04 16.499 5.592 16.547 ;
     RECT  24 16.019 26.424 16.595 ;
     RECT  42.192 16.499 49.656 16.595 ;
     RECT  50.736 16.501 62.112 16.739 ;
     RECT  17.568 15.013 21.864 16.787 ;
     RECT  39.408 16.115 40.632 16.837 ;
     RECT  14.784 15.205 16.2 17.029 ;
     RECT  17.568 16.787 21.432 17.029 ;
     RECT  51 16.739 62.112 17.029 ;
     RECT  51 17.029 62.328 17.075 ;
     RECT  33.648 15.827 35.112 17.077 ;
     RECT  43.056 16.595 49.656 17.171 ;
     RECT  5.136 16.547 5.592 17.267 ;
     RECT  59.568 17.075 62.328 17.267 ;
     RECT  24 16.595 25.368 17.315 ;
     RECT  60 17.267 62.328 17.317 ;
     RECT  7.536 16.357 10.92 17.461 ;
     RECT  27.936 17.413 27.96 17.509 ;
     RECT  33.072 17.077 35.112 17.605 ;
     RECT  51 17.075 58.2 17.699 ;
     RECT  14.784 17.029 21.432 17.747 ;
     RECT  39.408 16.837 41.208 17.989 ;
     RECT  12.72 15.827 13.608 18.037 ;
     RECT  39.408 17.989 41.88 18.037 ;
     RECT  43.056 17.171 48.744 18.037 ;
     RECT  7.344 17.461 10.92 18.133 ;
     RECT  27.888 17.509 27.96 18.421 ;
     RECT  29.136 15.011 31.32 18.421 ;
     RECT  24 17.315 25.224 18.565 ;
     RECT  26.352 16.595 26.424 18.565 ;
     RECT  51 17.699 53.352 18.565 ;
     RECT  22.752 17.509 22.776 18.613 ;
     RECT  24 18.565 26.424 18.613 ;
     RECT  27.888 18.421 31.32 18.661 ;
     RECT  60 17.317 62.376 18.661 ;
     RECT  32.832 17.605 35.112 18.709 ;
     RECT  22.752 18.613 26.424 18.755 ;
     RECT  50.064 18.565 53.352 18.757 ;
     RECT  54.336 17.699 58.2 18.757 ;
     RECT  64.608 18.517 64.632 18.803 ;
     RECT  39.408 18.037 48.744 19.235 ;
     RECT  12.576 18.037 13.608 19.285 ;
     RECT  14.784 17.747 21.096 19.333 ;
     RECT  5.136 17.267 5.16 19.427 ;
     RECT  23.136 18.755 26.424 19.525 ;
     RECT  27.888 18.661 31.848 19.525 ;
     RECT  50.064 18.757 58.2 19.669 ;
     RECT  48.432 19.235 48.744 19.717 ;
     RECT  39.408 19.235 47.352 20.003 ;
     RECT  23.136 19.525 31.848 20.053 ;
     RECT  32.832 18.709 35.256 20.053 ;
     RECT  48.432 19.717 48.936 20.149 ;
     RECT  50.064 19.669 58.92 20.149 ;
     RECT  23.136 20.053 35.256 20.627 ;
     RECT  45.6 20.003 47.352 20.627 ;
     RECT  12.576 19.285 13.752 20.725 ;
     RECT  60 18.661 62.52 20.771 ;
     RECT  26.4 20.627 35.256 20.819 ;
     RECT  12.528 20.725 13.752 20.867 ;
     RECT  48.432 20.149 58.92 20.869 ;
     RECT  60 20.771 62.232 20.869 ;
     RECT  2.4 15.251 2.712 20.965 ;
     RECT  3.888 20.485 3.912 20.965 ;
     RECT  7.2 18.133 10.92 21.061 ;
     RECT  48.432 20.869 62.232 21.155 ;
     RECT  36.24 16.115 38.376 21.253 ;
     RECT  39.408 20.003 44.472 21.253 ;
     RECT  23.136 20.627 25.224 21.637 ;
     RECT  36.24 21.253 44.472 21.779 ;
     RECT  26.4 20.819 27.96 21.973 ;
     RECT  28.944 20.819 35.256 21.973 ;
     RECT  48.528 21.155 62.232 22.021 ;
     RECT  41.856 21.779 44.472 22.115 ;
     RECT  12.528 20.867 13.704 22.165 ;
     RECT  45.6 20.627 47.304 22.165 ;
     RECT  12.432 22.165 13.704 22.213 ;
     RECT  26.4 21.973 35.256 22.307 ;
     RECT  36.24 21.779 40.776 22.307 ;
     RECT  45.6 22.165 47.544 22.307 ;
     RECT  14.784 19.333 21.288 22.451 ;
     RECT  45.6 22.307 46.152 22.547 ;
     RECT  48.528 22.021 62.712 22.547 ;
     RECT  3.888 20.965 4.536 22.645 ;
     RECT  12.24 22.213 13.704 22.645 ;
     RECT  14.784 22.451 16.2 22.645 ;
     RECT  3.888 22.645 5.112 22.691 ;
     RECT  2.4 20.965 2.904 22.741 ;
     RECT  3.888 22.691 3.912 22.741 ;
     RECT  17.424 22.451 21.288 22.741 ;
     RECT  22.32 21.637 25.224 22.741 ;
     RECT  12.24 22.645 16.2 23.075 ;
     RECT  42 22.115 44.472 23.075 ;
     RECT  12.432 23.075 16.2 23.171 ;
     RECT  47.232 22.307 47.544 23.171 ;
     RECT  34.224 22.307 35.256 23.363 ;
     RECT  43.584 23.075 44.472 23.363 ;
     RECT  43.92 23.363 44.472 23.411 ;
     RECT  48.576 22.547 62.712 23.411 ;
     RECT  44.16 23.411 44.472 23.845 ;
     RECT  45.6 22.547 46.104 23.845 ;
     RECT  64.608 23.557 64.632 23.939 ;
     RECT  44.16 23.845 46.104 23.989 ;
     RECT  47.232 23.171 47.256 23.989 ;
     RECT  44.16 23.989 47.256 24.035 ;
     RECT  44.16 24.035 44.184 24.131 ;
     RECT  12.432 23.171 15.768 24.421 ;
     RECT  26.4 22.307 33.144 24.421 ;
     RECT  34.368 23.363 35.256 24.421 ;
     RECT  26.4 24.421 35.256 24.469 ;
     RECT  36.24 22.307 40.512 24.469 ;
     RECT  26.4 24.469 40.512 24.515 ;
     RECT  5.088 22.691 5.112 24.563 ;
     RECT  27.84 24.515 40.512 24.659 ;
     RECT  48.576 23.411 62.664 24.659 ;
     RECT  6.864 21.061 10.92 24.757 ;
     RECT  48.576 24.659 62.472 24.757 ;
     RECT  34.8 24.659 40.512 24.853 ;
     RECT  45.504 24.035 47.256 24.901 ;
     RECT  48.48 24.757 62.472 24.901 ;
     RECT  43.2 24.805 43.224 24.947 ;
     RECT  45.504 24.901 62.472 25.043 ;
     RECT  47.232 25.043 62.472 25.091 ;
     RECT  47.232 25.091 48.744 25.139 ;
     RECT  43.008 25.093 43.032 25.283 ;
     RECT  2.4 22.741 3.912 25.573 ;
     RECT  6.864 24.757 11.016 25.667 ;
     RECT  34.8 24.853 40.632 25.765 ;
     RECT  34.8 25.765 40.92 25.955 ;
     RECT  17.424 22.741 25.224 26.149 ;
     RECT  26.4 24.515 26.856 26.149 ;
     RECT  2.4 25.573 4.632 26.243 ;
     RECT  17.424 26.149 26.856 26.243 ;
     RECT  47.232 25.139 47.256 26.243 ;
     RECT  42 23.075 42.024 26.245 ;
     RECT  17.568 26.243 26.856 26.387 ;
     RECT  42 26.245 42.168 26.533 ;
     RECT  43.296 26.389 43.32 26.533 ;
     RECT  48.336 25.139 48.744 26.533 ;
     RECT  6.96 25.667 11.016 26.629 ;
     RECT  12.336 24.421 15.768 26.629 ;
     RECT  45.504 25.043 46.008 26.819 ;
     RECT  49.92 25.091 62.472 26.915 ;
     RECT  47.856 26.533 48.744 27.013 ;
     RECT  6.96 26.629 15.768 27.301 ;
     RECT  18.336 26.387 26.856 27.347 ;
     RECT  27.84 24.659 33.624 27.395 ;
     RECT  45.504 26.819 45.912 27.493 ;
     RECT  18.336 27.347 22.584 27.733 ;
     RECT  6.96 27.301 15.912 27.781 ;
     RECT  47.856 27.013 48.888 27.781 ;
     RECT  49.92 26.915 62.328 27.781 ;
     RECT  47.856 27.781 62.328 27.877 ;
     RECT  42 26.533 43.32 28.115 ;
     RECT  28.512 27.395 33.624 28.163 ;
     RECT  44.976 27.493 45.912 28.165 ;
     RECT  23.856 27.347 26.856 28.405 ;
     RECT  28.512 28.163 31.848 28.405 ;
     RECT  42.48 28.115 43.32 28.451 ;
     RECT  5.088 26.773 5.112 28.453 ;
     RECT  32.832 28.163 33.624 28.453 ;
     RECT  34.8 25.955 40.512 28.453 ;
     RECT  18.24 27.733 22.584 28.499 ;
     RECT  32.832 28.453 40.512 28.499 ;
     RECT  44.976 28.165 46.008 28.501 ;
     RECT  2.4 26.243 3.96 28.595 ;
     RECT  47.856 27.877 62.664 28.595 ;
     RECT  47.856 28.595 59.784 28.691 ;
     RECT  6.96 27.781 16.584 28.787 ;
     RECT  39.696 28.499 40.512 28.835 ;
     RECT  5.04 28.453 5.112 28.837 ;
     RECT  47.856 28.691 59.64 29.027 ;
     RECT  64.608 28.741 64.632 29.027 ;
     RECT  23.856 28.405 31.848 29.029 ;
     RECT  7.008 28.787 16.584 29.075 ;
     RECT  44.352 28.501 46.008 29.075 ;
     RECT  47.856 29.027 48.744 29.123 ;
     RECT  23.568 29.029 31.848 29.171 ;
     RECT  27.696 29.171 31.848 29.363 ;
     RECT  4.992 28.837 5.112 29.557 ;
     RECT  42.48 28.451 43.08 29.557 ;
     RECT  44.352 29.075 44.376 29.603 ;
     RECT  18.432 28.499 22.584 29.605 ;
     RECT  39.984 28.835 40.512 29.605 ;
     RECT  41.616 29.557 43.08 29.605 ;
     RECT  2.4 28.595 2.856 29.797 ;
     RECT  3.936 28.595 3.96 29.797 ;
     RECT  7.008 29.075 11.352 29.843 ;
     RECT  17.952 29.605 22.584 29.845 ;
     RECT  23.568 29.171 26.472 29.845 ;
     RECT  49.92 29.027 59.64 29.845 ;
     RECT  60.768 28.595 62.664 29.845 ;
     RECT  2.4 29.797 3.96 30.037 ;
     RECT  27.744 29.363 31.848 30.037 ;
     RECT  32.832 28.499 38.376 30.037 ;
     RECT  49.92 29.845 62.664 30.085 ;
     RECT  39.984 29.605 43.08 30.133 ;
     RECT  49.008 30.085 62.664 30.227 ;
     RECT  12.336 29.075 16.584 30.373 ;
     RECT  47.856 29.123 47.976 30.421 ;
     RECT  49.2 30.227 62.664 30.515 ;
     RECT  17.952 29.845 26.472 30.611 ;
     RECT  39.936 30.133 43.32 30.661 ;
     RECT  45.504 29.075 46.008 30.709 ;
     RECT  47.664 30.421 47.976 30.709 ;
     RECT  39.936 30.661 43.848 30.803 ;
     RECT  2.304 30.037 3.96 30.851 ;
     RECT  4.992 29.557 5.16 30.899 ;
     RECT  12.336 30.373 16.824 30.949 ;
     RECT  45.504 30.709 47.976 30.997 ;
     RECT  45.504 30.997 48.072 31.141 ;
     RECT  49.2 30.515 62.328 31.333 ;
     RECT  5.136 30.899 5.16 31.427 ;
     RECT  18.048 30.611 26.472 31.669 ;
     RECT  27.744 30.037 38.376 31.669 ;
     RECT  39.936 30.803 43.32 31.669 ;
     RECT  18.048 31.669 38.376 31.717 ;
     RECT  39.888 31.669 43.32 31.717 ;
     RECT  45.408 31.141 48.072 31.813 ;
     RECT  12.336 30.949 17.064 31.955 ;
     RECT  18.048 31.717 43.32 31.955 ;
     RECT  44.448 31.813 48.072 31.955 ;
     RECT  2.304 30.851 3.432 32.003 ;
     RECT  44.448 31.955 47.928 32.243 ;
     RECT  18.048 31.955 40.512 32.291 ;
     RECT  17.04 31.955 17.064 32.437 ;
     RECT  18.048 32.291 28.152 32.437 ;
     RECT  49.056 31.333 62.328 32.531 ;
     RECT  44.448 32.243 47.88 32.579 ;
     RECT  45.408 32.579 47.88 32.675 ;
     RECT  41.616 31.955 42.744 32.771 ;
     RECT  2.4 32.003 3.432 33.061 ;
     RECT  49.2 32.531 62.328 33.109 ;
     RECT  49.2 33.109 62.472 33.395 ;
     RECT  41.904 32.771 42.744 33.443 ;
     RECT  45.408 32.675 47.064 33.589 ;
     RECT  7.2 29.843 11.352 33.637 ;
     RECT  12.336 31.955 15.72 33.637 ;
     RECT  44.592 33.589 47.064 33.925 ;
     RECT  43.872 33.925 47.064 33.971 ;
     RECT  45.408 33.971 47.064 33.973 ;
     RECT  17.04 32.437 28.152 34.067 ;
     RECT  45.408 33.973 48.024 34.069 ;
     RECT  7.2 33.637 15.72 34.165 ;
     RECT  2.4 33.061 3.624 34.309 ;
     RECT  2.4 34.309 3.864 34.355 ;
     RECT  29.4 32.291 40.512 34.499 ;
     RECT  43.872 33.971 43.896 34.645 ;
     RECT  49.2 33.395 57.96 34.693 ;
     RECT  59.28 33.395 62.472 34.693 ;
     RECT  17.04 34.067 27.432 34.739 ;
     RECT  33.888 34.499 40.512 34.739 ;
     RECT  6.912 34.165 15.72 34.741 ;
     RECT  17.04 34.739 26.472 34.741 ;
     RECT  41.904 33.443 42.168 34.741 ;
     RECT  43.248 34.645 43.896 34.787 ;
     RECT  45.408 34.069 48.12 34.979 ;
     RECT  43.872 34.787 43.896 35.029 ;
     RECT  45.408 34.979 48.024 35.029 ;
     RECT  33.888 34.739 35.256 35.075 ;
     RECT  49.2 34.693 62.472 35.171 ;
     RECT  64.608 35.029 64.632 35.219 ;
     RECT  43.872 35.029 48.024 35.267 ;
     RECT  49.2 35.171 59.064 35.267 ;
     RECT  41.616 34.741 42.168 35.269 ;
     RECT  6.912 34.741 26.472 35.411 ;
     RECT  44.448 35.267 48.024 35.459 ;
     RECT  3.84 34.355 3.864 35.509 ;
     RECT  60.048 35.171 62.472 36.421 ;
     RECT  7.2 35.411 26.472 36.517 ;
     RECT  5.712 34.165 5.736 36.563 ;
     RECT  49.2 35.267 58.824 36.565 ;
     RECT  44.448 35.459 47.064 36.613 ;
     RECT  49.056 36.565 58.824 36.661 ;
     RECT  59.808 36.421 62.472 36.661 ;
     RECT  44.448 36.613 47.304 36.757 ;
     RECT  49.056 36.661 62.472 36.805 ;
     RECT  2.4 34.355 2.808 36.851 ;
     RECT  34.128 35.075 35.256 36.947 ;
     RECT  48.912 36.805 62.472 36.949 ;
     RECT  7.152 36.517 26.472 37.093 ;
     RECT  48.864 36.949 62.472 37.093 ;
     RECT  41.616 35.269 42.648 37.139 ;
     RECT  3.84 35.509 4.536 37.141 ;
     RECT  29.4 34.499 32.856 37.141 ;
     RECT  48.864 37.093 62.712 37.141 ;
     RECT  29.4 37.141 32.952 37.283 ;
     RECT  44.16 36.757 47.304 37.379 ;
     RECT  36.24 34.739 40.512 37.573 ;
     RECT  48.816 37.141 62.712 37.573 ;
     RECT  3.84 37.141 5.4 37.859 ;
     RECT  29.4 37.283 32.856 37.861 ;
     RECT  28.704 37.861 32.856 37.909 ;
     RECT  36.24 37.573 40.632 38.437 ;
     RECT  41.904 37.139 42.648 38.579 ;
     RECT  36.24 38.437 40.728 38.819 ;
     RECT  44.16 37.379 46.824 39.011 ;
     RECT  64.608 39.061 64.632 39.251 ;
     RECT  34.464 36.947 35.256 39.349 ;
     RECT  36.24 38.819 38.376 39.349 ;
     RECT  45.6 39.011 46.824 39.395 ;
     RECT  4.512 37.859 5.304 39.443 ;
     RECT  7.152 37.093 27.336 39.443 ;
     RECT  48.816 37.573 63.24 39.683 ;
     RECT  60.144 39.683 63.24 39.779 ;
     RECT  39.6 38.819 40.728 39.877 ;
     RECT  42.048 38.579 42.648 39.877 ;
     RECT  34.464 39.349 38.376 39.923 ;
     RECT  44.16 39.011 44.376 39.971 ;
     RECT  39.6 39.877 42.648 40.115 ;
     RECT  15.648 39.443 27.336 40.403 ;
     RECT  39.6 40.115 42.504 40.403 ;
     RECT  2.4 36.851 2.712 40.405 ;
     RECT  4.512 39.443 5.16 40.405 ;
     RECT  60.144 39.779 63.192 40.499 ;
     RECT  7.152 39.443 14.568 40.693 ;
     RECT  28.608 37.909 32.856 40.693 ;
     RECT  28.608 40.693 33 40.741 ;
     RECT  6.672 40.693 14.568 40.981 ;
     RECT  28.56 40.741 33 40.981 ;
     RECT  34.512 39.923 38.376 40.981 ;
     RECT  48.816 39.683 59.112 41.027 ;
     RECT  60.144 40.499 62.712 41.027 ;
     RECT  44.352 39.971 44.376 41.029 ;
     RECT  45.6 39.395 46.584 41.029 ;
     RECT  42.48 40.403 42.504 41.075 ;
     RECT  28.56 40.981 38.376 41.171 ;
     RECT  48.912 41.027 59.112 41.461 ;
     RECT  60.144 41.027 62.472 41.461 ;
     RECT  64.608 41.125 64.632 41.603 ;
     RECT  28.56 41.171 33.672 41.651 ;
     RECT  6.672 40.981 14.664 41.701 ;
     RECT  15.648 40.403 27.288 41.701 ;
     RECT  6.672 41.701 27.288 41.747 ;
     RECT  45.6 41.029 46.68 41.797 ;
     RECT  34.656 41.171 38.376 42.037 ;
     RECT  39.6 40.403 41.496 42.037 ;
     RECT  2.4 40.405 5.16 42.179 ;
     RECT  34.656 42.037 41.496 42.325 ;
     RECT  6.672 41.747 16.344 42.565 ;
     RECT  43.68 41.029 44.376 42.755 ;
     RECT  45.6 41.797 46.728 42.755 ;
     RECT  48.912 41.461 62.472 42.755 ;
     RECT  17.376 41.747 27.288 42.757 ;
     RECT  28.56 41.651 32.856 42.757 ;
     RECT  17.376 42.757 32.856 43.619 ;
     RECT  25.344 43.619 32.856 43.717 ;
     RECT  34.416 42.325 41.496 43.717 ;
     RECT  60 42.755 62.472 43.717 ;
     RECT  45.6 42.755 46.68 43.765 ;
     RECT  48.912 42.755 58.632 43.765 ;
     RECT  48.912 43.765 58.728 43.861 ;
     RECT  59.904 43.717 62.472 43.861 ;
     RECT  25.344 43.717 41.496 43.907 ;
     RECT  44.352 42.755 44.376 43.907 ;
     RECT  6.48 42.565 16.344 44.099 ;
     RECT  48.912 43.861 62.472 44.389 ;
     RECT  7.2 44.099 16.344 44.483 ;
     RECT  17.376 43.619 24.312 44.629 ;
     RECT  25.344 43.907 38.376 44.629 ;
     RECT  2.4 42.179 5.064 44.725 ;
     RECT  17.376 44.629 38.376 44.771 ;
     RECT  24 44.771 38.376 44.867 ;
     RECT  45.6 43.765 47.64 44.965 ;
     RECT  7.2 44.483 15.816 45.059 ;
     RECT  39.36 43.907 41.496 45.059 ;
     RECT  2.4 44.725 5.16 45.155 ;
     RECT  39.744 45.059 41.496 45.445 ;
     RECT  43.488 44.965 43.512 45.445 ;
     RECT  39.744 45.445 41.592 45.541 ;
     RECT  45.216 44.965 47.64 45.541 ;
     RECT  48.672 44.389 62.472 45.541 ;
     RECT  7.2 45.059 14.184 45.731 ;
     RECT  7.2 45.731 13.848 45.733 ;
     RECT  45.216 45.541 62.472 45.779 ;
     RECT  7.152 45.733 13.848 46.117 ;
     RECT  2.4 45.155 4.2 46.211 ;
     RECT  15.648 45.059 15.816 46.259 ;
     RECT  17.376 44.771 22.728 46.261 ;
     RECT  24 44.867 33.048 46.403 ;
     RECT  43.488 45.445 43.608 46.597 ;
     RECT  45.216 45.779 62.424 46.597 ;
     RECT  43.488 46.597 62.424 46.643 ;
     RECT  39.744 45.541 41.64 46.787 ;
     RECT  24 46.403 32.856 46.883 ;
     RECT  44.352 46.643 62.424 46.981 ;
     RECT  24 46.883 32.52 47.027 ;
     RECT  15.648 46.259 15.672 47.077 ;
     RECT  40.032 46.787 41.64 47.077 ;
     RECT  25.344 47.027 32.52 47.171 ;
     RECT  40.032 47.077 41.88 47.173 ;
     RECT  15.552 47.077 15.672 47.221 ;
     RECT  17.376 46.261 22.872 47.605 ;
     RECT  7.104 46.117 13.848 47.651 ;
     RECT  5.136 46.597 5.16 47.701 ;
     RECT  44.352 46.981 63.24 47.701 ;
     RECT  34.416 44.867 38.376 47.747 ;
     RECT  14.976 47.221 15.672 47.843 ;
     RECT  2.4 46.211 3.96 47.845 ;
     RECT  7.2 47.651 13.848 47.845 ;
     RECT  40.032 47.173 42.84 47.845 ;
     RECT  17.232 47.605 22.872 48.229 ;
     RECT  40.032 47.845 43.224 48.229 ;
     RECT  25.344 47.171 32.424 48.275 ;
     RECT  26.448 48.275 32.424 48.805 ;
     RECT  33.408 48.421 33.432 48.805 ;
     RECT  2.4 47.845 4.008 48.901 ;
     RECT  5.136 47.701 5.352 48.901 ;
     RECT  34.8 47.747 38.376 48.901 ;
     RECT  40.032 48.229 43.272 48.901 ;
     RECT  2.4 48.901 5.352 48.995 ;
     RECT  34.8 48.901 43.272 49.091 ;
     RECT  40.032 49.091 43.272 49.237 ;
     RECT  44.304 47.701 63.24 49.237 ;
     RECT  26.448 48.805 33.432 49.427 ;
     RECT  25.344 48.275 25.368 49.525 ;
     RECT  26.448 49.427 33.096 49.525 ;
     RECT  40.032 49.237 63.24 49.715 ;
     RECT  17.088 48.229 22.872 49.909 ;
     RECT  24 47.027 24.312 50.101 ;
     RECT  25.344 49.525 33.096 50.101 ;
     RECT  34.8 49.091 38.376 50.149 ;
     RECT  40.032 49.715 43.512 50.149 ;
     RECT  44.496 49.715 63.24 50.195 ;
     RECT  17.088 49.909 22.968 50.293 ;
     RECT  24 50.101 33.096 50.293 ;
     RECT  17.088 50.293 33.096 50.339 ;
     RECT  64.608 49.765 64.632 50.579 ;
     RECT  17.088 50.339 32.424 50.725 ;
     RECT  44.496 50.195 62.472 50.771 ;
     RECT  34.8 50.149 43.512 50.821 ;
     RECT  44.496 50.771 58.824 50.821 ;
     RECT  7.2 47.845 13.992 51.203 ;
     RECT  17.04 50.725 32.424 51.347 ;
     RECT  59.808 50.771 62.472 51.347 ;
     RECT  34.8 50.821 58.824 51.541 ;
     RECT  34.704 51.541 58.824 51.973 ;
     RECT  7.2 51.203 13.848 52.069 ;
     RECT  2.4 48.995 5.256 52.211 ;
     RECT  6.816 52.069 13.848 52.259 ;
     RECT  34.656 51.973 58.824 52.259 ;
     RECT  40.032 52.259 58.824 52.453 ;
     RECT  59.856 51.347 62.472 52.453 ;
     RECT  40.032 52.453 62.472 52.499 ;
     RECT  17.712 51.347 32.424 52.501 ;
     RECT  34.656 52.259 38.808 52.643 ;
     RECT  34.704 52.643 38.808 53.123 ;
     RECT  34.8 53.123 38.808 53.413 ;
     RECT  40.032 52.499 62.424 53.413 ;
     RECT  17.664 52.501 32.424 53.555 ;
     RECT  7.2 52.259 13.848 54.037 ;
     RECT  34.8 53.413 62.424 54.131 ;
     RECT  2.4 52.211 5.16 54.419 ;
     RECT  17.664 53.555 24.504 54.419 ;
     RECT  17.664 54.419 22.728 54.515 ;
     RECT  34.8 54.131 40.512 54.661 ;
     RECT  23.712 54.419 24.504 54.707 ;
     RECT  41.568 54.131 62.424 54.707 ;
     RECT  7.104 54.037 13.848 54.995 ;
     RECT  25.536 53.555 32.424 55.331 ;
     RECT  7.2 54.995 13.848 55.429 ;
     RECT  34.416 54.661 40.512 55.475 ;
     RECT  15.552 47.843 15.672 55.621 ;
     RECT  17.808 54.515 22.728 55.621 ;
     RECT  23.712 54.707 24.408 55.621 ;
     RECT  15.552 55.621 16.296 55.813 ;
     RECT  34.8 55.475 40.512 55.813 ;
     RECT  41.568 54.707 58.152 55.813 ;
     RECT  7.2 55.429 14.232 55.955 ;
     RECT  17.808 55.621 24.408 56.005 ;
     RECT  25.68 55.331 32.424 56.389 ;
     RECT  59.136 54.707 62.424 56.579 ;
     RECT  34.8 55.813 58.152 56.869 ;
     RECT  7.2 55.955 13.848 56.965 ;
     RECT  33.984 56.869 58.152 57.011 ;
     RECT  59.184 56.579 62.424 57.011 ;
     RECT  6.864 56.965 13.848 57.061 ;
     RECT  15.552 55.813 16.584 57.061 ;
     RECT  44.016 57.011 58.152 57.395 ;
     RECT  47.136 57.395 58.152 57.491 ;
     RECT  2.4 54.419 4.824 57.541 ;
     RECT  48.144 57.491 58.152 57.635 ;
     RECT  17.664 56.005 24.408 57.685 ;
     RECT  25.632 56.389 32.424 57.685 ;
     RECT  59.184 57.011 62.328 57.731 ;
     RECT  34.8 57.011 43.032 57.827 ;
     RECT  44.016 57.395 45.912 57.875 ;
     RECT  44.208 57.875 45.912 57.971 ;
     RECT  33.696 57.589 33.72 58.067 ;
     RECT  48.768 57.635 58.152 58.115 ;
     RECT  2.304 57.541 4.824 58.163 ;
     RECT  34.8 57.827 42.456 58.163 ;
     RECT  6.864 57.061 16.584 58.259 ;
     RECT  6.864 58.259 16.344 58.403 ;
     RECT  64.656 58.213 64.68 58.451 ;
     RECT  6.864 58.403 14.616 58.693 ;
     RECT  2.304 58.163 4.632 58.787 ;
     RECT  2.4 58.787 4.632 58.835 ;
     RECT  17.664 57.685 32.424 58.883 ;
     RECT  47.136 57.491 47.16 58.885 ;
     RECT  15.648 58.403 16.344 58.931 ;
     RECT  44.208 57.971 44.232 58.981 ;
     RECT  45.312 57.971 45.912 58.981 ;
     RECT  59.568 57.731 62.328 58.981 ;
     RECT  34.8 58.163 41.976 59.171 ;
     RECT  47.04 58.885 47.16 59.173 ;
     RECT  17.664 58.883 24.312 59.315 ;
     RECT  34.8 59.171 41.016 59.315 ;
     RECT  44.208 58.981 45.912 59.315 ;
     RECT  18.48 59.315 24.312 59.411 ;
     RECT  25.632 58.883 32.424 59.555 ;
     RECT  26.448 59.555 32.424 59.557 ;
     RECT  6.288 58.693 14.616 59.891 ;
     RECT  40.2 59.315 41.016 60.035 ;
     RECT  6.816 59.891 14.616 60.373 ;
     RECT  15.648 58.931 16.296 60.373 ;
     RECT  59.472 58.981 62.328 60.419 ;
     RECT  18.6 59.411 24.312 60.467 ;
     RECT  26.448 59.557 32.664 60.467 ;
     RECT  34.8 59.315 39.192 60.563 ;
     RECT  26.448 60.467 32.424 60.661 ;
     RECT  46.944 59.173 47.16 60.707 ;
     RECT  44.736 59.315 45.912 60.851 ;
     RECT  2.4 58.835 4.296 60.899 ;
     RECT  64.608 60.613 64.632 60.899 ;
     RECT  34.8 60.563 38.808 60.997 ;
     RECT  6.816 60.373 16.296 61.043 ;
     RECT  59.76 60.419 62.328 61.043 ;
     RECT  7.2 61.043 16.296 61.187 ;
     RECT  60.288 61.043 62.328 61.187 ;
     RECT  34.368 60.997 38.808 61.379 ;
     RECT  40.2 60.035 40.776 61.477 ;
     RECT  25.776 60.661 32.424 61.619 ;
     RECT  26.448 61.619 32.424 61.621 ;
     RECT  60.816 61.187 62.328 61.669 ;
     RECT  48.864 58.115 58.152 61.861 ;
     RECT  18.6 60.467 22.536 61.909 ;
     RECT  48.624 61.861 58.152 61.909 ;
     RECT  47.04 60.707 47.16 62.005 ;
     RECT  48.624 61.909 58.824 62.005 ;
     RECT  2.4 60.899 2.808 62.149 ;
     RECT  3.888 60.899 4.296 62.149 ;
     RECT  60.816 61.669 62.376 62.149 ;
     RECT  63.6 61.573 63.624 62.149 ;
     RECT  23.904 60.467 24.312 62.195 ;
     RECT  7.2 61.187 15.672 62.197 ;
     RECT  7.2 62.197 16.68 62.245 ;
     RECT  17.904 61.909 22.536 62.245 ;
     RECT  2.4 62.149 4.296 62.341 ;
     RECT  5.616 62.149 5.64 62.341 ;
     RECT  45.6 60.851 45.912 62.437 ;
     RECT  47.04 62.005 58.824 62.437 ;
     RECT  40.2 61.477 41.4 62.483 ;
     RECT  2.4 62.341 5.64 62.485 ;
     RECT  43.296 60.661 43.32 62.579 ;
     RECT  2.4 62.485 5.736 62.581 ;
     RECT  26.448 61.621 32.712 62.629 ;
     RECT  45.6 62.437 58.824 62.629 ;
     RECT  60.24 62.149 63.624 62.629 ;
     RECT  24 62.195 24.312 62.649 ;
     RECT  40.2 62.483 40.512 62.649 ;
     RECT  2.4 62.581 6.12 62.663 ;
     RECT  24 62.649 24.12 62.663 ;
     RECT  40.2 62.649 40.32 62.663 ;
     RECT  45.6 62.629 59.112 62.663 ;
     RECT  3.408 62.663 6.12 62.677 ;
     RECT  26.448 62.629 33 62.677 ;
     RECT  34.368 61.379 38.376 62.677 ;
     RECT  45.648 62.663 59.112 62.677 ;
     RECT  45.648 62.677 59.208 62.725 ;
     RECT  60.24 62.629 63.816 62.725 ;
     RECT  26.448 62.677 38.376 63.205 ;
     RECT  3.408 62.677 6.216 63.733 ;
     RECT  7.2 62.245 22.536 63.733 ;
     RECT  26.064 63.205 38.376 63.781 ;
     RECT  26.064 63.781 38.568 63.829 ;
     RECT  45.648 62.725 63.912 63.877 ;
     RECT  26.064 63.829 38.664 64.597 ;
     RECT  25.968 64.597 38.664 64.645 ;
     RECT  3.408 63.733 22.536 64.784 ;
     RECT  25.872 64.645 38.664 64.784 ;
     RECT  45.648 63.877 64.008 64.784 ;
     RECT  47.136 64.784 47.16 64.787 ;
  END
END dsfd_r2l_vr_512x1__hsel
END LIBRARY
